VERSION 5.8 ;
BUSBITCHARS "[]" ;
DIVIDERCHAR "/" ;
UNITS
    DATABASE MICRONS 1000 ;
END UNITS

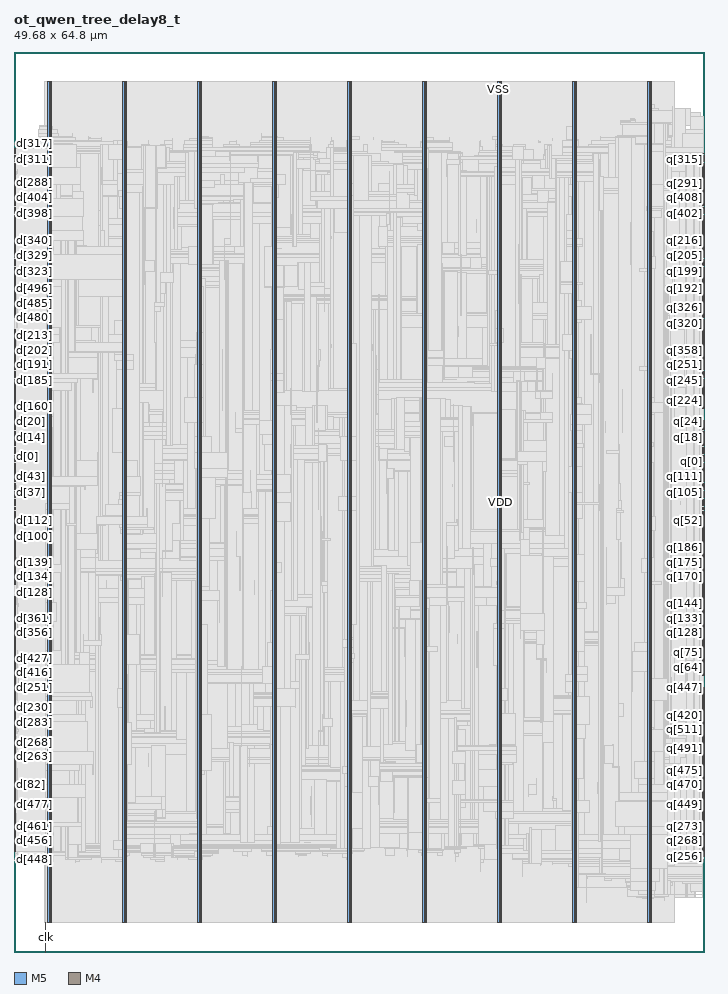
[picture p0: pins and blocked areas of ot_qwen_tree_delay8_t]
MACRO ot_qwen_tree_delay8_t
  FOREIGN ot_qwen_tree_delay8_t 0 0 ;
  CLASS BLOCK ;
  SIZE 49.68 BY 64.8 ;
  PIN clk
    DIRECTION INPUT ;
    USE SIGNAL ;
    PORT
      LAYER M5 ;
        RECT  2.256 0 2.28 0.084 ;
    END
    PORT
      LAYER M5 ;
        RECT  2.256 0.016 2.28 2.137 ;
    END
  END clk
  PIN d[0]
    DIRECTION INPUT ;
    USE SIGNAL ;
    PORT
      LAYER M4 ;
        RECT  0 35.664 0.084 35.688 ;
    END
  END d[0]
  PIN d[100]
    DIRECTION INPUT ;
    USE SIGNAL ;
    PORT
      LAYER M4 ;
        RECT  0 29.904 0.084 29.928 ;
    END
  END d[100]
  PIN d[101]
    DIRECTION INPUT ;
    USE SIGNAL ;
    PORT
      LAYER M4 ;
        RECT  0 30 0.084 30.024 ;
    END
  END d[101]
  PIN d[102]
    DIRECTION INPUT ;
    USE SIGNAL ;
    PORT
      LAYER M4 ;
        RECT  0 30.096 0.084 30.12 ;
    END
  END d[102]
  PIN d[103]
    DIRECTION INPUT ;
    USE SIGNAL ;
    PORT
      LAYER M4 ;
        RECT  0 30.192 0.084 30.216 ;
    END
  END d[103]
  PIN d[104]
    DIRECTION INPUT ;
    USE SIGNAL ;
    PORT
      LAYER M4 ;
        RECT  0 30.288 0.084 30.312 ;
    END
  END d[104]
  PIN d[105]
    DIRECTION INPUT ;
    USE SIGNAL ;
    PORT
      LAYER M4 ;
        RECT  0 30.384 0.084 30.408 ;
    END
  END d[105]
  PIN d[106]
    DIRECTION INPUT ;
    USE SIGNAL ;
    PORT
      LAYER M4 ;
        RECT  0 30.48 0.084 30.504 ;
    END
  END d[106]
  PIN d[107]
    DIRECTION INPUT ;
    USE SIGNAL ;
    PORT
      LAYER M4 ;
        RECT  0 30.576 0.084 30.6 ;
    END
  END d[107]
  PIN d[108]
    DIRECTION INPUT ;
    USE SIGNAL ;
    PORT
      LAYER M4 ;
        RECT  0 30.672 0.084 30.696 ;
    END
  END d[108]
  PIN d[109]
    DIRECTION INPUT ;
    USE SIGNAL ;
    PORT
      LAYER M4 ;
        RECT  0 30.768 0.084 30.792 ;
    END
  END d[109]
  PIN d[10]
    DIRECTION INPUT ;
    USE SIGNAL ;
    PORT
      LAYER M4 ;
        RECT  0 36.624 0.084 36.648 ;
    END
  END d[10]
  PIN d[110]
    DIRECTION INPUT ;
    USE SIGNAL ;
    PORT
      LAYER M4 ;
        RECT  0 30.864 0.084 30.888 ;
    END
  END d[110]
  PIN d[111]
    DIRECTION INPUT ;
    USE SIGNAL ;
    PORT
      LAYER M4 ;
        RECT  0 30.96 0.084 30.984 ;
    END
  END d[111]
  PIN d[112]
    DIRECTION INPUT ;
    USE SIGNAL ;
    PORT
      LAYER M4 ;
        RECT  0 31.056 0.084 31.08 ;
    END
  END d[112]
  PIN d[113]
    DIRECTION INPUT ;
    USE SIGNAL ;
    PORT
      LAYER M4 ;
        RECT  0 31.152 0.084 31.176 ;
    END
  END d[113]
  PIN d[114]
    DIRECTION INPUT ;
    USE SIGNAL ;
    PORT
      LAYER M4 ;
        RECT  0 31.248 0.084 31.272 ;
    END
  END d[114]
  PIN d[115]
    DIRECTION INPUT ;
    USE SIGNAL ;
    PORT
      LAYER M4 ;
        RECT  0 31.344 0.084 31.368 ;
    END
  END d[115]
  PIN d[116]
    DIRECTION INPUT ;
    USE SIGNAL ;
    PORT
      LAYER M4 ;
        RECT  0 31.44 0.084 31.464 ;
    END
  END d[116]
  PIN d[117]
    DIRECTION INPUT ;
    USE SIGNAL ;
    PORT
      LAYER M4 ;
        RECT  0 31.536 0.084 31.56 ;
    END
  END d[117]
  PIN d[118]
    DIRECTION INPUT ;
    USE SIGNAL ;
    PORT
      LAYER M4 ;
        RECT  0 31.632 0.084 31.656 ;
    END
  END d[118]
  PIN d[119]
    DIRECTION INPUT ;
    USE SIGNAL ;
    PORT
      LAYER M4 ;
        RECT  0 31.728 0.084 31.752 ;
    END
  END d[119]
  PIN d[11]
    DIRECTION INPUT ;
    USE SIGNAL ;
    PORT
      LAYER M4 ;
        RECT  0 36.72 0.084 36.744 ;
    END
  END d[11]
  PIN d[120]
    DIRECTION INPUT ;
    USE SIGNAL ;
    PORT
      LAYER M4 ;
        RECT  0 31.824 0.084 31.848 ;
    END
  END d[120]
  PIN d[121]
    DIRECTION INPUT ;
    USE SIGNAL ;
    PORT
      LAYER M4 ;
        RECT  0 31.92 0.084 31.944 ;
    END
  END d[121]
  PIN d[122]
    DIRECTION INPUT ;
    USE SIGNAL ;
    PORT
      LAYER M4 ;
        RECT  0 32.016 0.084 32.04 ;
    END
  END d[122]
  PIN d[123]
    DIRECTION INPUT ;
    USE SIGNAL ;
    PORT
      LAYER M4 ;
        RECT  0 32.112 0.084 32.136 ;
    END
  END d[123]
  PIN d[124]
    DIRECTION INPUT ;
    USE SIGNAL ;
    PORT
      LAYER M4 ;
        RECT  0 32.208 0.084 32.232 ;
    END
  END d[124]
  PIN d[125]
    DIRECTION INPUT ;
    USE SIGNAL ;
    PORT
      LAYER M4 ;
        RECT  0 32.304 0.084 32.328 ;
    END
  END d[125]
  PIN d[126]
    DIRECTION INPUT ;
    USE SIGNAL ;
    PORT
      LAYER M4 ;
        RECT  0 32.4 0.084 32.424 ;
    END
  END d[126]
  PIN d[127]
    DIRECTION INPUT ;
    USE SIGNAL ;
    PORT
      LAYER M4 ;
        RECT  0 32.496 0.084 32.52 ;
    END
  END d[127]
  PIN d[128]
    DIRECTION INPUT ;
    USE SIGNAL ;
    PORT
      LAYER M4 ;
        RECT  0 26.448 0.084 26.472 ;
    END
  END d[128]
  PIN d[129]
    DIRECTION INPUT ;
    USE SIGNAL ;
    PORT
      LAYER M4 ;
        RECT  0 26.544 0.084 26.568 ;
    END
  END d[129]
  PIN d[12]
    DIRECTION INPUT ;
    USE SIGNAL ;
    PORT
      LAYER M4 ;
        RECT  0 36.816 0.084 36.84 ;
    END
  END d[12]
  PIN d[130]
    DIRECTION INPUT ;
    USE SIGNAL ;
    PORT
      LAYER M4 ;
        RECT  0 26.64 0.084 26.664 ;
    END
  END d[130]
  PIN d[131]
    DIRECTION INPUT ;
    USE SIGNAL ;
    PORT
      LAYER M4 ;
        RECT  0 26.736 0.084 26.76 ;
    END
  END d[131]
  PIN d[132]
    DIRECTION INPUT ;
    USE SIGNAL ;
    PORT
      LAYER M4 ;
        RECT  0 26.832 0.084 26.856 ;
    END
  END d[132]
  PIN d[133]
    DIRECTION INPUT ;
    USE SIGNAL ;
    PORT
      LAYER M4 ;
        RECT  0 26.928 0.084 26.952 ;
    END
  END d[133]
  PIN d[134]
    DIRECTION INPUT ;
    USE SIGNAL ;
    PORT
      LAYER M4 ;
        RECT  0 27.024 0.084 27.048 ;
    END
  END d[134]
  PIN d[135]
    DIRECTION INPUT ;
    USE SIGNAL ;
    PORT
      LAYER M4 ;
        RECT  0 27.12 0.084 27.144 ;
    END
  END d[135]
  PIN d[136]
    DIRECTION INPUT ;
    USE SIGNAL ;
    PORT
      LAYER M4 ;
        RECT  0 27.216 0.084 27.24 ;
    END
  END d[136]
  PIN d[137]
    DIRECTION INPUT ;
    USE SIGNAL ;
    PORT
      LAYER M4 ;
        RECT  0 27.312 0.084 27.336 ;
    END
  END d[137]
  PIN d[138]
    DIRECTION INPUT ;
    USE SIGNAL ;
    PORT
      LAYER M4 ;
        RECT  0 27.408 0.084 27.432 ;
    END
  END d[138]
  PIN d[139]
    DIRECTION INPUT ;
    USE SIGNAL ;
    PORT
      LAYER M4 ;
        RECT  0 27.504 0.084 27.528 ;
    END
  END d[139]
  PIN d[13]
    DIRECTION INPUT ;
    USE SIGNAL ;
    PORT
      LAYER M4 ;
        RECT  0 36.912 0.084 36.936 ;
    END
  END d[13]
  PIN d[140]
    DIRECTION INPUT ;
    USE SIGNAL ;
    PORT
      LAYER M4 ;
        RECT  0 27.6 0.084 27.624 ;
    END
  END d[140]
  PIN d[141]
    DIRECTION INPUT ;
    USE SIGNAL ;
    PORT
      LAYER M4 ;
        RECT  0 27.696 0.084 27.72 ;
    END
  END d[141]
  PIN d[142]
    DIRECTION INPUT ;
    USE SIGNAL ;
    PORT
      LAYER M4 ;
        RECT  0 27.792 0.084 27.816 ;
    END
  END d[142]
  PIN d[143]
    DIRECTION INPUT ;
    USE SIGNAL ;
    PORT
      LAYER M4 ;
        RECT  0 27.888 0.084 27.912 ;
    END
  END d[143]
  PIN d[144]
    DIRECTION INPUT ;
    USE SIGNAL ;
    PORT
      LAYER M4 ;
        RECT  0 27.984 0.084 28.008 ;
    END
  END d[144]
  PIN d[145]
    DIRECTION INPUT ;
    USE SIGNAL ;
    PORT
      LAYER M4 ;
        RECT  0 28.08 0.084 28.104 ;
    END
  END d[145]
  PIN d[146]
    DIRECTION INPUT ;
    USE SIGNAL ;
    PORT
      LAYER M4 ;
        RECT  0 28.176 0.084 28.2 ;
    END
  END d[146]
  PIN d[147]
    DIRECTION INPUT ;
    USE SIGNAL ;
    PORT
      LAYER M4 ;
        RECT  0 28.272 0.084 28.296 ;
    END
  END d[147]
  PIN d[148]
    DIRECTION INPUT ;
    USE SIGNAL ;
    PORT
      LAYER M4 ;
        RECT  0 28.368 0.084 28.392 ;
    END
  END d[148]
  PIN d[149]
    DIRECTION INPUT ;
    USE SIGNAL ;
    PORT
      LAYER M4 ;
        RECT  0 28.464 0.084 28.488 ;
    END
  END d[149]
  PIN d[14]
    DIRECTION INPUT ;
    USE SIGNAL ;
    PORT
      LAYER M4 ;
        RECT  0 37.008 0.084 37.032 ;
    END
  END d[14]
  PIN d[150]
    DIRECTION INPUT ;
    USE SIGNAL ;
    PORT
      LAYER M4 ;
        RECT  0 28.56 0.084 28.584 ;
    END
  END d[150]
  PIN d[151]
    DIRECTION INPUT ;
    USE SIGNAL ;
    PORT
      LAYER M4 ;
        RECT  0 28.656 0.084 28.68 ;
    END
  END d[151]
  PIN d[152]
    DIRECTION INPUT ;
    USE SIGNAL ;
    PORT
      LAYER M4 ;
        RECT  0 28.752 0.084 28.776 ;
    END
  END d[152]
  PIN d[153]
    DIRECTION INPUT ;
    USE SIGNAL ;
    PORT
      LAYER M4 ;
        RECT  0 28.848 0.084 28.872 ;
    END
  END d[153]
  PIN d[154]
    DIRECTION INPUT ;
    USE SIGNAL ;
    PORT
      LAYER M4 ;
        RECT  0 28.944 0.084 28.968 ;
    END
  END d[154]
  PIN d[155]
    DIRECTION INPUT ;
    USE SIGNAL ;
    PORT
      LAYER M4 ;
        RECT  0 29.04 0.084 29.064 ;
    END
  END d[155]
  PIN d[156]
    DIRECTION INPUT ;
    USE SIGNAL ;
    PORT
      LAYER M4 ;
        RECT  0 29.136 0.084 29.16 ;
    END
  END d[156]
  PIN d[157]
    DIRECTION INPUT ;
    USE SIGNAL ;
    PORT
      LAYER M4 ;
        RECT  0 29.232 0.084 29.256 ;
    END
  END d[157]
  PIN d[158]
    DIRECTION INPUT ;
    USE SIGNAL ;
    PORT
      LAYER M4 ;
        RECT  0 29.328 0.084 29.352 ;
    END
  END d[158]
  PIN d[159]
    DIRECTION INPUT ;
    USE SIGNAL ;
    PORT
      LAYER M4 ;
        RECT  0 29.424 0.084 29.448 ;
    END
  END d[159]
  PIN d[15]
    DIRECTION INPUT ;
    USE SIGNAL ;
    PORT
      LAYER M4 ;
        RECT  0 37.104 0.084 37.128 ;
    END
  END d[15]
  PIN d[160]
    DIRECTION INPUT ;
    USE SIGNAL ;
    PORT
      LAYER M4 ;
        RECT  0 38.736 0.084 38.76 ;
    END
  END d[160]
  PIN d[161]
    DIRECTION INPUT ;
    USE SIGNAL ;
    PORT
      LAYER M4 ;
        RECT  0 38.832 0.084 38.856 ;
    END
  END d[161]
  PIN d[162]
    DIRECTION INPUT ;
    USE SIGNAL ;
    PORT
      LAYER M4 ;
        RECT  0 38.928 0.084 38.952 ;
    END
  END d[162]
  PIN d[163]
    DIRECTION INPUT ;
    USE SIGNAL ;
    PORT
      LAYER M4 ;
        RECT  0 39.024 0.084 39.048 ;
    END
  END d[163]
  PIN d[164]
    DIRECTION INPUT ;
    USE SIGNAL ;
    PORT
      LAYER M4 ;
        RECT  0 39.12 0.084 39.144 ;
    END
  END d[164]
  PIN d[165]
    DIRECTION INPUT ;
    USE SIGNAL ;
    PORT
      LAYER M4 ;
        RECT  0 39.216 0.084 39.24 ;
    END
  END d[165]
  PIN d[166]
    DIRECTION INPUT ;
    USE SIGNAL ;
    PORT
      LAYER M4 ;
        RECT  0 39.312 0.084 39.336 ;
    END
  END d[166]
  PIN d[167]
    DIRECTION INPUT ;
    USE SIGNAL ;
    PORT
      LAYER M4 ;
        RECT  0 39.408 0.084 39.432 ;
    END
  END d[167]
  PIN d[168]
    DIRECTION INPUT ;
    USE SIGNAL ;
    PORT
      LAYER M4 ;
        RECT  0 39.504 0.084 39.528 ;
    END
  END d[168]
  PIN d[169]
    DIRECTION INPUT ;
    USE SIGNAL ;
    PORT
      LAYER M4 ;
        RECT  0 39.6 0.084 39.624 ;
    END
  END d[169]
  PIN d[16]
    DIRECTION INPUT ;
    USE SIGNAL ;
    PORT
      LAYER M4 ;
        RECT  0 37.2 0.084 37.224 ;
    END
  END d[16]
  PIN d[170]
    DIRECTION INPUT ;
    USE SIGNAL ;
    PORT
      LAYER M4 ;
        RECT  0 39.696 0.084 39.72 ;
    END
  END d[170]
  PIN d[171]
    DIRECTION INPUT ;
    USE SIGNAL ;
    PORT
      LAYER M4 ;
        RECT  0 39.792 0.084 39.816 ;
    END
  END d[171]
  PIN d[172]
    DIRECTION INPUT ;
    USE SIGNAL ;
    PORT
      LAYER M4 ;
        RECT  0 39.888 0.084 39.912 ;
    END
  END d[172]
  PIN d[173]
    DIRECTION INPUT ;
    USE SIGNAL ;
    PORT
      LAYER M4 ;
        RECT  0 39.984 0.084 40.008 ;
    END
  END d[173]
  PIN d[174]
    DIRECTION INPUT ;
    USE SIGNAL ;
    PORT
      LAYER M4 ;
        RECT  0 40.08 0.084 40.104 ;
    END
  END d[174]
  PIN d[175]
    DIRECTION INPUT ;
    USE SIGNAL ;
    PORT
      LAYER M4 ;
        RECT  0 40.176 0.084 40.2 ;
    END
  END d[175]
  PIN d[176]
    DIRECTION INPUT ;
    USE SIGNAL ;
    PORT
      LAYER M4 ;
        RECT  0 40.272 0.084 40.296 ;
    END
  END d[176]
  PIN d[177]
    DIRECTION INPUT ;
    USE SIGNAL ;
    PORT
      LAYER M4 ;
        RECT  0 40.368 0.084 40.392 ;
    END
  END d[177]
  PIN d[178]
    DIRECTION INPUT ;
    USE SIGNAL ;
    PORT
      LAYER M4 ;
        RECT  0 40.464 0.084 40.488 ;
    END
  END d[178]
  PIN d[179]
    DIRECTION INPUT ;
    USE SIGNAL ;
    PORT
      LAYER M4 ;
        RECT  0 40.56 0.084 40.584 ;
    END
  END d[179]
  PIN d[17]
    DIRECTION INPUT ;
    USE SIGNAL ;
    PORT
      LAYER M4 ;
        RECT  0 37.296 0.084 37.32 ;
    END
  END d[17]
  PIN d[180]
    DIRECTION INPUT ;
    USE SIGNAL ;
    PORT
      LAYER M4 ;
        RECT  0 40.656 0.084 40.68 ;
    END
  END d[180]
  PIN d[181]
    DIRECTION INPUT ;
    USE SIGNAL ;
    PORT
      LAYER M4 ;
        RECT  0 40.752 0.084 40.776 ;
    END
  END d[181]
  PIN d[182]
    DIRECTION INPUT ;
    USE SIGNAL ;
    PORT
      LAYER M4 ;
        RECT  0 40.848 0.084 40.872 ;
    END
  END d[182]
  PIN d[183]
    DIRECTION INPUT ;
    USE SIGNAL ;
    PORT
      LAYER M4 ;
        RECT  0 40.944 0.084 40.968 ;
    END
  END d[183]
  PIN d[184]
    DIRECTION INPUT ;
    USE SIGNAL ;
    PORT
      LAYER M4 ;
        RECT  0 41.04 0.084 41.064 ;
    END
  END d[184]
  PIN d[185]
    DIRECTION INPUT ;
    USE SIGNAL ;
    PORT
      LAYER M4 ;
        RECT  0 41.136 0.084 41.16 ;
    END
  END d[185]
  PIN d[186]
    DIRECTION INPUT ;
    USE SIGNAL ;
    PORT
      LAYER M4 ;
        RECT  0 41.232 0.084 41.256 ;
    END
  END d[186]
  PIN d[187]
    DIRECTION INPUT ;
    USE SIGNAL ;
    PORT
      LAYER M4 ;
        RECT  0 41.328 0.084 41.352 ;
    END
  END d[187]
  PIN d[188]
    DIRECTION INPUT ;
    USE SIGNAL ;
    PORT
      LAYER M4 ;
        RECT  0 41.424 0.084 41.448 ;
    END
  END d[188]
  PIN d[189]
    DIRECTION INPUT ;
    USE SIGNAL ;
    PORT
      LAYER M4 ;
        RECT  0 41.52 0.084 41.544 ;
    END
  END d[189]
  PIN d[18]
    DIRECTION INPUT ;
    USE SIGNAL ;
    PORT
      LAYER M4 ;
        RECT  0 37.392 0.084 37.416 ;
    END
  END d[18]
  PIN d[190]
    DIRECTION INPUT ;
    USE SIGNAL ;
    PORT
      LAYER M4 ;
        RECT  0 41.616 0.084 41.64 ;
    END
  END d[190]
  PIN d[191]
    DIRECTION INPUT ;
    USE SIGNAL ;
    PORT
      LAYER M4 ;
        RECT  0 41.712 0.084 41.736 ;
    END
  END d[191]
  PIN d[192]
    DIRECTION INPUT ;
    USE SIGNAL ;
    PORT
      LAYER M4 ;
        RECT  0 41.808 0.084 41.832 ;
    END
  END d[192]
  PIN d[193]
    DIRECTION INPUT ;
    USE SIGNAL ;
    PORT
      LAYER M4 ;
        RECT  0 41.904 0.084 41.928 ;
    END
  END d[193]
  PIN d[194]
    DIRECTION INPUT ;
    USE SIGNAL ;
    PORT
      LAYER M4 ;
        RECT  0 42 0.084 42.024 ;
    END
  END d[194]
  PIN d[195]
    DIRECTION INPUT ;
    USE SIGNAL ;
    PORT
      LAYER M4 ;
        RECT  0 42.096 0.084 42.12 ;
    END
  END d[195]
  PIN d[196]
    DIRECTION INPUT ;
    USE SIGNAL ;
    PORT
      LAYER M4 ;
        RECT  0 42.192 0.084 42.216 ;
    END
  END d[196]
  PIN d[197]
    DIRECTION INPUT ;
    USE SIGNAL ;
    PORT
      LAYER M4 ;
        RECT  0 42.288 0.084 42.312 ;
    END
  END d[197]
  PIN d[198]
    DIRECTION INPUT ;
    USE SIGNAL ;
    PORT
      LAYER M4 ;
        RECT  0 42.384 0.084 42.408 ;
    END
  END d[198]
  PIN d[199]
    DIRECTION INPUT ;
    USE SIGNAL ;
    PORT
      LAYER M4 ;
        RECT  0 42.48 0.084 42.504 ;
    END
  END d[199]
  PIN d[19]
    DIRECTION INPUT ;
    USE SIGNAL ;
    PORT
      LAYER M4 ;
        RECT  0 37.488 0.084 37.512 ;
    END
  END d[19]
  PIN d[1]
    DIRECTION INPUT ;
    USE SIGNAL ;
    PORT
      LAYER M4 ;
        RECT  0 35.76 0.084 35.784 ;
    END
  END d[1]
  PIN d[200]
    DIRECTION INPUT ;
    USE SIGNAL ;
    PORT
      LAYER M4 ;
        RECT  0 42.576 0.084 42.6 ;
    END
  END d[200]
  PIN d[201]
    DIRECTION INPUT ;
    USE SIGNAL ;
    PORT
      LAYER M4 ;
        RECT  0 42.672 0.084 42.696 ;
    END
  END d[201]
  PIN d[202]
    DIRECTION INPUT ;
    USE SIGNAL ;
    PORT
      LAYER M4 ;
        RECT  0 42.768 0.084 42.792 ;
    END
  END d[202]
  PIN d[203]
    DIRECTION INPUT ;
    USE SIGNAL ;
    PORT
      LAYER M4 ;
        RECT  0 42.864 0.084 42.888 ;
    END
  END d[203]
  PIN d[204]
    DIRECTION INPUT ;
    USE SIGNAL ;
    PORT
      LAYER M4 ;
        RECT  0 42.96 0.084 42.984 ;
    END
  END d[204]
  PIN d[205]
    DIRECTION INPUT ;
    USE SIGNAL ;
    PORT
      LAYER M4 ;
        RECT  0 43.056 0.084 43.08 ;
    END
  END d[205]
  PIN d[206]
    DIRECTION INPUT ;
    USE SIGNAL ;
    PORT
      LAYER M4 ;
        RECT  0 43.152 0.084 43.176 ;
    END
  END d[206]
  PIN d[207]
    DIRECTION INPUT ;
    USE SIGNAL ;
    PORT
      LAYER M4 ;
        RECT  0 43.248 0.084 43.272 ;
    END
  END d[207]
  PIN d[208]
    DIRECTION INPUT ;
    USE SIGNAL ;
    PORT
      LAYER M4 ;
        RECT  0 43.344 0.084 43.368 ;
    END
  END d[208]
  PIN d[209]
    DIRECTION INPUT ;
    USE SIGNAL ;
    PORT
      LAYER M4 ;
        RECT  0 43.44 0.084 43.464 ;
    END
  END d[209]
  PIN d[20]
    DIRECTION INPUT ;
    USE SIGNAL ;
    PORT
      LAYER M4 ;
        RECT  0 37.584 0.084 37.608 ;
    END
  END d[20]
  PIN d[210]
    DIRECTION INPUT ;
    USE SIGNAL ;
    PORT
      LAYER M4 ;
        RECT  0 43.536 0.084 43.56 ;
    END
  END d[210]
  PIN d[211]
    DIRECTION INPUT ;
    USE SIGNAL ;
    PORT
      LAYER M4 ;
        RECT  0 43.632 0.084 43.656 ;
    END
  END d[211]
  PIN d[212]
    DIRECTION INPUT ;
    USE SIGNAL ;
    PORT
      LAYER M4 ;
        RECT  0 43.728 0.084 43.752 ;
    END
  END d[212]
  PIN d[213]
    DIRECTION INPUT ;
    USE SIGNAL ;
    PORT
      LAYER M4 ;
        RECT  0 43.824 0.084 43.848 ;
    END
  END d[213]
  PIN d[214]
    DIRECTION INPUT ;
    USE SIGNAL ;
    PORT
      LAYER M4 ;
        RECT  0 43.92 0.084 43.944 ;
    END
  END d[214]
  PIN d[215]
    DIRECTION INPUT ;
    USE SIGNAL ;
    PORT
      LAYER M4 ;
        RECT  0 44.016 0.084 44.04 ;
    END
  END d[215]
  PIN d[216]
    DIRECTION INPUT ;
    USE SIGNAL ;
    PORT
      LAYER M4 ;
        RECT  0 44.112 0.084 44.136 ;
    END
  END d[216]
  PIN d[217]
    DIRECTION INPUT ;
    USE SIGNAL ;
    PORT
      LAYER M4 ;
        RECT  0 44.208 0.084 44.232 ;
    END
  END d[217]
  PIN d[218]
    DIRECTION INPUT ;
    USE SIGNAL ;
    PORT
      LAYER M4 ;
        RECT  0 44.304 0.084 44.328 ;
    END
  END d[218]
  PIN d[219]
    DIRECTION INPUT ;
    USE SIGNAL ;
    PORT
      LAYER M4 ;
        RECT  0 44.4 0.084 44.424 ;
    END
  END d[219]
  PIN d[21]
    DIRECTION INPUT ;
    USE SIGNAL ;
    PORT
      LAYER M4 ;
        RECT  0 37.68 0.084 37.704 ;
    END
  END d[21]
  PIN d[220]
    DIRECTION INPUT ;
    USE SIGNAL ;
    PORT
      LAYER M4 ;
        RECT  0 44.496 0.084 44.52 ;
    END
  END d[220]
  PIN d[221]
    DIRECTION INPUT ;
    USE SIGNAL ;
    PORT
      LAYER M4 ;
        RECT  0 44.592 0.084 44.616 ;
    END
  END d[221]
  PIN d[222]
    DIRECTION INPUT ;
    USE SIGNAL ;
    PORT
      LAYER M4 ;
        RECT  0 44.688 0.084 44.712 ;
    END
  END d[222]
  PIN d[223]
    DIRECTION INPUT ;
    USE SIGNAL ;
    PORT
      LAYER M4 ;
        RECT  0 44.784 0.084 44.808 ;
    END
  END d[223]
  PIN d[224]
    DIRECTION INPUT ;
    USE SIGNAL ;
    PORT
      LAYER M4 ;
        RECT  0 16.464 0.084 16.488 ;
    END
  END d[224]
  PIN d[225]
    DIRECTION INPUT ;
    USE SIGNAL ;
    PORT
      LAYER M4 ;
        RECT  0 16.56 0.084 16.584 ;
    END
  END d[225]
  PIN d[226]
    DIRECTION INPUT ;
    USE SIGNAL ;
    PORT
      LAYER M4 ;
        RECT  0 16.656 0.084 16.68 ;
    END
  END d[226]
  PIN d[227]
    DIRECTION INPUT ;
    USE SIGNAL ;
    PORT
      LAYER M4 ;
        RECT  0 16.752 0.084 16.776 ;
    END
  END d[227]
  PIN d[228]
    DIRECTION INPUT ;
    USE SIGNAL ;
    PORT
      LAYER M4 ;
        RECT  0 16.848 0.084 16.872 ;
    END
  END d[228]
  PIN d[229]
    DIRECTION INPUT ;
    USE SIGNAL ;
    PORT
      LAYER M4 ;
        RECT  0 16.944 0.084 16.968 ;
    END
  END d[229]
  PIN d[22]
    DIRECTION INPUT ;
    USE SIGNAL ;
    PORT
      LAYER M4 ;
        RECT  0 37.776 0.084 37.8 ;
    END
  END d[22]
  PIN d[230]
    DIRECTION INPUT ;
    USE SIGNAL ;
    PORT
      LAYER M4 ;
        RECT  0 17.04 0.084 17.064 ;
    END
  END d[230]
  PIN d[231]
    DIRECTION INPUT ;
    USE SIGNAL ;
    PORT
      LAYER M4 ;
        RECT  0 17.136 0.084 17.16 ;
    END
  END d[231]
  PIN d[232]
    DIRECTION INPUT ;
    USE SIGNAL ;
    PORT
      LAYER M4 ;
        RECT  0 17.232 0.084 17.256 ;
    END
  END d[232]
  PIN d[233]
    DIRECTION INPUT ;
    USE SIGNAL ;
    PORT
      LAYER M4 ;
        RECT  0 17.328 0.084 17.352 ;
    END
  END d[233]
  PIN d[234]
    DIRECTION INPUT ;
    USE SIGNAL ;
    PORT
      LAYER M4 ;
        RECT  0 17.424 0.084 17.448 ;
    END
  END d[234]
  PIN d[235]
    DIRECTION INPUT ;
    USE SIGNAL ;
    PORT
      LAYER M4 ;
        RECT  0 17.52 0.084 17.544 ;
    END
  END d[235]
  PIN d[236]
    DIRECTION INPUT ;
    USE SIGNAL ;
    PORT
      LAYER M4 ;
        RECT  0 17.616 0.084 17.64 ;
    END
  END d[236]
  PIN d[237]
    DIRECTION INPUT ;
    USE SIGNAL ;
    PORT
      LAYER M4 ;
        RECT  0 17.712 0.084 17.736 ;
    END
  END d[237]
  PIN d[238]
    DIRECTION INPUT ;
    USE SIGNAL ;
    PORT
      LAYER M4 ;
        RECT  0 17.808 0.084 17.832 ;
    END
  END d[238]
  PIN d[239]
    DIRECTION INPUT ;
    USE SIGNAL ;
    PORT
      LAYER M4 ;
        RECT  0 17.904 0.084 17.928 ;
    END
  END d[239]
  PIN d[23]
    DIRECTION INPUT ;
    USE SIGNAL ;
    PORT
      LAYER M4 ;
        RECT  0 37.872 0.084 37.896 ;
    END
  END d[23]
  PIN d[240]
    DIRECTION INPUT ;
    USE SIGNAL ;
    PORT
      LAYER M4 ;
        RECT  0 18 0.084 18.024 ;
    END
  END d[240]
  PIN d[241]
    DIRECTION INPUT ;
    USE SIGNAL ;
    PORT
      LAYER M4 ;
        RECT  0 18.096 0.084 18.12 ;
    END
  END d[241]
  PIN d[242]
    DIRECTION INPUT ;
    USE SIGNAL ;
    PORT
      LAYER M4 ;
        RECT  0 18.192 0.084 18.216 ;
    END
  END d[242]
  PIN d[243]
    DIRECTION INPUT ;
    USE SIGNAL ;
    PORT
      LAYER M4 ;
        RECT  0 18.288 0.084 18.312 ;
    END
  END d[243]
  PIN d[244]
    DIRECTION INPUT ;
    USE SIGNAL ;
    PORT
      LAYER M4 ;
        RECT  0 18.384 0.084 18.408 ;
    END
  END d[244]
  PIN d[245]
    DIRECTION INPUT ;
    USE SIGNAL ;
    PORT
      LAYER M4 ;
        RECT  0 18.48 0.084 18.504 ;
    END
  END d[245]
  PIN d[246]
    DIRECTION INPUT ;
    USE SIGNAL ;
    PORT
      LAYER M4 ;
        RECT  0 18.576 0.084 18.6 ;
    END
  END d[246]
  PIN d[247]
    DIRECTION INPUT ;
    USE SIGNAL ;
    PORT
      LAYER M4 ;
        RECT  0 18.672 0.084 18.696 ;
    END
  END d[247]
  PIN d[248]
    DIRECTION INPUT ;
    USE SIGNAL ;
    PORT
      LAYER M4 ;
        RECT  0 18.768 0.084 18.792 ;
    END
  END d[248]
  PIN d[249]
    DIRECTION INPUT ;
    USE SIGNAL ;
    PORT
      LAYER M4 ;
        RECT  0 18.864 0.084 18.888 ;
    END
  END d[249]
  PIN d[24]
    DIRECTION INPUT ;
    USE SIGNAL ;
    PORT
      LAYER M4 ;
        RECT  0 37.968 0.084 37.992 ;
    END
  END d[24]
  PIN d[250]
    DIRECTION INPUT ;
    USE SIGNAL ;
    PORT
      LAYER M4 ;
        RECT  0 18.96 0.084 18.984 ;
    END
  END d[250]
  PIN d[251]
    DIRECTION INPUT ;
    USE SIGNAL ;
    PORT
      LAYER M4 ;
        RECT  0 19.056 0.084 19.08 ;
    END
  END d[251]
  PIN d[252]
    DIRECTION INPUT ;
    USE SIGNAL ;
    PORT
      LAYER M4 ;
        RECT  0 19.152 0.084 19.176 ;
    END
  END d[252]
  PIN d[253]
    DIRECTION INPUT ;
    USE SIGNAL ;
    PORT
      LAYER M4 ;
        RECT  0 19.248 0.084 19.272 ;
    END
  END d[253]
  PIN d[254]
    DIRECTION INPUT ;
    USE SIGNAL ;
    PORT
      LAYER M4 ;
        RECT  0 19.344 0.084 19.368 ;
    END
  END d[254]
  PIN d[255]
    DIRECTION INPUT ;
    USE SIGNAL ;
    PORT
      LAYER M4 ;
        RECT  0 19.44 0.084 19.464 ;
    END
  END d[255]
  PIN d[256]
    DIRECTION INPUT ;
    USE SIGNAL ;
    PORT
      LAYER M4 ;
        RECT  0 13.392 0.084 13.416 ;
    END
  END d[256]
  PIN d[257]
    DIRECTION INPUT ;
    USE SIGNAL ;
    PORT
      LAYER M4 ;
        RECT  0 13.488 0.084 13.512 ;
    END
  END d[257]
  PIN d[258]
    DIRECTION INPUT ;
    USE SIGNAL ;
    PORT
      LAYER M4 ;
        RECT  0 13.584 0.084 13.608 ;
    END
  END d[258]
  PIN d[259]
    DIRECTION INPUT ;
    USE SIGNAL ;
    PORT
      LAYER M4 ;
        RECT  0 13.68 0.084 13.704 ;
    END
  END d[259]
  PIN d[25]
    DIRECTION INPUT ;
    USE SIGNAL ;
    PORT
      LAYER M4 ;
        RECT  0 38.064 0.084 38.088 ;
    END
  END d[25]
  PIN d[260]
    DIRECTION INPUT ;
    USE SIGNAL ;
    PORT
      LAYER M4 ;
        RECT  0 13.776 0.084 13.8 ;
    END
  END d[260]
  PIN d[261]
    DIRECTION INPUT ;
    USE SIGNAL ;
    PORT
      LAYER M4 ;
        RECT  0 13.872 0.084 13.896 ;
    END
  END d[261]
  PIN d[262]
    DIRECTION INPUT ;
    USE SIGNAL ;
    PORT
      LAYER M4 ;
        RECT  0 13.968 0.084 13.992 ;
    END
  END d[262]
  PIN d[263]
    DIRECTION INPUT ;
    USE SIGNAL ;
    PORT
      LAYER M4 ;
        RECT  0 14.064 0.084 14.088 ;
    END
  END d[263]
  PIN d[264]
    DIRECTION INPUT ;
    USE SIGNAL ;
    PORT
      LAYER M4 ;
        RECT  0 14.16 0.084 14.184 ;
    END
  END d[264]
  PIN d[265]
    DIRECTION INPUT ;
    USE SIGNAL ;
    PORT
      LAYER M4 ;
        RECT  0 14.256 0.084 14.28 ;
    END
  END d[265]
  PIN d[266]
    DIRECTION INPUT ;
    USE SIGNAL ;
    PORT
      LAYER M4 ;
        RECT  0 14.352 0.084 14.376 ;
    END
  END d[266]
  PIN d[267]
    DIRECTION INPUT ;
    USE SIGNAL ;
    PORT
      LAYER M4 ;
        RECT  0 14.448 0.084 14.472 ;
    END
  END d[267]
  PIN d[268]
    DIRECTION INPUT ;
    USE SIGNAL ;
    PORT
      LAYER M4 ;
        RECT  0 14.544 0.084 14.568 ;
    END
  END d[268]
  PIN d[269]
    DIRECTION INPUT ;
    USE SIGNAL ;
    PORT
      LAYER M4 ;
        RECT  0 14.64 0.084 14.664 ;
    END
  END d[269]
  PIN d[26]
    DIRECTION INPUT ;
    USE SIGNAL ;
    PORT
      LAYER M4 ;
        RECT  0 38.16 0.084 38.184 ;
    END
  END d[26]
  PIN d[270]
    DIRECTION INPUT ;
    USE SIGNAL ;
    PORT
      LAYER M4 ;
        RECT  0 14.736 0.084 14.76 ;
    END
  END d[270]
  PIN d[271]
    DIRECTION INPUT ;
    USE SIGNAL ;
    PORT
      LAYER M4 ;
        RECT  0 14.832 0.084 14.856 ;
    END
  END d[271]
  PIN d[272]
    DIRECTION INPUT ;
    USE SIGNAL ;
    PORT
      LAYER M4 ;
        RECT  0 14.928 0.084 14.952 ;
    END
  END d[272]
  PIN d[273]
    DIRECTION INPUT ;
    USE SIGNAL ;
    PORT
      LAYER M4 ;
        RECT  0 15.024 0.084 15.048 ;
    END
  END d[273]
  PIN d[274]
    DIRECTION INPUT ;
    USE SIGNAL ;
    PORT
      LAYER M4 ;
        RECT  0 15.12 0.084 15.144 ;
    END
  END d[274]
  PIN d[275]
    DIRECTION INPUT ;
    USE SIGNAL ;
    PORT
      LAYER M4 ;
        RECT  0 15.216 0.084 15.24 ;
    END
  END d[275]
  PIN d[276]
    DIRECTION INPUT ;
    USE SIGNAL ;
    PORT
      LAYER M4 ;
        RECT  0 15.312 0.084 15.336 ;
    END
  END d[276]
  PIN d[277]
    DIRECTION INPUT ;
    USE SIGNAL ;
    PORT
      LAYER M4 ;
        RECT  0 15.408 0.084 15.432 ;
    END
  END d[277]
  PIN d[278]
    DIRECTION INPUT ;
    USE SIGNAL ;
    PORT
      LAYER M4 ;
        RECT  0 15.504 0.084 15.528 ;
    END
  END d[278]
  PIN d[279]
    DIRECTION INPUT ;
    USE SIGNAL ;
    PORT
      LAYER M4 ;
        RECT  0 15.6 0.084 15.624 ;
    END
  END d[279]
  PIN d[27]
    DIRECTION INPUT ;
    USE SIGNAL ;
    PORT
      LAYER M4 ;
        RECT  0 38.256 0.084 38.28 ;
    END
  END d[27]
  PIN d[280]
    DIRECTION INPUT ;
    USE SIGNAL ;
    PORT
      LAYER M4 ;
        RECT  0 15.696 0.084 15.72 ;
    END
  END d[280]
  PIN d[281]
    DIRECTION INPUT ;
    USE SIGNAL ;
    PORT
      LAYER M4 ;
        RECT  0 15.792 0.084 15.816 ;
    END
  END d[281]
  PIN d[282]
    DIRECTION INPUT ;
    USE SIGNAL ;
    PORT
      LAYER M4 ;
        RECT  0 15.888 0.084 15.912 ;
    END
  END d[282]
  PIN d[283]
    DIRECTION INPUT ;
    USE SIGNAL ;
    PORT
      LAYER M4 ;
        RECT  0 15.984 0.084 16.008 ;
    END
  END d[283]
  PIN d[284]
    DIRECTION INPUT ;
    USE SIGNAL ;
    PORT
      LAYER M4 ;
        RECT  0 16.08 0.084 16.104 ;
    END
  END d[284]
  PIN d[285]
    DIRECTION INPUT ;
    USE SIGNAL ;
    PORT
      LAYER M4 ;
        RECT  0 16.176 0.084 16.2 ;
    END
  END d[285]
  PIN d[286]
    DIRECTION INPUT ;
    USE SIGNAL ;
    PORT
      LAYER M4 ;
        RECT  0 16.272 0.084 16.296 ;
    END
  END d[286]
  PIN d[287]
    DIRECTION INPUT ;
    USE SIGNAL ;
    PORT
      LAYER M4 ;
        RECT  0 16.368 0.084 16.392 ;
    END
  END d[287]
  PIN d[288]
    DIRECTION INPUT ;
    USE SIGNAL ;
    PORT
      LAYER M4 ;
        RECT  0 54.864 0.084 54.888 ;
    END
  END d[288]
  PIN d[289]
    DIRECTION INPUT ;
    USE SIGNAL ;
    PORT
      LAYER M4 ;
        RECT  0 54.96 0.084 54.984 ;
    END
  END d[289]
  PIN d[28]
    DIRECTION INPUT ;
    USE SIGNAL ;
    PORT
      LAYER M4 ;
        RECT  0 38.352 0.084 38.376 ;
    END
  END d[28]
  PIN d[290]
    DIRECTION INPUT ;
    USE SIGNAL ;
    PORT
      LAYER M4 ;
        RECT  0 55.056 0.084 55.08 ;
    END
  END d[290]
  PIN d[291]
    DIRECTION INPUT ;
    USE SIGNAL ;
    PORT
      LAYER M4 ;
        RECT  0 55.152 0.084 55.176 ;
    END
  END d[291]
  PIN d[292]
    DIRECTION INPUT ;
    USE SIGNAL ;
    PORT
      LAYER M4 ;
        RECT  0 55.248 0.084 55.272 ;
    END
  END d[292]
  PIN d[293]
    DIRECTION INPUT ;
    USE SIGNAL ;
    PORT
      LAYER M4 ;
        RECT  0 55.344 0.084 55.368 ;
    END
  END d[293]
  PIN d[294]
    DIRECTION INPUT ;
    USE SIGNAL ;
    PORT
      LAYER M4 ;
        RECT  0 55.44 0.084 55.464 ;
    END
  END d[294]
  PIN d[295]
    DIRECTION INPUT ;
    USE SIGNAL ;
    PORT
      LAYER M4 ;
        RECT  0 55.536 0.084 55.56 ;
    END
  END d[295]
  PIN d[296]
    DIRECTION INPUT ;
    USE SIGNAL ;
    PORT
      LAYER M4 ;
        RECT  0 55.632 0.084 55.656 ;
    END
  END d[296]
  PIN d[297]
    DIRECTION INPUT ;
    USE SIGNAL ;
    PORT
      LAYER M4 ;
        RECT  0 55.728 0.084 55.752 ;
    END
  END d[297]
  PIN d[298]
    DIRECTION INPUT ;
    USE SIGNAL ;
    PORT
      LAYER M4 ;
        RECT  0 55.824 0.084 55.848 ;
    END
  END d[298]
  PIN d[299]
    DIRECTION INPUT ;
    USE SIGNAL ;
    PORT
      LAYER M4 ;
        RECT  0 55.92 0.084 55.944 ;
    END
  END d[299]
  PIN d[29]
    DIRECTION INPUT ;
    USE SIGNAL ;
    PORT
      LAYER M4 ;
        RECT  0 38.448 0.084 38.472 ;
    END
  END d[29]
  PIN d[2]
    DIRECTION INPUT ;
    USE SIGNAL ;
    PORT
      LAYER M4 ;
        RECT  0 35.856 0.084 35.88 ;
    END
  END d[2]
  PIN d[300]
    DIRECTION INPUT ;
    USE SIGNAL ;
    PORT
      LAYER M4 ;
        RECT  0 56.016 0.084 56.04 ;
    END
  END d[300]
  PIN d[301]
    DIRECTION INPUT ;
    USE SIGNAL ;
    PORT
      LAYER M4 ;
        RECT  0 56.112 0.084 56.136 ;
    END
  END d[301]
  PIN d[302]
    DIRECTION INPUT ;
    USE SIGNAL ;
    PORT
      LAYER M4 ;
        RECT  0 56.208 0.084 56.232 ;
    END
  END d[302]
  PIN d[303]
    DIRECTION INPUT ;
    USE SIGNAL ;
    PORT
      LAYER M4 ;
        RECT  0 56.304 0.084 56.328 ;
    END
  END d[303]
  PIN d[304]
    DIRECTION INPUT ;
    USE SIGNAL ;
    PORT
      LAYER M4 ;
        RECT  0 56.4 0.084 56.424 ;
    END
  END d[304]
  PIN d[305]
    DIRECTION INPUT ;
    USE SIGNAL ;
    PORT
      LAYER M4 ;
        RECT  0 56.496 0.084 56.52 ;
    END
  END d[305]
  PIN d[306]
    DIRECTION INPUT ;
    USE SIGNAL ;
    PORT
      LAYER M4 ;
        RECT  0 56.592 0.084 56.616 ;
    END
  END d[306]
  PIN d[307]
    DIRECTION INPUT ;
    USE SIGNAL ;
    PORT
      LAYER M4 ;
        RECT  0 56.688 0.084 56.712 ;
    END
  END d[307]
  PIN d[308]
    DIRECTION INPUT ;
    USE SIGNAL ;
    PORT
      LAYER M4 ;
        RECT  0 56.784 0.084 56.808 ;
    END
  END d[308]
  PIN d[309]
    DIRECTION INPUT ;
    USE SIGNAL ;
    PORT
      LAYER M4 ;
        RECT  0 56.88 0.084 56.904 ;
    END
  END d[309]
  PIN d[30]
    DIRECTION INPUT ;
    USE SIGNAL ;
    PORT
      LAYER M4 ;
        RECT  0 38.544 0.084 38.568 ;
    END
  END d[30]
  PIN d[310]
    DIRECTION INPUT ;
    USE SIGNAL ;
    PORT
      LAYER M4 ;
        RECT  0 56.976 0.084 57 ;
    END
  END d[310]
  PIN d[311]
    DIRECTION INPUT ;
    USE SIGNAL ;
    PORT
      LAYER M4 ;
        RECT  0 57.072 0.084 57.096 ;
    END
  END d[311]
  PIN d[312]
    DIRECTION INPUT ;
    USE SIGNAL ;
    PORT
      LAYER M4 ;
        RECT  0 57.168 0.084 57.192 ;
    END
  END d[312]
  PIN d[313]
    DIRECTION INPUT ;
    USE SIGNAL ;
    PORT
      LAYER M4 ;
        RECT  0 57.264 0.084 57.288 ;
    END
  END d[313]
  PIN d[314]
    DIRECTION INPUT ;
    USE SIGNAL ;
    PORT
      LAYER M4 ;
        RECT  0 57.36 0.084 57.384 ;
    END
  END d[314]
  PIN d[315]
    DIRECTION INPUT ;
    USE SIGNAL ;
    PORT
      LAYER M4 ;
        RECT  0 57.456 0.084 57.48 ;
    END
  END d[315]
  PIN d[316]
    DIRECTION INPUT ;
    USE SIGNAL ;
    PORT
      LAYER M4 ;
        RECT  0 57.552 0.084 57.576 ;
    END
  END d[316]
  PIN d[317]
    DIRECTION INPUT ;
    USE SIGNAL ;
    PORT
      LAYER M4 ;
        RECT  0 57.648 0.084 57.672 ;
    END
  END d[317]
  PIN d[318]
    DIRECTION INPUT ;
    USE SIGNAL ;
    PORT
      LAYER M4 ;
        RECT  0 57.744 0.084 57.768 ;
    END
  END d[318]
  PIN d[319]
    DIRECTION INPUT ;
    USE SIGNAL ;
    PORT
      LAYER M4 ;
        RECT  0 57.84 0.084 57.864 ;
    END
  END d[319]
  PIN d[31]
    DIRECTION INPUT ;
    USE SIGNAL ;
    PORT
      LAYER M4 ;
        RECT  0 38.64 0.084 38.664 ;
    END
  END d[31]
  PIN d[320]
    DIRECTION INPUT ;
    USE SIGNAL ;
    PORT
      LAYER M4 ;
        RECT  0 48.72 0.084 48.744 ;
    END
  END d[320]
  PIN d[321]
    DIRECTION INPUT ;
    USE SIGNAL ;
    PORT
      LAYER M4 ;
        RECT  0 48.816 0.084 48.84 ;
    END
  END d[321]
  PIN d[322]
    DIRECTION INPUT ;
    USE SIGNAL ;
    PORT
      LAYER M4 ;
        RECT  0 48.912 0.084 48.936 ;
    END
  END d[322]
  PIN d[323]
    DIRECTION INPUT ;
    USE SIGNAL ;
    PORT
      LAYER M4 ;
        RECT  0 49.008 0.084 49.032 ;
    END
  END d[323]
  PIN d[324]
    DIRECTION INPUT ;
    USE SIGNAL ;
    PORT
      LAYER M4 ;
        RECT  0 49.104 0.084 49.128 ;
    END
  END d[324]
  PIN d[325]
    DIRECTION INPUT ;
    USE SIGNAL ;
    PORT
      LAYER M4 ;
        RECT  0 49.2 0.084 49.224 ;
    END
  END d[325]
  PIN d[326]
    DIRECTION INPUT ;
    USE SIGNAL ;
    PORT
      LAYER M4 ;
        RECT  0 49.296 0.084 49.32 ;
    END
  END d[326]
  PIN d[327]
    DIRECTION INPUT ;
    USE SIGNAL ;
    PORT
      LAYER M4 ;
        RECT  0 49.392 0.084 49.416 ;
    END
  END d[327]
  PIN d[328]
    DIRECTION INPUT ;
    USE SIGNAL ;
    PORT
      LAYER M4 ;
        RECT  0 49.488 0.084 49.512 ;
    END
  END d[328]
  PIN d[329]
    DIRECTION INPUT ;
    USE SIGNAL ;
    PORT
      LAYER M4 ;
        RECT  0 49.584 0.084 49.608 ;
    END
  END d[329]
  PIN d[32]
    DIRECTION INPUT ;
    USE SIGNAL ;
    PORT
      LAYER M4 ;
        RECT  0 32.592 0.084 32.616 ;
    END
  END d[32]
  PIN d[330]
    DIRECTION INPUT ;
    USE SIGNAL ;
    PORT
      LAYER M4 ;
        RECT  0 49.68 0.084 49.704 ;
    END
  END d[330]
  PIN d[331]
    DIRECTION INPUT ;
    USE SIGNAL ;
    PORT
      LAYER M4 ;
        RECT  0 49.776 0.084 49.8 ;
    END
  END d[331]
  PIN d[332]
    DIRECTION INPUT ;
    USE SIGNAL ;
    PORT
      LAYER M4 ;
        RECT  0 49.872 0.084 49.896 ;
    END
  END d[332]
  PIN d[333]
    DIRECTION INPUT ;
    USE SIGNAL ;
    PORT
      LAYER M4 ;
        RECT  0 49.968 0.084 49.992 ;
    END
  END d[333]
  PIN d[334]
    DIRECTION INPUT ;
    USE SIGNAL ;
    PORT
      LAYER M4 ;
        RECT  0 50.064 0.084 50.088 ;
    END
  END d[334]
  PIN d[335]
    DIRECTION INPUT ;
    USE SIGNAL ;
    PORT
      LAYER M4 ;
        RECT  0 50.16 0.084 50.184 ;
    END
  END d[335]
  PIN d[336]
    DIRECTION INPUT ;
    USE SIGNAL ;
    PORT
      LAYER M4 ;
        RECT  0 50.256 0.084 50.28 ;
    END
  END d[336]
  PIN d[337]
    DIRECTION INPUT ;
    USE SIGNAL ;
    PORT
      LAYER M4 ;
        RECT  0 50.352 0.084 50.376 ;
    END
  END d[337]
  PIN d[338]
    DIRECTION INPUT ;
    USE SIGNAL ;
    PORT
      LAYER M4 ;
        RECT  0 50.448 0.084 50.472 ;
    END
  END d[338]
  PIN d[339]
    DIRECTION INPUT ;
    USE SIGNAL ;
    PORT
      LAYER M4 ;
        RECT  0 50.544 0.084 50.568 ;
    END
  END d[339]
  PIN d[33]
    DIRECTION INPUT ;
    USE SIGNAL ;
    PORT
      LAYER M4 ;
        RECT  0 32.688 0.084 32.712 ;
    END
  END d[33]
  PIN d[340]
    DIRECTION INPUT ;
    USE SIGNAL ;
    PORT
      LAYER M4 ;
        RECT  0 50.64 0.084 50.664 ;
    END
  END d[340]
  PIN d[341]
    DIRECTION INPUT ;
    USE SIGNAL ;
    PORT
      LAYER M4 ;
        RECT  0 50.736 0.084 50.76 ;
    END
  END d[341]
  PIN d[342]
    DIRECTION INPUT ;
    USE SIGNAL ;
    PORT
      LAYER M4 ;
        RECT  0 50.832 0.084 50.856 ;
    END
  END d[342]
  PIN d[343]
    DIRECTION INPUT ;
    USE SIGNAL ;
    PORT
      LAYER M4 ;
        RECT  0 50.928 0.084 50.952 ;
    END
  END d[343]
  PIN d[344]
    DIRECTION INPUT ;
    USE SIGNAL ;
    PORT
      LAYER M4 ;
        RECT  0 51.024 0.084 51.048 ;
    END
  END d[344]
  PIN d[345]
    DIRECTION INPUT ;
    USE SIGNAL ;
    PORT
      LAYER M4 ;
        RECT  0 51.12 0.084 51.144 ;
    END
  END d[345]
  PIN d[346]
    DIRECTION INPUT ;
    USE SIGNAL ;
    PORT
      LAYER M4 ;
        RECT  0 51.216 0.084 51.24 ;
    END
  END d[346]
  PIN d[347]
    DIRECTION INPUT ;
    USE SIGNAL ;
    PORT
      LAYER M4 ;
        RECT  0 51.312 0.084 51.336 ;
    END
  END d[347]
  PIN d[348]
    DIRECTION INPUT ;
    USE SIGNAL ;
    PORT
      LAYER M4 ;
        RECT  0 51.408 0.084 51.432 ;
    END
  END d[348]
  PIN d[349]
    DIRECTION INPUT ;
    USE SIGNAL ;
    PORT
      LAYER M4 ;
        RECT  0 51.504 0.084 51.528 ;
    END
  END d[349]
  PIN d[34]
    DIRECTION INPUT ;
    USE SIGNAL ;
    PORT
      LAYER M4 ;
        RECT  0 32.784 0.084 32.808 ;
    END
  END d[34]
  PIN d[350]
    DIRECTION INPUT ;
    USE SIGNAL ;
    PORT
      LAYER M4 ;
        RECT  0 51.6 0.084 51.624 ;
    END
  END d[350]
  PIN d[351]
    DIRECTION INPUT ;
    USE SIGNAL ;
    PORT
      LAYER M4 ;
        RECT  0 51.696 0.084 51.72 ;
    END
  END d[351]
  PIN d[352]
    DIRECTION INPUT ;
    USE SIGNAL ;
    PORT
      LAYER M4 ;
        RECT  0 22.608 0.084 22.632 ;
    END
  END d[352]
  PIN d[353]
    DIRECTION INPUT ;
    USE SIGNAL ;
    PORT
      LAYER M4 ;
        RECT  0 22.704 0.084 22.728 ;
    END
  END d[353]
  PIN d[354]
    DIRECTION INPUT ;
    USE SIGNAL ;
    PORT
      LAYER M4 ;
        RECT  0 22.8 0.084 22.824 ;
    END
  END d[354]
  PIN d[355]
    DIRECTION INPUT ;
    USE SIGNAL ;
    PORT
      LAYER M4 ;
        RECT  0 22.896 0.084 22.92 ;
    END
  END d[355]
  PIN d[356]
    DIRECTION INPUT ;
    USE SIGNAL ;
    PORT
      LAYER M4 ;
        RECT  0 22.992 0.084 23.016 ;
    END
  END d[356]
  PIN d[357]
    DIRECTION INPUT ;
    USE SIGNAL ;
    PORT
      LAYER M4 ;
        RECT  0 23.088 0.084 23.112 ;
    END
  END d[357]
  PIN d[358]
    DIRECTION INPUT ;
    USE SIGNAL ;
    PORT
      LAYER M4 ;
        RECT  0 23.184 0.084 23.208 ;
    END
  END d[358]
  PIN d[359]
    DIRECTION INPUT ;
    USE SIGNAL ;
    PORT
      LAYER M4 ;
        RECT  0 23.28 0.084 23.304 ;
    END
  END d[359]
  PIN d[35]
    DIRECTION INPUT ;
    USE SIGNAL ;
    PORT
      LAYER M4 ;
        RECT  0 32.88 0.084 32.904 ;
    END
  END d[35]
  PIN d[360]
    DIRECTION INPUT ;
    USE SIGNAL ;
    PORT
      LAYER M4 ;
        RECT  0 23.376 0.084 23.4 ;
    END
  END d[360]
  PIN d[361]
    DIRECTION INPUT ;
    USE SIGNAL ;
    PORT
      LAYER M4 ;
        RECT  0 23.472 0.084 23.496 ;
    END
  END d[361]
  PIN d[362]
    DIRECTION INPUT ;
    USE SIGNAL ;
    PORT
      LAYER M4 ;
        RECT  0 23.568 0.084 23.592 ;
    END
  END d[362]
  PIN d[363]
    DIRECTION INPUT ;
    USE SIGNAL ;
    PORT
      LAYER M4 ;
        RECT  0 23.664 0.084 23.688 ;
    END
  END d[363]
  PIN d[364]
    DIRECTION INPUT ;
    USE SIGNAL ;
    PORT
      LAYER M4 ;
        RECT  0 23.76 0.084 23.784 ;
    END
  END d[364]
  PIN d[365]
    DIRECTION INPUT ;
    USE SIGNAL ;
    PORT
      LAYER M4 ;
        RECT  0 23.856 0.084 23.88 ;
    END
  END d[365]
  PIN d[366]
    DIRECTION INPUT ;
    USE SIGNAL ;
    PORT
      LAYER M4 ;
        RECT  0 23.952 0.084 23.976 ;
    END
  END d[366]
  PIN d[367]
    DIRECTION INPUT ;
    USE SIGNAL ;
    PORT
      LAYER M4 ;
        RECT  0 24.048 0.084 24.072 ;
    END
  END d[367]
  PIN d[368]
    DIRECTION INPUT ;
    USE SIGNAL ;
    PORT
      LAYER M4 ;
        RECT  0 24.144 0.084 24.168 ;
    END
  END d[368]
  PIN d[369]
    DIRECTION INPUT ;
    USE SIGNAL ;
    PORT
      LAYER M4 ;
        RECT  0 24.24 0.084 24.264 ;
    END
  END d[369]
  PIN d[36]
    DIRECTION INPUT ;
    USE SIGNAL ;
    PORT
      LAYER M4 ;
        RECT  0 32.976 0.084 33 ;
    END
  END d[36]
  PIN d[370]
    DIRECTION INPUT ;
    USE SIGNAL ;
    PORT
      LAYER M4 ;
        RECT  0 24.336 0.084 24.36 ;
    END
  END d[370]
  PIN d[371]
    DIRECTION INPUT ;
    USE SIGNAL ;
    PORT
      LAYER M4 ;
        RECT  0 24.432 0.084 24.456 ;
    END
  END d[371]
  PIN d[372]
    DIRECTION INPUT ;
    USE SIGNAL ;
    PORT
      LAYER M4 ;
        RECT  0 24.528 0.084 24.552 ;
    END
  END d[372]
  PIN d[373]
    DIRECTION INPUT ;
    USE SIGNAL ;
    PORT
      LAYER M4 ;
        RECT  0 24.624 0.084 24.648 ;
    END
  END d[373]
  PIN d[374]
    DIRECTION INPUT ;
    USE SIGNAL ;
    PORT
      LAYER M4 ;
        RECT  0 24.72 0.084 24.744 ;
    END
  END d[374]
  PIN d[375]
    DIRECTION INPUT ;
    USE SIGNAL ;
    PORT
      LAYER M4 ;
        RECT  0 24.816 0.084 24.84 ;
    END
  END d[375]
  PIN d[376]
    DIRECTION INPUT ;
    USE SIGNAL ;
    PORT
      LAYER M4 ;
        RECT  0 24.912 0.084 24.936 ;
    END
  END d[376]
  PIN d[377]
    DIRECTION INPUT ;
    USE SIGNAL ;
    PORT
      LAYER M4 ;
        RECT  0 25.008 0.084 25.032 ;
    END
  END d[377]
  PIN d[378]
    DIRECTION INPUT ;
    USE SIGNAL ;
    PORT
      LAYER M4 ;
        RECT  0 25.104 0.084 25.128 ;
    END
  END d[378]
  PIN d[379]
    DIRECTION INPUT ;
    USE SIGNAL ;
    PORT
      LAYER M4 ;
        RECT  0 25.2 0.084 25.224 ;
    END
  END d[379]
  PIN d[37]
    DIRECTION INPUT ;
    USE SIGNAL ;
    PORT
      LAYER M4 ;
        RECT  0 33.072 0.084 33.096 ;
    END
  END d[37]
  PIN d[380]
    DIRECTION INPUT ;
    USE SIGNAL ;
    PORT
      LAYER M4 ;
        RECT  0 25.296 0.084 25.32 ;
    END
  END d[380]
  PIN d[381]
    DIRECTION INPUT ;
    USE SIGNAL ;
    PORT
      LAYER M4 ;
        RECT  0 25.392 0.084 25.416 ;
    END
  END d[381]
  PIN d[382]
    DIRECTION INPUT ;
    USE SIGNAL ;
    PORT
      LAYER M4 ;
        RECT  0 25.488 0.084 25.512 ;
    END
  END d[382]
  PIN d[383]
    DIRECTION INPUT ;
    USE SIGNAL ;
    PORT
      LAYER M4 ;
        RECT  0 25.584 0.084 25.608 ;
    END
  END d[383]
  PIN d[384]
    DIRECTION INPUT ;
    USE SIGNAL ;
    PORT
      LAYER M4 ;
        RECT  0 51.792 0.084 51.816 ;
    END
  END d[384]
  PIN d[385]
    DIRECTION INPUT ;
    USE SIGNAL ;
    PORT
      LAYER M4 ;
        RECT  0 51.888 0.084 51.912 ;
    END
  END d[385]
  PIN d[386]
    DIRECTION INPUT ;
    USE SIGNAL ;
    PORT
      LAYER M4 ;
        RECT  0 51.984 0.084 52.008 ;
    END
  END d[386]
  PIN d[387]
    DIRECTION INPUT ;
    USE SIGNAL ;
    PORT
      LAYER M4 ;
        RECT  0 52.08 0.084 52.104 ;
    END
  END d[387]
  PIN d[388]
    DIRECTION INPUT ;
    USE SIGNAL ;
    PORT
      LAYER M4 ;
        RECT  0 52.176 0.084 52.2 ;
    END
  END d[388]
  PIN d[389]
    DIRECTION INPUT ;
    USE SIGNAL ;
    PORT
      LAYER M4 ;
        RECT  0 52.272 0.084 52.296 ;
    END
  END d[389]
  PIN d[38]
    DIRECTION INPUT ;
    USE SIGNAL ;
    PORT
      LAYER M4 ;
        RECT  0 33.168 0.084 33.192 ;
    END
  END d[38]
  PIN d[390]
    DIRECTION INPUT ;
    USE SIGNAL ;
    PORT
      LAYER M4 ;
        RECT  0 52.368 0.084 52.392 ;
    END
  END d[390]
  PIN d[391]
    DIRECTION INPUT ;
    USE SIGNAL ;
    PORT
      LAYER M4 ;
        RECT  0 52.464 0.084 52.488 ;
    END
  END d[391]
  PIN d[392]
    DIRECTION INPUT ;
    USE SIGNAL ;
    PORT
      LAYER M4 ;
        RECT  0 52.56 0.084 52.584 ;
    END
  END d[392]
  PIN d[393]
    DIRECTION INPUT ;
    USE SIGNAL ;
    PORT
      LAYER M4 ;
        RECT  0 52.656 0.084 52.68 ;
    END
  END d[393]
  PIN d[394]
    DIRECTION INPUT ;
    USE SIGNAL ;
    PORT
      LAYER M4 ;
        RECT  0 52.752 0.084 52.776 ;
    END
  END d[394]
  PIN d[395]
    DIRECTION INPUT ;
    USE SIGNAL ;
    PORT
      LAYER M4 ;
        RECT  0 52.848 0.084 52.872 ;
    END
  END d[395]
  PIN d[396]
    DIRECTION INPUT ;
    USE SIGNAL ;
    PORT
      LAYER M4 ;
        RECT  0 52.944 0.084 52.968 ;
    END
  END d[396]
  PIN d[397]
    DIRECTION INPUT ;
    USE SIGNAL ;
    PORT
      LAYER M4 ;
        RECT  0 53.04 0.084 53.064 ;
    END
  END d[397]
  PIN d[398]
    DIRECTION INPUT ;
    USE SIGNAL ;
    PORT
      LAYER M4 ;
        RECT  0 53.136 0.084 53.16 ;
    END
  END d[398]
  PIN d[399]
    DIRECTION INPUT ;
    USE SIGNAL ;
    PORT
      LAYER M4 ;
        RECT  0 53.232 0.084 53.256 ;
    END
  END d[399]
  PIN d[39]
    DIRECTION INPUT ;
    USE SIGNAL ;
    PORT
      LAYER M4 ;
        RECT  0 33.264 0.084 33.288 ;
    END
  END d[39]
  PIN d[3]
    DIRECTION INPUT ;
    USE SIGNAL ;
    PORT
      LAYER M4 ;
        RECT  0 35.952 0.084 35.976 ;
    END
  END d[3]
  PIN d[400]
    DIRECTION INPUT ;
    USE SIGNAL ;
    PORT
      LAYER M4 ;
        RECT  0 53.328 0.084 53.352 ;
    END
  END d[400]
  PIN d[401]
    DIRECTION INPUT ;
    USE SIGNAL ;
    PORT
      LAYER M4 ;
        RECT  0 53.424 0.084 53.448 ;
    END
  END d[401]
  PIN d[402]
    DIRECTION INPUT ;
    USE SIGNAL ;
    PORT
      LAYER M4 ;
        RECT  0 53.52 0.084 53.544 ;
    END
  END d[402]
  PIN d[403]
    DIRECTION INPUT ;
    USE SIGNAL ;
    PORT
      LAYER M4 ;
        RECT  0 53.616 0.084 53.64 ;
    END
  END d[403]
  PIN d[404]
    DIRECTION INPUT ;
    USE SIGNAL ;
    PORT
      LAYER M4 ;
        RECT  0 53.712 0.084 53.736 ;
    END
  END d[404]
  PIN d[405]
    DIRECTION INPUT ;
    USE SIGNAL ;
    PORT
      LAYER M4 ;
        RECT  0 53.808 0.084 53.832 ;
    END
  END d[405]
  PIN d[406]
    DIRECTION INPUT ;
    USE SIGNAL ;
    PORT
      LAYER M4 ;
        RECT  0 53.904 0.084 53.928 ;
    END
  END d[406]
  PIN d[407]
    DIRECTION INPUT ;
    USE SIGNAL ;
    PORT
      LAYER M4 ;
        RECT  0 54 0.084 54.024 ;
    END
  END d[407]
  PIN d[408]
    DIRECTION INPUT ;
    USE SIGNAL ;
    PORT
      LAYER M4 ;
        RECT  0 54.096 0.084 54.12 ;
    END
  END d[408]
  PIN d[409]
    DIRECTION INPUT ;
    USE SIGNAL ;
    PORT
      LAYER M4 ;
        RECT  0 54.192 0.084 54.216 ;
    END
  END d[409]
  PIN d[40]
    DIRECTION INPUT ;
    USE SIGNAL ;
    PORT
      LAYER M4 ;
        RECT  0 33.36 0.084 33.384 ;
    END
  END d[40]
  PIN d[410]
    DIRECTION INPUT ;
    USE SIGNAL ;
    PORT
      LAYER M4 ;
        RECT  0 54.288 0.084 54.312 ;
    END
  END d[410]
  PIN d[411]
    DIRECTION INPUT ;
    USE SIGNAL ;
    PORT
      LAYER M4 ;
        RECT  0 54.384 0.084 54.408 ;
    END
  END d[411]
  PIN d[412]
    DIRECTION INPUT ;
    USE SIGNAL ;
    PORT
      LAYER M4 ;
        RECT  0 54.48 0.084 54.504 ;
    END
  END d[412]
  PIN d[413]
    DIRECTION INPUT ;
    USE SIGNAL ;
    PORT
      LAYER M4 ;
        RECT  0 54.576 0.084 54.6 ;
    END
  END d[413]
  PIN d[414]
    DIRECTION INPUT ;
    USE SIGNAL ;
    PORT
      LAYER M4 ;
        RECT  0 54.672 0.084 54.696 ;
    END
  END d[414]
  PIN d[415]
    DIRECTION INPUT ;
    USE SIGNAL ;
    PORT
      LAYER M4 ;
        RECT  0 54.768 0.084 54.792 ;
    END
  END d[415]
  PIN d[416]
    DIRECTION INPUT ;
    USE SIGNAL ;
    PORT
      LAYER M4 ;
        RECT  0 19.536 0.084 19.56 ;
    END
  END d[416]
  PIN d[417]
    DIRECTION INPUT ;
    USE SIGNAL ;
    PORT
      LAYER M4 ;
        RECT  0 19.632 0.084 19.656 ;
    END
  END d[417]
  PIN d[418]
    DIRECTION INPUT ;
    USE SIGNAL ;
    PORT
      LAYER M4 ;
        RECT  0 19.728 0.084 19.752 ;
    END
  END d[418]
  PIN d[419]
    DIRECTION INPUT ;
    USE SIGNAL ;
    PORT
      LAYER M4 ;
        RECT  0 19.824 0.084 19.848 ;
    END
  END d[419]
  PIN d[41]
    DIRECTION INPUT ;
    USE SIGNAL ;
    PORT
      LAYER M4 ;
        RECT  0 33.456 0.084 33.48 ;
    END
  END d[41]
  PIN d[420]
    DIRECTION INPUT ;
    USE SIGNAL ;
    PORT
      LAYER M4 ;
        RECT  0 19.92 0.084 19.944 ;
    END
  END d[420]
  PIN d[421]
    DIRECTION INPUT ;
    USE SIGNAL ;
    PORT
      LAYER M4 ;
        RECT  0 20.016 0.084 20.04 ;
    END
  END d[421]
  PIN d[422]
    DIRECTION INPUT ;
    USE SIGNAL ;
    PORT
      LAYER M4 ;
        RECT  0 20.112 0.084 20.136 ;
    END
  END d[422]
  PIN d[423]
    DIRECTION INPUT ;
    USE SIGNAL ;
    PORT
      LAYER M4 ;
        RECT  0 20.208 0.084 20.232 ;
    END
  END d[423]
  PIN d[424]
    DIRECTION INPUT ;
    USE SIGNAL ;
    PORT
      LAYER M4 ;
        RECT  0 20.304 0.084 20.328 ;
    END
  END d[424]
  PIN d[425]
    DIRECTION INPUT ;
    USE SIGNAL ;
    PORT
      LAYER M4 ;
        RECT  0 20.4 0.084 20.424 ;
    END
  END d[425]
  PIN d[426]
    DIRECTION INPUT ;
    USE SIGNAL ;
    PORT
      LAYER M4 ;
        RECT  0 20.496 0.084 20.52 ;
    END
  END d[426]
  PIN d[427]
    DIRECTION INPUT ;
    USE SIGNAL ;
    PORT
      LAYER M4 ;
        RECT  0 20.592 0.084 20.616 ;
    END
  END d[427]
  PIN d[428]
    DIRECTION INPUT ;
    USE SIGNAL ;
    PORT
      LAYER M4 ;
        RECT  0 20.688 0.084 20.712 ;
    END
  END d[428]
  PIN d[429]
    DIRECTION INPUT ;
    USE SIGNAL ;
    PORT
      LAYER M4 ;
        RECT  0 20.784 0.084 20.808 ;
    END
  END d[429]
  PIN d[42]
    DIRECTION INPUT ;
    USE SIGNAL ;
    PORT
      LAYER M4 ;
        RECT  0 33.552 0.084 33.576 ;
    END
  END d[42]
  PIN d[430]
    DIRECTION INPUT ;
    USE SIGNAL ;
    PORT
      LAYER M4 ;
        RECT  0 20.88 0.084 20.904 ;
    END
  END d[430]
  PIN d[431]
    DIRECTION INPUT ;
    USE SIGNAL ;
    PORT
      LAYER M4 ;
        RECT  0 20.976 0.084 21 ;
    END
  END d[431]
  PIN d[432]
    DIRECTION INPUT ;
    USE SIGNAL ;
    PORT
      LAYER M4 ;
        RECT  0 21.072 0.084 21.096 ;
    END
  END d[432]
  PIN d[433]
    DIRECTION INPUT ;
    USE SIGNAL ;
    PORT
      LAYER M4 ;
        RECT  0 21.168 0.084 21.192 ;
    END
  END d[433]
  PIN d[434]
    DIRECTION INPUT ;
    USE SIGNAL ;
    PORT
      LAYER M4 ;
        RECT  0 21.264 0.084 21.288 ;
    END
  END d[434]
  PIN d[435]
    DIRECTION INPUT ;
    USE SIGNAL ;
    PORT
      LAYER M4 ;
        RECT  0 21.36 0.084 21.384 ;
    END
  END d[435]
  PIN d[436]
    DIRECTION INPUT ;
    USE SIGNAL ;
    PORT
      LAYER M4 ;
        RECT  0 21.456 0.084 21.48 ;
    END
  END d[436]
  PIN d[437]
    DIRECTION INPUT ;
    USE SIGNAL ;
    PORT
      LAYER M4 ;
        RECT  0 21.552 0.084 21.576 ;
    END
  END d[437]
  PIN d[438]
    DIRECTION INPUT ;
    USE SIGNAL ;
    PORT
      LAYER M4 ;
        RECT  0 21.648 0.084 21.672 ;
    END
  END d[438]
  PIN d[439]
    DIRECTION INPUT ;
    USE SIGNAL ;
    PORT
      LAYER M4 ;
        RECT  0 21.744 0.084 21.768 ;
    END
  END d[439]
  PIN d[43]
    DIRECTION INPUT ;
    USE SIGNAL ;
    PORT
      LAYER M4 ;
        RECT  0 33.648 0.084 33.672 ;
    END
  END d[43]
  PIN d[440]
    DIRECTION INPUT ;
    USE SIGNAL ;
    PORT
      LAYER M4 ;
        RECT  0 21.84 0.084 21.864 ;
    END
  END d[440]
  PIN d[441]
    DIRECTION INPUT ;
    USE SIGNAL ;
    PORT
      LAYER M4 ;
        RECT  0 21.936 0.084 21.96 ;
    END
  END d[441]
  PIN d[442]
    DIRECTION INPUT ;
    USE SIGNAL ;
    PORT
      LAYER M4 ;
        RECT  0 22.032 0.084 22.056 ;
    END
  END d[442]
  PIN d[443]
    DIRECTION INPUT ;
    USE SIGNAL ;
    PORT
      LAYER M4 ;
        RECT  0 22.128 0.084 22.152 ;
    END
  END d[443]
  PIN d[444]
    DIRECTION INPUT ;
    USE SIGNAL ;
    PORT
      LAYER M4 ;
        RECT  0 22.224 0.084 22.248 ;
    END
  END d[444]
  PIN d[445]
    DIRECTION INPUT ;
    USE SIGNAL ;
    PORT
      LAYER M4 ;
        RECT  0 22.32 0.084 22.344 ;
    END
  END d[445]
  PIN d[446]
    DIRECTION INPUT ;
    USE SIGNAL ;
    PORT
      LAYER M4 ;
        RECT  0 22.416 0.084 22.44 ;
    END
  END d[446]
  PIN d[447]
    DIRECTION INPUT ;
    USE SIGNAL ;
    PORT
      LAYER M4 ;
        RECT  0 22.512 0.084 22.536 ;
    END
  END d[447]
  PIN d[448]
    DIRECTION INPUT ;
    USE SIGNAL ;
    PORT
      LAYER M4 ;
        RECT  0 7.248 0.084 7.272 ;
    END
  END d[448]
  PIN d[449]
    DIRECTION INPUT ;
    USE SIGNAL ;
    PORT
      LAYER M4 ;
        RECT  0 7.344 0.084 7.368 ;
    END
  END d[449]
  PIN d[44]
    DIRECTION INPUT ;
    USE SIGNAL ;
    PORT
      LAYER M4 ;
        RECT  0 33.744 0.084 33.768 ;
    END
  END d[44]
  PIN d[450]
    DIRECTION INPUT ;
    USE SIGNAL ;
    PORT
      LAYER M4 ;
        RECT  0 7.44 0.084 7.464 ;
    END
  END d[450]
  PIN d[451]
    DIRECTION INPUT ;
    USE SIGNAL ;
    PORT
      LAYER M4 ;
        RECT  0 7.536 0.084 7.56 ;
    END
  END d[451]
  PIN d[452]
    DIRECTION INPUT ;
    USE SIGNAL ;
    PORT
      LAYER M4 ;
        RECT  0 7.632 0.084 7.656 ;
    END
  END d[452]
  PIN d[453]
    DIRECTION INPUT ;
    USE SIGNAL ;
    PORT
      LAYER M4 ;
        RECT  0 7.728 0.084 7.752 ;
    END
  END d[453]
  PIN d[454]
    DIRECTION INPUT ;
    USE SIGNAL ;
    PORT
      LAYER M4 ;
        RECT  0 7.824 0.084 7.848 ;
    END
  END d[454]
  PIN d[455]
    DIRECTION INPUT ;
    USE SIGNAL ;
    PORT
      LAYER M4 ;
        RECT  0 7.92 0.084 7.944 ;
    END
  END d[455]
  PIN d[456]
    DIRECTION INPUT ;
    USE SIGNAL ;
    PORT
      LAYER M4 ;
        RECT  0 8.016 0.084 8.04 ;
    END
  END d[456]
  PIN d[457]
    DIRECTION INPUT ;
    USE SIGNAL ;
    PORT
      LAYER M4 ;
        RECT  0 8.112 0.084 8.136 ;
    END
  END d[457]
  PIN d[458]
    DIRECTION INPUT ;
    USE SIGNAL ;
    PORT
      LAYER M4 ;
        RECT  0 8.208 0.084 8.232 ;
    END
  END d[458]
  PIN d[459]
    DIRECTION INPUT ;
    USE SIGNAL ;
    PORT
      LAYER M4 ;
        RECT  0 8.304 0.084 8.328 ;
    END
  END d[459]
  PIN d[45]
    DIRECTION INPUT ;
    USE SIGNAL ;
    PORT
      LAYER M4 ;
        RECT  0 33.84 0.084 33.864 ;
    END
  END d[45]
  PIN d[460]
    DIRECTION INPUT ;
    USE SIGNAL ;
    PORT
      LAYER M4 ;
        RECT  0 8.4 0.084 8.424 ;
    END
  END d[460]
  PIN d[461]
    DIRECTION INPUT ;
    USE SIGNAL ;
    PORT
      LAYER M4 ;
        RECT  0 8.496 0.084 8.52 ;
    END
  END d[461]
  PIN d[462]
    DIRECTION INPUT ;
    USE SIGNAL ;
    PORT
      LAYER M4 ;
        RECT  0 8.592 0.084 8.616 ;
    END
  END d[462]
  PIN d[463]
    DIRECTION INPUT ;
    USE SIGNAL ;
    PORT
      LAYER M4 ;
        RECT  0 8.688 0.084 8.712 ;
    END
  END d[463]
  PIN d[464]
    DIRECTION INPUT ;
    USE SIGNAL ;
    PORT
      LAYER M4 ;
        RECT  0 8.784 0.084 8.808 ;
    END
  END d[464]
  PIN d[465]
    DIRECTION INPUT ;
    USE SIGNAL ;
    PORT
      LAYER M4 ;
        RECT  0 8.88 0.084 8.904 ;
    END
  END d[465]
  PIN d[466]
    DIRECTION INPUT ;
    USE SIGNAL ;
    PORT
      LAYER M4 ;
        RECT  0 8.976 0.084 9 ;
    END
  END d[466]
  PIN d[467]
    DIRECTION INPUT ;
    USE SIGNAL ;
    PORT
      LAYER M4 ;
        RECT  0 9.072 0.084 9.096 ;
    END
  END d[467]
  PIN d[468]
    DIRECTION INPUT ;
    USE SIGNAL ;
    PORT
      LAYER M4 ;
        RECT  0 9.168 0.084 9.192 ;
    END
  END d[468]
  PIN d[469]
    DIRECTION INPUT ;
    USE SIGNAL ;
    PORT
      LAYER M4 ;
        RECT  0 9.264 0.084 9.288 ;
    END
  END d[469]
  PIN d[46]
    DIRECTION INPUT ;
    USE SIGNAL ;
    PORT
      LAYER M4 ;
        RECT  0 33.936 0.084 33.96 ;
    END
  END d[46]
  PIN d[470]
    DIRECTION INPUT ;
    USE SIGNAL ;
    PORT
      LAYER M4 ;
        RECT  0 9.36 0.084 9.384 ;
    END
  END d[470]
  PIN d[471]
    DIRECTION INPUT ;
    USE SIGNAL ;
    PORT
      LAYER M4 ;
        RECT  0 9.456 0.084 9.48 ;
    END
  END d[471]
  PIN d[472]
    DIRECTION INPUT ;
    USE SIGNAL ;
    PORT
      LAYER M4 ;
        RECT  0 9.552 0.084 9.576 ;
    END
  END d[472]
  PIN d[473]
    DIRECTION INPUT ;
    USE SIGNAL ;
    PORT
      LAYER M4 ;
        RECT  0 9.648 0.084 9.672 ;
    END
  END d[473]
  PIN d[474]
    DIRECTION INPUT ;
    USE SIGNAL ;
    PORT
      LAYER M4 ;
        RECT  0 9.744 0.084 9.768 ;
    END
  END d[474]
  PIN d[475]
    DIRECTION INPUT ;
    USE SIGNAL ;
    PORT
      LAYER M4 ;
        RECT  0 9.84 0.084 9.864 ;
    END
  END d[475]
  PIN d[476]
    DIRECTION INPUT ;
    USE SIGNAL ;
    PORT
      LAYER M4 ;
        RECT  0 9.936 0.084 9.96 ;
    END
  END d[476]
  PIN d[477]
    DIRECTION INPUT ;
    USE SIGNAL ;
    PORT
      LAYER M4 ;
        RECT  0 10.032 0.084 10.056 ;
    END
  END d[477]
  PIN d[478]
    DIRECTION INPUT ;
    USE SIGNAL ;
    PORT
      LAYER M4 ;
        RECT  0 10.128 0.084 10.152 ;
    END
  END d[478]
  PIN d[479]
    DIRECTION INPUT ;
    USE SIGNAL ;
    PORT
      LAYER M4 ;
        RECT  0 10.224 0.084 10.248 ;
    END
  END d[479]
  PIN d[47]
    DIRECTION INPUT ;
    USE SIGNAL ;
    PORT
      LAYER M4 ;
        RECT  0 34.032 0.084 34.056 ;
    END
  END d[47]
  PIN d[480]
    DIRECTION INPUT ;
    USE SIGNAL ;
    PORT
      LAYER M4 ;
        RECT  0 45.648 0.084 45.672 ;
    END
  END d[480]
  PIN d[481]
    DIRECTION INPUT ;
    USE SIGNAL ;
    PORT
      LAYER M4 ;
        RECT  0 45.744 0.084 45.768 ;
    END
  END d[481]
  PIN d[482]
    DIRECTION INPUT ;
    USE SIGNAL ;
    PORT
      LAYER M4 ;
        RECT  0 45.84 0.084 45.864 ;
    END
  END d[482]
  PIN d[483]
    DIRECTION INPUT ;
    USE SIGNAL ;
    PORT
      LAYER M4 ;
        RECT  0 45.936 0.084 45.96 ;
    END
  END d[483]
  PIN d[484]
    DIRECTION INPUT ;
    USE SIGNAL ;
    PORT
      LAYER M4 ;
        RECT  0 46.032 0.084 46.056 ;
    END
  END d[484]
  PIN d[485]
    DIRECTION INPUT ;
    USE SIGNAL ;
    PORT
      LAYER M4 ;
        RECT  0 46.128 0.084 46.152 ;
    END
  END d[485]
  PIN d[486]
    DIRECTION INPUT ;
    USE SIGNAL ;
    PORT
      LAYER M4 ;
        RECT  0 46.224 0.084 46.248 ;
    END
  END d[486]
  PIN d[487]
    DIRECTION INPUT ;
    USE SIGNAL ;
    PORT
      LAYER M4 ;
        RECT  0 46.32 0.084 46.344 ;
    END
  END d[487]
  PIN d[488]
    DIRECTION INPUT ;
    USE SIGNAL ;
    PORT
      LAYER M4 ;
        RECT  0 46.416 0.084 46.44 ;
    END
  END d[488]
  PIN d[489]
    DIRECTION INPUT ;
    USE SIGNAL ;
    PORT
      LAYER M4 ;
        RECT  0 46.512 0.084 46.536 ;
    END
  END d[489]
  PIN d[48]
    DIRECTION INPUT ;
    USE SIGNAL ;
    PORT
      LAYER M4 ;
        RECT  0 34.128 0.084 34.152 ;
    END
  END d[48]
  PIN d[490]
    DIRECTION INPUT ;
    USE SIGNAL ;
    PORT
      LAYER M4 ;
        RECT  0 46.608 0.084 46.632 ;
    END
  END d[490]
  PIN d[491]
    DIRECTION INPUT ;
    USE SIGNAL ;
    PORT
      LAYER M4 ;
        RECT  0 46.704 0.084 46.728 ;
    END
  END d[491]
  PIN d[492]
    DIRECTION INPUT ;
    USE SIGNAL ;
    PORT
      LAYER M4 ;
        RECT  0 46.8 0.084 46.824 ;
    END
  END d[492]
  PIN d[493]
    DIRECTION INPUT ;
    USE SIGNAL ;
    PORT
      LAYER M4 ;
        RECT  0 46.896 0.084 46.92 ;
    END
  END d[493]
  PIN d[494]
    DIRECTION INPUT ;
    USE SIGNAL ;
    PORT
      LAYER M4 ;
        RECT  0 46.992 0.084 47.016 ;
    END
  END d[494]
  PIN d[495]
    DIRECTION INPUT ;
    USE SIGNAL ;
    PORT
      LAYER M4 ;
        RECT  0 47.088 0.084 47.112 ;
    END
  END d[495]
  PIN d[496]
    DIRECTION INPUT ;
    USE SIGNAL ;
    PORT
      LAYER M4 ;
        RECT  0 47.184 0.084 47.208 ;
    END
  END d[496]
  PIN d[497]
    DIRECTION INPUT ;
    USE SIGNAL ;
    PORT
      LAYER M4 ;
        RECT  0 47.28 0.084 47.304 ;
    END
  END d[497]
  PIN d[498]
    DIRECTION INPUT ;
    USE SIGNAL ;
    PORT
      LAYER M4 ;
        RECT  0 47.376 0.084 47.4 ;
    END
  END d[498]
  PIN d[499]
    DIRECTION INPUT ;
    USE SIGNAL ;
    PORT
      LAYER M4 ;
        RECT  0 47.472 0.084 47.496 ;
    END
  END d[499]
  PIN d[49]
    DIRECTION INPUT ;
    USE SIGNAL ;
    PORT
      LAYER M4 ;
        RECT  0 34.224 0.084 34.248 ;
    END
  END d[49]
  PIN d[4]
    DIRECTION INPUT ;
    USE SIGNAL ;
    PORT
      LAYER M4 ;
        RECT  0 36.048 0.084 36.072 ;
    END
  END d[4]
  PIN d[500]
    DIRECTION INPUT ;
    USE SIGNAL ;
    PORT
      LAYER M4 ;
        RECT  0 47.568 0.084 47.592 ;
    END
  END d[500]
  PIN d[501]
    DIRECTION INPUT ;
    USE SIGNAL ;
    PORT
      LAYER M4 ;
        RECT  0 47.664 0.084 47.688 ;
    END
  END d[501]
  PIN d[502]
    DIRECTION INPUT ;
    USE SIGNAL ;
    PORT
      LAYER M4 ;
        RECT  0 47.76 0.084 47.784 ;
    END
  END d[502]
  PIN d[503]
    DIRECTION INPUT ;
    USE SIGNAL ;
    PORT
      LAYER M4 ;
        RECT  0 47.856 0.084 47.88 ;
    END
  END d[503]
  PIN d[504]
    DIRECTION INPUT ;
    USE SIGNAL ;
    PORT
      LAYER M4 ;
        RECT  0 47.952 0.084 47.976 ;
    END
  END d[504]
  PIN d[505]
    DIRECTION INPUT ;
    USE SIGNAL ;
    PORT
      LAYER M4 ;
        RECT  0 48.048 0.084 48.072 ;
    END
  END d[505]
  PIN d[506]
    DIRECTION INPUT ;
    USE SIGNAL ;
    PORT
      LAYER M4 ;
        RECT  0 48.144 0.084 48.168 ;
    END
  END d[506]
  PIN d[507]
    DIRECTION INPUT ;
    USE SIGNAL ;
    PORT
      LAYER M4 ;
        RECT  0 48.24 0.084 48.264 ;
    END
  END d[507]
  PIN d[508]
    DIRECTION INPUT ;
    USE SIGNAL ;
    PORT
      LAYER M4 ;
        RECT  0 48.336 0.084 48.36 ;
    END
  END d[508]
  PIN d[509]
    DIRECTION INPUT ;
    USE SIGNAL ;
    PORT
      LAYER M4 ;
        RECT  0 48.432 0.084 48.456 ;
    END
  END d[509]
  PIN d[50]
    DIRECTION INPUT ;
    USE SIGNAL ;
    PORT
      LAYER M4 ;
        RECT  0 34.32 0.084 34.344 ;
    END
  END d[50]
  PIN d[510]
    DIRECTION INPUT ;
    USE SIGNAL ;
    PORT
      LAYER M4 ;
        RECT  0 48.528 0.084 48.552 ;
    END
  END d[510]
  PIN d[511]
    DIRECTION INPUT ;
    USE SIGNAL ;
    PORT
      LAYER M4 ;
        RECT  0 48.624 0.084 48.648 ;
    END
  END d[511]
  PIN d[51]
    DIRECTION INPUT ;
    USE SIGNAL ;
    PORT
      LAYER M4 ;
        RECT  0 34.416 0.084 34.44 ;
    END
  END d[51]
  PIN d[52]
    DIRECTION INPUT ;
    USE SIGNAL ;
    PORT
      LAYER M4 ;
        RECT  0 34.512 0.084 34.536 ;
    END
  END d[52]
  PIN d[53]
    DIRECTION INPUT ;
    USE SIGNAL ;
    PORT
      LAYER M4 ;
        RECT  0 34.608 0.084 34.632 ;
    END
  END d[53]
  PIN d[54]
    DIRECTION INPUT ;
    USE SIGNAL ;
    PORT
      LAYER M4 ;
        RECT  0 34.704 0.084 34.728 ;
    END
  END d[54]
  PIN d[55]
    DIRECTION INPUT ;
    USE SIGNAL ;
    PORT
      LAYER M4 ;
        RECT  0 34.8 0.084 34.824 ;
    END
  END d[55]
  PIN d[56]
    DIRECTION INPUT ;
    USE SIGNAL ;
    PORT
      LAYER M4 ;
        RECT  0 34.896 0.084 34.92 ;
    END
  END d[56]
  PIN d[57]
    DIRECTION INPUT ;
    USE SIGNAL ;
    PORT
      LAYER M4 ;
        RECT  0 34.992 0.084 35.016 ;
    END
  END d[57]
  PIN d[58]
    DIRECTION INPUT ;
    USE SIGNAL ;
    PORT
      LAYER M4 ;
        RECT  0 35.088 0.084 35.112 ;
    END
  END d[58]
  PIN d[59]
    DIRECTION INPUT ;
    USE SIGNAL ;
    PORT
      LAYER M4 ;
        RECT  0 35.184 0.084 35.208 ;
    END
  END d[59]
  PIN d[5]
    DIRECTION INPUT ;
    USE SIGNAL ;
    PORT
      LAYER M4 ;
        RECT  0 36.144 0.084 36.168 ;
    END
  END d[5]
  PIN d[60]
    DIRECTION INPUT ;
    USE SIGNAL ;
    PORT
      LAYER M4 ;
        RECT  0 35.28 0.084 35.304 ;
    END
  END d[60]
  PIN d[61]
    DIRECTION INPUT ;
    USE SIGNAL ;
    PORT
      LAYER M4 ;
        RECT  0 35.376 0.084 35.4 ;
    END
  END d[61]
  PIN d[62]
    DIRECTION INPUT ;
    USE SIGNAL ;
    PORT
      LAYER M4 ;
        RECT  0 35.472 0.084 35.496 ;
    END
  END d[62]
  PIN d[63]
    DIRECTION INPUT ;
    USE SIGNAL ;
    PORT
      LAYER M4 ;
        RECT  0 35.568 0.084 35.592 ;
    END
  END d[63]
  PIN d[64]
    DIRECTION INPUT ;
    USE SIGNAL ;
    PORT
      LAYER M4 ;
        RECT  0 10.32 0.084 10.344 ;
    END
  END d[64]
  PIN d[65]
    DIRECTION INPUT ;
    USE SIGNAL ;
    PORT
      LAYER M4 ;
        RECT  0 10.416 0.084 10.44 ;
    END
  END d[65]
  PIN d[66]
    DIRECTION INPUT ;
    USE SIGNAL ;
    PORT
      LAYER M4 ;
        RECT  0 10.512 0.084 10.536 ;
    END
  END d[66]
  PIN d[67]
    DIRECTION INPUT ;
    USE SIGNAL ;
    PORT
      LAYER M4 ;
        RECT  0 10.608 0.084 10.632 ;
    END
  END d[67]
  PIN d[68]
    DIRECTION INPUT ;
    USE SIGNAL ;
    PORT
      LAYER M4 ;
        RECT  0 10.704 0.084 10.728 ;
    END
  END d[68]
  PIN d[69]
    DIRECTION INPUT ;
    USE SIGNAL ;
    PORT
      LAYER M4 ;
        RECT  0 10.8 0.084 10.824 ;
    END
  END d[69]
  PIN d[6]
    DIRECTION INPUT ;
    USE SIGNAL ;
    PORT
      LAYER M4 ;
        RECT  0 36.24 0.084 36.264 ;
    END
  END d[6]
  PIN d[70]
    DIRECTION INPUT ;
    USE SIGNAL ;
    PORT
      LAYER M4 ;
        RECT  0 10.896 0.084 10.92 ;
    END
  END d[70]
  PIN d[71]
    DIRECTION INPUT ;
    USE SIGNAL ;
    PORT
      LAYER M4 ;
        RECT  0 10.992 0.084 11.016 ;
    END
  END d[71]
  PIN d[72]
    DIRECTION INPUT ;
    USE SIGNAL ;
    PORT
      LAYER M4 ;
        RECT  0 11.088 0.084 11.112 ;
    END
  END d[72]
  PIN d[73]
    DIRECTION INPUT ;
    USE SIGNAL ;
    PORT
      LAYER M4 ;
        RECT  0 11.184 0.084 11.208 ;
    END
  END d[73]
  PIN d[74]
    DIRECTION INPUT ;
    USE SIGNAL ;
    PORT
      LAYER M4 ;
        RECT  0 11.28 0.084 11.304 ;
    END
  END d[74]
  PIN d[75]
    DIRECTION INPUT ;
    USE SIGNAL ;
    PORT
      LAYER M4 ;
        RECT  0 11.376 0.084 11.4 ;
    END
  END d[75]
  PIN d[76]
    DIRECTION INPUT ;
    USE SIGNAL ;
    PORT
      LAYER M4 ;
        RECT  0 11.472 0.084 11.496 ;
    END
  END d[76]
  PIN d[77]
    DIRECTION INPUT ;
    USE SIGNAL ;
    PORT
      LAYER M4 ;
        RECT  0 11.568 0.084 11.592 ;
    END
  END d[77]
  PIN d[78]
    DIRECTION INPUT ;
    USE SIGNAL ;
    PORT
      LAYER M4 ;
        RECT  0 11.664 0.084 11.688 ;
    END
  END d[78]
  PIN d[79]
    DIRECTION INPUT ;
    USE SIGNAL ;
    PORT
      LAYER M4 ;
        RECT  0 11.76 0.084 11.784 ;
    END
  END d[79]
  PIN d[7]
    DIRECTION INPUT ;
    USE SIGNAL ;
    PORT
      LAYER M4 ;
        RECT  0 36.336 0.084 36.36 ;
    END
  END d[7]
  PIN d[80]
    DIRECTION INPUT ;
    USE SIGNAL ;
    PORT
      LAYER M4 ;
        RECT  0 11.856 0.084 11.88 ;
    END
  END d[80]
  PIN d[81]
    DIRECTION INPUT ;
    USE SIGNAL ;
    PORT
      LAYER M4 ;
        RECT  0 11.952 0.084 11.976 ;
    END
  END d[81]
  PIN d[82]
    DIRECTION INPUT ;
    USE SIGNAL ;
    PORT
      LAYER M4 ;
        RECT  0 12.048 0.084 12.072 ;
    END
  END d[82]
  PIN d[83]
    DIRECTION INPUT ;
    USE SIGNAL ;
    PORT
      LAYER M4 ;
        RECT  0 12.144 0.084 12.168 ;
    END
  END d[83]
  PIN d[84]
    DIRECTION INPUT ;
    USE SIGNAL ;
    PORT
      LAYER M4 ;
        RECT  0 12.24 0.084 12.264 ;
    END
  END d[84]
  PIN d[85]
    DIRECTION INPUT ;
    USE SIGNAL ;
    PORT
      LAYER M4 ;
        RECT  0 12.336 0.084 12.36 ;
    END
  END d[85]
  PIN d[86]
    DIRECTION INPUT ;
    USE SIGNAL ;
    PORT
      LAYER M4 ;
        RECT  0 12.432 0.084 12.456 ;
    END
  END d[86]
  PIN d[87]
    DIRECTION INPUT ;
    USE SIGNAL ;
    PORT
      LAYER M4 ;
        RECT  0 12.528 0.084 12.552 ;
    END
  END d[87]
  PIN d[88]
    DIRECTION INPUT ;
    USE SIGNAL ;
    PORT
      LAYER M4 ;
        RECT  0 12.624 0.084 12.648 ;
    END
  END d[88]
  PIN d[89]
    DIRECTION INPUT ;
    USE SIGNAL ;
    PORT
      LAYER M4 ;
        RECT  0 12.72 0.084 12.744 ;
    END
  END d[89]
  PIN d[8]
    DIRECTION INPUT ;
    USE SIGNAL ;
    PORT
      LAYER M4 ;
        RECT  0 36.432 0.084 36.456 ;
    END
  END d[8]
  PIN d[90]
    DIRECTION INPUT ;
    USE SIGNAL ;
    PORT
      LAYER M4 ;
        RECT  0 12.816 0.084 12.84 ;
    END
  END d[90]
  PIN d[91]
    DIRECTION INPUT ;
    USE SIGNAL ;
    PORT
      LAYER M4 ;
        RECT  0 12.912 0.084 12.936 ;
    END
  END d[91]
  PIN d[92]
    DIRECTION INPUT ;
    USE SIGNAL ;
    PORT
      LAYER M4 ;
        RECT  0 13.008 0.084 13.032 ;
    END
  END d[92]
  PIN d[93]
    DIRECTION INPUT ;
    USE SIGNAL ;
    PORT
      LAYER M4 ;
        RECT  0 13.104 0.084 13.128 ;
    END
  END d[93]
  PIN d[94]
    DIRECTION INPUT ;
    USE SIGNAL ;
    PORT
      LAYER M4 ;
        RECT  0 13.2 0.084 13.224 ;
    END
  END d[94]
  PIN d[95]
    DIRECTION INPUT ;
    USE SIGNAL ;
    PORT
      LAYER M4 ;
        RECT  0 13.296 0.084 13.32 ;
    END
  END d[95]
  PIN d[96]
    DIRECTION INPUT ;
    USE SIGNAL ;
    PORT
      LAYER M4 ;
        RECT  0 29.52 0.084 29.544 ;
    END
  END d[96]
  PIN d[97]
    DIRECTION INPUT ;
    USE SIGNAL ;
    PORT
      LAYER M4 ;
        RECT  0 29.616 0.084 29.64 ;
    END
  END d[97]
  PIN d[98]
    DIRECTION INPUT ;
    USE SIGNAL ;
    PORT
      LAYER M4 ;
        RECT  0 29.712 0.084 29.736 ;
    END
  END d[98]
  PIN d[99]
    DIRECTION INPUT ;
    USE SIGNAL ;
    PORT
      LAYER M4 ;
        RECT  0 29.808 0.084 29.832 ;
    END
  END d[99]
  PIN d[9]
    DIRECTION INPUT ;
    USE SIGNAL ;
    PORT
      LAYER M4 ;
        RECT  0 36.528 0.084 36.552 ;
    END
  END d[9]
  PIN q[0]
    DIRECTION OUTPUT ;
    USE SIGNAL ;
    PORT
      LAYER M4 ;
        RECT  49.596 35.28 49.68 35.304 ;
    END
  END q[0]
  PIN q[100]
    DIRECTION OUTPUT ;
    USE SIGNAL ;
    PORT
      LAYER M4 ;
        RECT  49.596 32.592 49.68 32.616 ;
    END
  END q[100]
  PIN q[101]
    DIRECTION OUTPUT ;
    USE SIGNAL ;
    PORT
      LAYER M4 ;
        RECT  49.596 32.688 49.68 32.712 ;
    END
  END q[101]
  PIN q[102]
    DIRECTION OUTPUT ;
    USE SIGNAL ;
    PORT
      LAYER M4 ;
        RECT  49.596 32.784 49.68 32.808 ;
    END
  END q[102]
  PIN q[103]
    DIRECTION OUTPUT ;
    USE SIGNAL ;
    PORT
      LAYER M4 ;
        RECT  49.596 32.88 49.68 32.904 ;
    END
  END q[103]
  PIN q[104]
    DIRECTION OUTPUT ;
    USE SIGNAL ;
    PORT
      LAYER M4 ;
        RECT  49.596 32.976 49.68 33 ;
    END
  END q[104]
  PIN q[105]
    DIRECTION OUTPUT ;
    USE SIGNAL ;
    PORT
      LAYER M4 ;
        RECT  49.596 33.072 49.68 33.096 ;
    END
  END q[105]
  PIN q[106]
    DIRECTION OUTPUT ;
    USE SIGNAL ;
    PORT
      LAYER M4 ;
        RECT  49.596 33.168 49.68 33.192 ;
    END
  END q[106]
  PIN q[107]
    DIRECTION OUTPUT ;
    USE SIGNAL ;
    PORT
      LAYER M4 ;
        RECT  49.596 33.264 49.68 33.288 ;
    END
  END q[107]
  PIN q[108]
    DIRECTION OUTPUT ;
    USE SIGNAL ;
    PORT
      LAYER M4 ;
        RECT  49.596 33.36 49.68 33.384 ;
    END
  END q[108]
  PIN q[109]
    DIRECTION OUTPUT ;
    USE SIGNAL ;
    PORT
      LAYER M4 ;
        RECT  49.596 33.456 49.68 33.48 ;
    END
  END q[109]
  PIN q[10]
    DIRECTION OUTPUT ;
    USE SIGNAL ;
    PORT
      LAYER M4 ;
        RECT  49.596 36.24 49.68 36.264 ;
    END
  END q[10]
  PIN q[110]
    DIRECTION OUTPUT ;
    USE SIGNAL ;
    PORT
      LAYER M4 ;
        RECT  49.596 33.552 49.68 33.576 ;
    END
  END q[110]
  PIN q[111]
    DIRECTION OUTPUT ;
    USE SIGNAL ;
    PORT
      LAYER M4 ;
        RECT  49.596 33.648 49.68 33.672 ;
    END
  END q[111]
  PIN q[112]
    DIRECTION OUTPUT ;
    USE SIGNAL ;
    PORT
      LAYER M4 ;
        RECT  49.596 33.744 49.68 33.768 ;
    END
  END q[112]
  PIN q[113]
    DIRECTION OUTPUT ;
    USE SIGNAL ;
    PORT
      LAYER M4 ;
        RECT  49.596 33.84 49.68 33.864 ;
    END
  END q[113]
  PIN q[114]
    DIRECTION OUTPUT ;
    USE SIGNAL ;
    PORT
      LAYER M4 ;
        RECT  49.596 33.936 49.68 33.96 ;
    END
  END q[114]
  PIN q[115]
    DIRECTION OUTPUT ;
    USE SIGNAL ;
    PORT
      LAYER M4 ;
        RECT  49.596 34.032 49.68 34.056 ;
    END
  END q[115]
  PIN q[116]
    DIRECTION OUTPUT ;
    USE SIGNAL ;
    PORT
      LAYER M4 ;
        RECT  49.596 34.128 49.68 34.152 ;
    END
  END q[116]
  PIN q[117]
    DIRECTION OUTPUT ;
    USE SIGNAL ;
    PORT
      LAYER M4 ;
        RECT  49.596 34.224 49.68 34.248 ;
    END
  END q[117]
  PIN q[118]
    DIRECTION OUTPUT ;
    USE SIGNAL ;
    PORT
      LAYER M4 ;
        RECT  49.596 34.32 49.68 34.344 ;
    END
  END q[118]
  PIN q[119]
    DIRECTION OUTPUT ;
    USE SIGNAL ;
    PORT
      LAYER M4 ;
        RECT  49.596 34.416 49.68 34.44 ;
    END
  END q[119]
  PIN q[11]
    DIRECTION OUTPUT ;
    USE SIGNAL ;
    PORT
      LAYER M4 ;
        RECT  49.596 36.336 49.68 36.36 ;
    END
  END q[11]
  PIN q[120]
    DIRECTION OUTPUT ;
    USE SIGNAL ;
    PORT
      LAYER M4 ;
        RECT  49.596 34.512 49.68 34.536 ;
    END
  END q[120]
  PIN q[121]
    DIRECTION OUTPUT ;
    USE SIGNAL ;
    PORT
      LAYER M4 ;
        RECT  49.596 34.608 49.68 34.632 ;
    END
  END q[121]
  PIN q[122]
    DIRECTION OUTPUT ;
    USE SIGNAL ;
    PORT
      LAYER M4 ;
        RECT  49.596 34.704 49.68 34.728 ;
    END
  END q[122]
  PIN q[123]
    DIRECTION OUTPUT ;
    USE SIGNAL ;
    PORT
      LAYER M4 ;
        RECT  49.596 34.8 49.68 34.824 ;
    END
  END q[123]
  PIN q[124]
    DIRECTION OUTPUT ;
    USE SIGNAL ;
    PORT
      LAYER M4 ;
        RECT  49.596 34.896 49.68 34.92 ;
    END
  END q[124]
  PIN q[125]
    DIRECTION OUTPUT ;
    USE SIGNAL ;
    PORT
      LAYER M4 ;
        RECT  49.596 34.992 49.68 35.016 ;
    END
  END q[125]
  PIN q[126]
    DIRECTION OUTPUT ;
    USE SIGNAL ;
    PORT
      LAYER M4 ;
        RECT  49.596 35.088 49.68 35.112 ;
    END
  END q[126]
  PIN q[127]
    DIRECTION OUTPUT ;
    USE SIGNAL ;
    PORT
      LAYER M4 ;
        RECT  49.596 35.184 49.68 35.208 ;
    END
  END q[127]
  PIN q[128]
    DIRECTION OUTPUT ;
    USE SIGNAL ;
    PORT
      LAYER M4 ;
        RECT  49.596 22.992 49.68 23.016 ;
    END
  END q[128]
  PIN q[129]
    DIRECTION OUTPUT ;
    USE SIGNAL ;
    PORT
      LAYER M4 ;
        RECT  49.596 23.088 49.68 23.112 ;
    END
  END q[129]
  PIN q[12]
    DIRECTION OUTPUT ;
    USE SIGNAL ;
    PORT
      LAYER M4 ;
        RECT  49.596 36.432 49.68 36.456 ;
    END
  END q[12]
  PIN q[130]
    DIRECTION OUTPUT ;
    USE SIGNAL ;
    PORT
      LAYER M4 ;
        RECT  49.596 23.184 49.68 23.208 ;
    END
  END q[130]
  PIN q[131]
    DIRECTION OUTPUT ;
    USE SIGNAL ;
    PORT
      LAYER M4 ;
        RECT  49.596 23.28 49.68 23.304 ;
    END
  END q[131]
  PIN q[132]
    DIRECTION OUTPUT ;
    USE SIGNAL ;
    PORT
      LAYER M4 ;
        RECT  49.596 23.376 49.68 23.4 ;
    END
  END q[132]
  PIN q[133]
    DIRECTION OUTPUT ;
    USE SIGNAL ;
    PORT
      LAYER M4 ;
        RECT  49.596 23.472 49.68 23.496 ;
    END
  END q[133]
  PIN q[134]
    DIRECTION OUTPUT ;
    USE SIGNAL ;
    PORT
      LAYER M4 ;
        RECT  49.596 23.568 49.68 23.592 ;
    END
  END q[134]
  PIN q[135]
    DIRECTION OUTPUT ;
    USE SIGNAL ;
    PORT
      LAYER M4 ;
        RECT  49.596 23.664 49.68 23.688 ;
    END
  END q[135]
  PIN q[136]
    DIRECTION OUTPUT ;
    USE SIGNAL ;
    PORT
      LAYER M4 ;
        RECT  49.596 23.76 49.68 23.784 ;
    END
  END q[136]
  PIN q[137]
    DIRECTION OUTPUT ;
    USE SIGNAL ;
    PORT
      LAYER M4 ;
        RECT  49.596 23.856 49.68 23.88 ;
    END
  END q[137]
  PIN q[138]
    DIRECTION OUTPUT ;
    USE SIGNAL ;
    PORT
      LAYER M4 ;
        RECT  49.596 23.952 49.68 23.976 ;
    END
  END q[138]
  PIN q[139]
    DIRECTION OUTPUT ;
    USE SIGNAL ;
    PORT
      LAYER M4 ;
        RECT  49.596 24.048 49.68 24.072 ;
    END
  END q[139]
  PIN q[13]
    DIRECTION OUTPUT ;
    USE SIGNAL ;
    PORT
      LAYER M4 ;
        RECT  49.596 36.528 49.68 36.552 ;
    END
  END q[13]
  PIN q[140]
    DIRECTION OUTPUT ;
    USE SIGNAL ;
    PORT
      LAYER M4 ;
        RECT  49.596 24.144 49.68 24.168 ;
    END
  END q[140]
  PIN q[141]
    DIRECTION OUTPUT ;
    USE SIGNAL ;
    PORT
      LAYER M4 ;
        RECT  49.596 24.24 49.68 24.264 ;
    END
  END q[141]
  PIN q[142]
    DIRECTION OUTPUT ;
    USE SIGNAL ;
    PORT
      LAYER M4 ;
        RECT  49.596 24.336 49.68 24.36 ;
    END
  END q[142]
  PIN q[143]
    DIRECTION OUTPUT ;
    USE SIGNAL ;
    PORT
      LAYER M4 ;
        RECT  49.596 24.432 49.68 24.456 ;
    END
  END q[143]
  PIN q[144]
    DIRECTION OUTPUT ;
    USE SIGNAL ;
    PORT
      LAYER M4 ;
        RECT  49.596 24.528 49.68 24.552 ;
    END
  END q[144]
  PIN q[145]
    DIRECTION OUTPUT ;
    USE SIGNAL ;
    PORT
      LAYER M4 ;
        RECT  49.596 24.624 49.68 24.648 ;
    END
  END q[145]
  PIN q[146]
    DIRECTION OUTPUT ;
    USE SIGNAL ;
    PORT
      LAYER M4 ;
        RECT  49.596 24.72 49.68 24.744 ;
    END
  END q[146]
  PIN q[147]
    DIRECTION OUTPUT ;
    USE SIGNAL ;
    PORT
      LAYER M4 ;
        RECT  49.596 24.816 49.68 24.84 ;
    END
  END q[147]
  PIN q[148]
    DIRECTION OUTPUT ;
    USE SIGNAL ;
    PORT
      LAYER M4 ;
        RECT  49.596 24.912 49.68 24.936 ;
    END
  END q[148]
  PIN q[149]
    DIRECTION OUTPUT ;
    USE SIGNAL ;
    PORT
      LAYER M4 ;
        RECT  49.596 25.008 49.68 25.032 ;
    END
  END q[149]
  PIN q[14]
    DIRECTION OUTPUT ;
    USE SIGNAL ;
    PORT
      LAYER M4 ;
        RECT  49.596 36.624 49.68 36.648 ;
    END
  END q[14]
  PIN q[150]
    DIRECTION OUTPUT ;
    USE SIGNAL ;
    PORT
      LAYER M4 ;
        RECT  49.596 25.104 49.68 25.128 ;
    END
  END q[150]
  PIN q[151]
    DIRECTION OUTPUT ;
    USE SIGNAL ;
    PORT
      LAYER M4 ;
        RECT  49.596 25.2 49.68 25.224 ;
    END
  END q[151]
  PIN q[152]
    DIRECTION OUTPUT ;
    USE SIGNAL ;
    PORT
      LAYER M4 ;
        RECT  49.596 25.296 49.68 25.32 ;
    END
  END q[152]
  PIN q[153]
    DIRECTION OUTPUT ;
    USE SIGNAL ;
    PORT
      LAYER M4 ;
        RECT  49.596 25.392 49.68 25.416 ;
    END
  END q[153]
  PIN q[154]
    DIRECTION OUTPUT ;
    USE SIGNAL ;
    PORT
      LAYER M4 ;
        RECT  49.596 25.488 49.68 25.512 ;
    END
  END q[154]
  PIN q[155]
    DIRECTION OUTPUT ;
    USE SIGNAL ;
    PORT
      LAYER M4 ;
        RECT  49.596 25.584 49.68 25.608 ;
    END
  END q[155]
  PIN q[156]
    DIRECTION OUTPUT ;
    USE SIGNAL ;
    PORT
      LAYER M4 ;
        RECT  49.596 25.68 49.68 25.704 ;
    END
  END q[156]
  PIN q[157]
    DIRECTION OUTPUT ;
    USE SIGNAL ;
    PORT
      LAYER M4 ;
        RECT  49.596 25.776 49.68 25.8 ;
    END
  END q[157]
  PIN q[158]
    DIRECTION OUTPUT ;
    USE SIGNAL ;
    PORT
      LAYER M4 ;
        RECT  49.596 25.872 49.68 25.896 ;
    END
  END q[158]
  PIN q[159]
    DIRECTION OUTPUT ;
    USE SIGNAL ;
    PORT
      LAYER M4 ;
        RECT  49.596 25.968 49.68 25.992 ;
    END
  END q[159]
  PIN q[15]
    DIRECTION OUTPUT ;
    USE SIGNAL ;
    PORT
      LAYER M4 ;
        RECT  49.596 36.72 49.68 36.744 ;
    END
  END q[15]
  PIN q[160]
    DIRECTION OUTPUT ;
    USE SIGNAL ;
    PORT
      LAYER M4 ;
        RECT  49.596 26.064 49.68 26.088 ;
    END
  END q[160]
  PIN q[161]
    DIRECTION OUTPUT ;
    USE SIGNAL ;
    PORT
      LAYER M4 ;
        RECT  49.596 26.16 49.68 26.184 ;
    END
  END q[161]
  PIN q[162]
    DIRECTION OUTPUT ;
    USE SIGNAL ;
    PORT
      LAYER M4 ;
        RECT  49.596 26.256 49.68 26.28 ;
    END
  END q[162]
  PIN q[163]
    DIRECTION OUTPUT ;
    USE SIGNAL ;
    PORT
      LAYER M4 ;
        RECT  49.596 26.352 49.68 26.376 ;
    END
  END q[163]
  PIN q[164]
    DIRECTION OUTPUT ;
    USE SIGNAL ;
    PORT
      LAYER M4 ;
        RECT  49.596 26.448 49.68 26.472 ;
    END
  END q[164]
  PIN q[165]
    DIRECTION OUTPUT ;
    USE SIGNAL ;
    PORT
      LAYER M4 ;
        RECT  49.596 26.544 49.68 26.568 ;
    END
  END q[165]
  PIN q[166]
    DIRECTION OUTPUT ;
    USE SIGNAL ;
    PORT
      LAYER M4 ;
        RECT  49.596 26.64 49.68 26.664 ;
    END
  END q[166]
  PIN q[167]
    DIRECTION OUTPUT ;
    USE SIGNAL ;
    PORT
      LAYER M4 ;
        RECT  49.596 26.736 49.68 26.76 ;
    END
  END q[167]
  PIN q[168]
    DIRECTION OUTPUT ;
    USE SIGNAL ;
    PORT
      LAYER M4 ;
        RECT  49.596 26.832 49.68 26.856 ;
    END
  END q[168]
  PIN q[169]
    DIRECTION OUTPUT ;
    USE SIGNAL ;
    PORT
      LAYER M4 ;
        RECT  49.596 26.928 49.68 26.952 ;
    END
  END q[169]
  PIN q[16]
    DIRECTION OUTPUT ;
    USE SIGNAL ;
    PORT
      LAYER M4 ;
        RECT  49.596 36.816 49.68 36.84 ;
    END
  END q[16]
  PIN q[170]
    DIRECTION OUTPUT ;
    USE SIGNAL ;
    PORT
      LAYER M4 ;
        RECT  49.596 27.024 49.68 27.048 ;
    END
  END q[170]
  PIN q[171]
    DIRECTION OUTPUT ;
    USE SIGNAL ;
    PORT
      LAYER M4 ;
        RECT  49.596 27.12 49.68 27.144 ;
    END
  END q[171]
  PIN q[172]
    DIRECTION OUTPUT ;
    USE SIGNAL ;
    PORT
      LAYER M4 ;
        RECT  49.596 27.216 49.68 27.24 ;
    END
  END q[172]
  PIN q[173]
    DIRECTION OUTPUT ;
    USE SIGNAL ;
    PORT
      LAYER M4 ;
        RECT  49.596 27.312 49.68 27.336 ;
    END
  END q[173]
  PIN q[174]
    DIRECTION OUTPUT ;
    USE SIGNAL ;
    PORT
      LAYER M4 ;
        RECT  49.596 27.408 49.68 27.432 ;
    END
  END q[174]
  PIN q[175]
    DIRECTION OUTPUT ;
    USE SIGNAL ;
    PORT
      LAYER M4 ;
        RECT  49.596 27.504 49.68 27.528 ;
    END
  END q[175]
  PIN q[176]
    DIRECTION OUTPUT ;
    USE SIGNAL ;
    PORT
      LAYER M4 ;
        RECT  49.596 27.6 49.68 27.624 ;
    END
  END q[176]
  PIN q[177]
    DIRECTION OUTPUT ;
    USE SIGNAL ;
    PORT
      LAYER M4 ;
        RECT  49.596 27.696 49.68 27.72 ;
    END
  END q[177]
  PIN q[178]
    DIRECTION OUTPUT ;
    USE SIGNAL ;
    PORT
      LAYER M4 ;
        RECT  49.596 27.792 49.68 27.816 ;
    END
  END q[178]
  PIN q[179]
    DIRECTION OUTPUT ;
    USE SIGNAL ;
    PORT
      LAYER M4 ;
        RECT  49.596 27.888 49.68 27.912 ;
    END
  END q[179]
  PIN q[17]
    DIRECTION OUTPUT ;
    USE SIGNAL ;
    PORT
      LAYER M4 ;
        RECT  49.596 36.912 49.68 36.936 ;
    END
  END q[17]
  PIN q[180]
    DIRECTION OUTPUT ;
    USE SIGNAL ;
    PORT
      LAYER M4 ;
        RECT  49.596 27.984 49.68 28.008 ;
    END
  END q[180]
  PIN q[181]
    DIRECTION OUTPUT ;
    USE SIGNAL ;
    PORT
      LAYER M4 ;
        RECT  49.596 28.08 49.68 28.104 ;
    END
  END q[181]
  PIN q[182]
    DIRECTION OUTPUT ;
    USE SIGNAL ;
    PORT
      LAYER M4 ;
        RECT  49.596 28.176 49.68 28.2 ;
    END
  END q[182]
  PIN q[183]
    DIRECTION OUTPUT ;
    USE SIGNAL ;
    PORT
      LAYER M4 ;
        RECT  49.596 28.272 49.68 28.296 ;
    END
  END q[183]
  PIN q[184]
    DIRECTION OUTPUT ;
    USE SIGNAL ;
    PORT
      LAYER M4 ;
        RECT  49.596 28.368 49.68 28.392 ;
    END
  END q[184]
  PIN q[185]
    DIRECTION OUTPUT ;
    USE SIGNAL ;
    PORT
      LAYER M4 ;
        RECT  49.596 28.464 49.68 28.488 ;
    END
  END q[185]
  PIN q[186]
    DIRECTION OUTPUT ;
    USE SIGNAL ;
    PORT
      LAYER M4 ;
        RECT  49.596 28.56 49.68 28.584 ;
    END
  END q[186]
  PIN q[187]
    DIRECTION OUTPUT ;
    USE SIGNAL ;
    PORT
      LAYER M4 ;
        RECT  49.596 28.656 49.68 28.68 ;
    END
  END q[187]
  PIN q[188]
    DIRECTION OUTPUT ;
    USE SIGNAL ;
    PORT
      LAYER M4 ;
        RECT  49.596 28.752 49.68 28.776 ;
    END
  END q[188]
  PIN q[189]
    DIRECTION OUTPUT ;
    USE SIGNAL ;
    PORT
      LAYER M4 ;
        RECT  49.596 28.848 49.68 28.872 ;
    END
  END q[189]
  PIN q[18]
    DIRECTION OUTPUT ;
    USE SIGNAL ;
    PORT
      LAYER M4 ;
        RECT  49.596 37.008 49.68 37.032 ;
    END
  END q[18]
  PIN q[190]
    DIRECTION OUTPUT ;
    USE SIGNAL ;
    PORT
      LAYER M4 ;
        RECT  49.596 28.944 49.68 28.968 ;
    END
  END q[190]
  PIN q[191]
    DIRECTION OUTPUT ;
    USE SIGNAL ;
    PORT
      LAYER M4 ;
        RECT  49.596 29.04 49.68 29.064 ;
    END
  END q[191]
  PIN q[192]
    DIRECTION OUTPUT ;
    USE SIGNAL ;
    PORT
      LAYER M4 ;
        RECT  49.596 48.336 49.68 48.36 ;
    END
  END q[192]
  PIN q[193]
    DIRECTION OUTPUT ;
    USE SIGNAL ;
    PORT
      LAYER M4 ;
        RECT  49.596 48.432 49.68 48.456 ;
    END
  END q[193]
  PIN q[194]
    DIRECTION OUTPUT ;
    USE SIGNAL ;
    PORT
      LAYER M4 ;
        RECT  49.596 48.528 49.68 48.552 ;
    END
  END q[194]
  PIN q[195]
    DIRECTION OUTPUT ;
    USE SIGNAL ;
    PORT
      LAYER M4 ;
        RECT  49.596 48.624 49.68 48.648 ;
    END
  END q[195]
  PIN q[196]
    DIRECTION OUTPUT ;
    USE SIGNAL ;
    PORT
      LAYER M4 ;
        RECT  49.596 48.72 49.68 48.744 ;
    END
  END q[196]
  PIN q[197]
    DIRECTION OUTPUT ;
    USE SIGNAL ;
    PORT
      LAYER M4 ;
        RECT  49.596 48.816 49.68 48.84 ;
    END
  END q[197]
  PIN q[198]
    DIRECTION OUTPUT ;
    USE SIGNAL ;
    PORT
      LAYER M4 ;
        RECT  49.596 48.912 49.68 48.936 ;
    END
  END q[198]
  PIN q[199]
    DIRECTION OUTPUT ;
    USE SIGNAL ;
    PORT
      LAYER M4 ;
        RECT  49.596 49.008 49.68 49.032 ;
    END
  END q[199]
  PIN q[19]
    DIRECTION OUTPUT ;
    USE SIGNAL ;
    PORT
      LAYER M4 ;
        RECT  49.596 37.104 49.68 37.128 ;
    END
  END q[19]
  PIN q[1]
    DIRECTION OUTPUT ;
    USE SIGNAL ;
    PORT
      LAYER M4 ;
        RECT  49.596 35.376 49.68 35.4 ;
    END
  END q[1]
  PIN q[200]
    DIRECTION OUTPUT ;
    USE SIGNAL ;
    PORT
      LAYER M4 ;
        RECT  49.596 49.104 49.68 49.128 ;
    END
  END q[200]
  PIN q[201]
    DIRECTION OUTPUT ;
    USE SIGNAL ;
    PORT
      LAYER M4 ;
        RECT  49.596 49.2 49.68 49.224 ;
    END
  END q[201]
  PIN q[202]
    DIRECTION OUTPUT ;
    USE SIGNAL ;
    PORT
      LAYER M4 ;
        RECT  49.596 49.296 49.68 49.32 ;
    END
  END q[202]
  PIN q[203]
    DIRECTION OUTPUT ;
    USE SIGNAL ;
    PORT
      LAYER M4 ;
        RECT  49.596 49.392 49.68 49.416 ;
    END
  END q[203]
  PIN q[204]
    DIRECTION OUTPUT ;
    USE SIGNAL ;
    PORT
      LAYER M4 ;
        RECT  49.596 49.488 49.68 49.512 ;
    END
  END q[204]
  PIN q[205]
    DIRECTION OUTPUT ;
    USE SIGNAL ;
    PORT
      LAYER M4 ;
        RECT  49.596 49.584 49.68 49.608 ;
    END
  END q[205]
  PIN q[206]
    DIRECTION OUTPUT ;
    USE SIGNAL ;
    PORT
      LAYER M4 ;
        RECT  49.596 49.68 49.68 49.704 ;
    END
  END q[206]
  PIN q[207]
    DIRECTION OUTPUT ;
    USE SIGNAL ;
    PORT
      LAYER M4 ;
        RECT  49.596 49.776 49.68 49.8 ;
    END
  END q[207]
  PIN q[208]
    DIRECTION OUTPUT ;
    USE SIGNAL ;
    PORT
      LAYER M4 ;
        RECT  49.596 49.872 49.68 49.896 ;
    END
  END q[208]
  PIN q[209]
    DIRECTION OUTPUT ;
    USE SIGNAL ;
    PORT
      LAYER M4 ;
        RECT  49.596 49.968 49.68 49.992 ;
    END
  END q[209]
  PIN q[20]
    DIRECTION OUTPUT ;
    USE SIGNAL ;
    PORT
      LAYER M4 ;
        RECT  49.596 37.2 49.68 37.224 ;
    END
  END q[20]
  PIN q[210]
    DIRECTION OUTPUT ;
    USE SIGNAL ;
    PORT
      LAYER M4 ;
        RECT  49.596 50.064 49.68 50.088 ;
    END
  END q[210]
  PIN q[211]
    DIRECTION OUTPUT ;
    USE SIGNAL ;
    PORT
      LAYER M4 ;
        RECT  49.596 50.16 49.68 50.184 ;
    END
  END q[211]
  PIN q[212]
    DIRECTION OUTPUT ;
    USE SIGNAL ;
    PORT
      LAYER M4 ;
        RECT  49.596 50.256 49.68 50.28 ;
    END
  END q[212]
  PIN q[213]
    DIRECTION OUTPUT ;
    USE SIGNAL ;
    PORT
      LAYER M4 ;
        RECT  49.596 50.352 49.68 50.376 ;
    END
  END q[213]
  PIN q[214]
    DIRECTION OUTPUT ;
    USE SIGNAL ;
    PORT
      LAYER M4 ;
        RECT  49.596 50.448 49.68 50.472 ;
    END
  END q[214]
  PIN q[215]
    DIRECTION OUTPUT ;
    USE SIGNAL ;
    PORT
      LAYER M4 ;
        RECT  49.596 50.544 49.68 50.568 ;
    END
  END q[215]
  PIN q[216]
    DIRECTION OUTPUT ;
    USE SIGNAL ;
    PORT
      LAYER M4 ;
        RECT  49.596 50.64 49.68 50.664 ;
    END
  END q[216]
  PIN q[217]
    DIRECTION OUTPUT ;
    USE SIGNAL ;
    PORT
      LAYER M4 ;
        RECT  49.596 50.736 49.68 50.76 ;
    END
  END q[217]
  PIN q[218]
    DIRECTION OUTPUT ;
    USE SIGNAL ;
    PORT
      LAYER M4 ;
        RECT  49.596 50.832 49.68 50.856 ;
    END
  END q[218]
  PIN q[219]
    DIRECTION OUTPUT ;
    USE SIGNAL ;
    PORT
      LAYER M4 ;
        RECT  49.596 50.928 49.68 50.952 ;
    END
  END q[219]
  PIN q[21]
    DIRECTION OUTPUT ;
    USE SIGNAL ;
    PORT
      LAYER M4 ;
        RECT  49.596 37.296 49.68 37.32 ;
    END
  END q[21]
  PIN q[220]
    DIRECTION OUTPUT ;
    USE SIGNAL ;
    PORT
      LAYER M4 ;
        RECT  49.596 51.024 49.68 51.048 ;
    END
  END q[220]
  PIN q[221]
    DIRECTION OUTPUT ;
    USE SIGNAL ;
    PORT
      LAYER M4 ;
        RECT  49.596 51.12 49.68 51.144 ;
    END
  END q[221]
  PIN q[222]
    DIRECTION OUTPUT ;
    USE SIGNAL ;
    PORT
      LAYER M4 ;
        RECT  49.596 51.216 49.68 51.24 ;
    END
  END q[222]
  PIN q[223]
    DIRECTION OUTPUT ;
    USE SIGNAL ;
    PORT
      LAYER M4 ;
        RECT  49.596 51.312 49.68 51.336 ;
    END
  END q[223]
  PIN q[224]
    DIRECTION OUTPUT ;
    USE SIGNAL ;
    PORT
      LAYER M4 ;
        RECT  49.596 39.12 49.68 39.144 ;
    END
  END q[224]
  PIN q[225]
    DIRECTION OUTPUT ;
    USE SIGNAL ;
    PORT
      LAYER M4 ;
        RECT  49.596 39.216 49.68 39.24 ;
    END
  END q[225]
  PIN q[226]
    DIRECTION OUTPUT ;
    USE SIGNAL ;
    PORT
      LAYER M4 ;
        RECT  49.596 39.312 49.68 39.336 ;
    END
  END q[226]
  PIN q[227]
    DIRECTION OUTPUT ;
    USE SIGNAL ;
    PORT
      LAYER M4 ;
        RECT  49.596 39.408 49.68 39.432 ;
    END
  END q[227]
  PIN q[228]
    DIRECTION OUTPUT ;
    USE SIGNAL ;
    PORT
      LAYER M4 ;
        RECT  49.596 39.504 49.68 39.528 ;
    END
  END q[228]
  PIN q[229]
    DIRECTION OUTPUT ;
    USE SIGNAL ;
    PORT
      LAYER M4 ;
        RECT  49.596 39.6 49.68 39.624 ;
    END
  END q[229]
  PIN q[22]
    DIRECTION OUTPUT ;
    USE SIGNAL ;
    PORT
      LAYER M4 ;
        RECT  49.596 37.392 49.68 37.416 ;
    END
  END q[22]
  PIN q[230]
    DIRECTION OUTPUT ;
    USE SIGNAL ;
    PORT
      LAYER M4 ;
        RECT  49.596 39.696 49.68 39.72 ;
    END
  END q[230]
  PIN q[231]
    DIRECTION OUTPUT ;
    USE SIGNAL ;
    PORT
      LAYER M4 ;
        RECT  49.596 39.792 49.68 39.816 ;
    END
  END q[231]
  PIN q[232]
    DIRECTION OUTPUT ;
    USE SIGNAL ;
    PORT
      LAYER M4 ;
        RECT  49.596 39.888 49.68 39.912 ;
    END
  END q[232]
  PIN q[233]
    DIRECTION OUTPUT ;
    USE SIGNAL ;
    PORT
      LAYER M4 ;
        RECT  49.596 39.984 49.68 40.008 ;
    END
  END q[233]
  PIN q[234]
    DIRECTION OUTPUT ;
    USE SIGNAL ;
    PORT
      LAYER M4 ;
        RECT  49.596 40.08 49.68 40.104 ;
    END
  END q[234]
  PIN q[235]
    DIRECTION OUTPUT ;
    USE SIGNAL ;
    PORT
      LAYER M4 ;
        RECT  49.596 40.176 49.68 40.2 ;
    END
  END q[235]
  PIN q[236]
    DIRECTION OUTPUT ;
    USE SIGNAL ;
    PORT
      LAYER M4 ;
        RECT  49.596 40.272 49.68 40.296 ;
    END
  END q[236]
  PIN q[237]
    DIRECTION OUTPUT ;
    USE SIGNAL ;
    PORT
      LAYER M4 ;
        RECT  49.596 40.368 49.68 40.392 ;
    END
  END q[237]
  PIN q[238]
    DIRECTION OUTPUT ;
    USE SIGNAL ;
    PORT
      LAYER M4 ;
        RECT  49.596 40.464 49.68 40.488 ;
    END
  END q[238]
  PIN q[239]
    DIRECTION OUTPUT ;
    USE SIGNAL ;
    PORT
      LAYER M4 ;
        RECT  49.596 40.56 49.68 40.584 ;
    END
  END q[239]
  PIN q[23]
    DIRECTION OUTPUT ;
    USE SIGNAL ;
    PORT
      LAYER M4 ;
        RECT  49.596 37.488 49.68 37.512 ;
    END
  END q[23]
  PIN q[240]
    DIRECTION OUTPUT ;
    USE SIGNAL ;
    PORT
      LAYER M4 ;
        RECT  49.596 40.656 49.68 40.68 ;
    END
  END q[240]
  PIN q[241]
    DIRECTION OUTPUT ;
    USE SIGNAL ;
    PORT
      LAYER M4 ;
        RECT  49.596 40.752 49.68 40.776 ;
    END
  END q[241]
  PIN q[242]
    DIRECTION OUTPUT ;
    USE SIGNAL ;
    PORT
      LAYER M4 ;
        RECT  49.596 40.848 49.68 40.872 ;
    END
  END q[242]
  PIN q[243]
    DIRECTION OUTPUT ;
    USE SIGNAL ;
    PORT
      LAYER M4 ;
        RECT  49.596 40.944 49.68 40.968 ;
    END
  END q[243]
  PIN q[244]
    DIRECTION OUTPUT ;
    USE SIGNAL ;
    PORT
      LAYER M4 ;
        RECT  49.596 41.04 49.68 41.064 ;
    END
  END q[244]
  PIN q[245]
    DIRECTION OUTPUT ;
    USE SIGNAL ;
    PORT
      LAYER M4 ;
        RECT  49.596 41.136 49.68 41.16 ;
    END
  END q[245]
  PIN q[246]
    DIRECTION OUTPUT ;
    USE SIGNAL ;
    PORT
      LAYER M4 ;
        RECT  49.596 41.232 49.68 41.256 ;
    END
  END q[246]
  PIN q[247]
    DIRECTION OUTPUT ;
    USE SIGNAL ;
    PORT
      LAYER M4 ;
        RECT  49.596 41.328 49.68 41.352 ;
    END
  END q[247]
  PIN q[248]
    DIRECTION OUTPUT ;
    USE SIGNAL ;
    PORT
      LAYER M4 ;
        RECT  49.596 41.424 49.68 41.448 ;
    END
  END q[248]
  PIN q[249]
    DIRECTION OUTPUT ;
    USE SIGNAL ;
    PORT
      LAYER M4 ;
        RECT  49.596 41.52 49.68 41.544 ;
    END
  END q[249]
  PIN q[24]
    DIRECTION OUTPUT ;
    USE SIGNAL ;
    PORT
      LAYER M4 ;
        RECT  49.596 37.584 49.68 37.608 ;
    END
  END q[24]
  PIN q[250]
    DIRECTION OUTPUT ;
    USE SIGNAL ;
    PORT
      LAYER M4 ;
        RECT  49.596 41.616 49.68 41.64 ;
    END
  END q[250]
  PIN q[251]
    DIRECTION OUTPUT ;
    USE SIGNAL ;
    PORT
      LAYER M4 ;
        RECT  49.596 41.712 49.68 41.736 ;
    END
  END q[251]
  PIN q[252]
    DIRECTION OUTPUT ;
    USE SIGNAL ;
    PORT
      LAYER M4 ;
        RECT  49.596 41.808 49.68 41.832 ;
    END
  END q[252]
  PIN q[253]
    DIRECTION OUTPUT ;
    USE SIGNAL ;
    PORT
      LAYER M4 ;
        RECT  49.596 41.904 49.68 41.928 ;
    END
  END q[253]
  PIN q[254]
    DIRECTION OUTPUT ;
    USE SIGNAL ;
    PORT
      LAYER M4 ;
        RECT  49.596 42 49.68 42.024 ;
    END
  END q[254]
  PIN q[255]
    DIRECTION OUTPUT ;
    USE SIGNAL ;
    PORT
      LAYER M4 ;
        RECT  49.596 42.096 49.68 42.12 ;
    END
  END q[255]
  PIN q[256]
    DIRECTION OUTPUT ;
    USE SIGNAL ;
    PORT
      LAYER M4 ;
        RECT  49.596 6.864 49.68 6.888 ;
    END
  END q[256]
  PIN q[257]
    DIRECTION OUTPUT ;
    USE SIGNAL ;
    PORT
      LAYER M4 ;
        RECT  49.596 6.96 49.68 6.984 ;
    END
  END q[257]
  PIN q[258]
    DIRECTION OUTPUT ;
    USE SIGNAL ;
    PORT
      LAYER M4 ;
        RECT  49.596 7.056 49.68 7.08 ;
    END
  END q[258]
  PIN q[259]
    DIRECTION OUTPUT ;
    USE SIGNAL ;
    PORT
      LAYER M4 ;
        RECT  49.596 7.152 49.68 7.176 ;
    END
  END q[259]
  PIN q[25]
    DIRECTION OUTPUT ;
    USE SIGNAL ;
    PORT
      LAYER M4 ;
        RECT  49.596 37.68 49.68 37.704 ;
    END
  END q[25]
  PIN q[260]
    DIRECTION OUTPUT ;
    USE SIGNAL ;
    PORT
      LAYER M4 ;
        RECT  49.596 7.248 49.68 7.272 ;
    END
  END q[260]
  PIN q[261]
    DIRECTION OUTPUT ;
    USE SIGNAL ;
    PORT
      LAYER M4 ;
        RECT  49.596 7.344 49.68 7.368 ;
    END
  END q[261]
  PIN q[262]
    DIRECTION OUTPUT ;
    USE SIGNAL ;
    PORT
      LAYER M4 ;
        RECT  49.596 7.44 49.68 7.464 ;
    END
  END q[262]
  PIN q[263]
    DIRECTION OUTPUT ;
    USE SIGNAL ;
    PORT
      LAYER M4 ;
        RECT  49.596 7.536 49.68 7.56 ;
    END
  END q[263]
  PIN q[264]
    DIRECTION OUTPUT ;
    USE SIGNAL ;
    PORT
      LAYER M4 ;
        RECT  49.596 7.632 49.68 7.656 ;
    END
  END q[264]
  PIN q[265]
    DIRECTION OUTPUT ;
    USE SIGNAL ;
    PORT
      LAYER M4 ;
        RECT  49.596 7.728 49.68 7.752 ;
    END
  END q[265]
  PIN q[266]
    DIRECTION OUTPUT ;
    USE SIGNAL ;
    PORT
      LAYER M4 ;
        RECT  49.596 7.824 49.68 7.848 ;
    END
  END q[266]
  PIN q[267]
    DIRECTION OUTPUT ;
    USE SIGNAL ;
    PORT
      LAYER M4 ;
        RECT  49.596 7.92 49.68 7.944 ;
    END
  END q[267]
  PIN q[268]
    DIRECTION OUTPUT ;
    USE SIGNAL ;
    PORT
      LAYER M4 ;
        RECT  49.596 8.016 49.68 8.04 ;
    END
  END q[268]
  PIN q[269]
    DIRECTION OUTPUT ;
    USE SIGNAL ;
    PORT
      LAYER M4 ;
        RECT  49.596 8.112 49.68 8.136 ;
    END
  END q[269]
  PIN q[26]
    DIRECTION OUTPUT ;
    USE SIGNAL ;
    PORT
      LAYER M4 ;
        RECT  49.596 37.776 49.68 37.8 ;
    END
  END q[26]
  PIN q[270]
    DIRECTION OUTPUT ;
    USE SIGNAL ;
    PORT
      LAYER M4 ;
        RECT  49.596 8.208 49.68 8.232 ;
    END
  END q[270]
  PIN q[271]
    DIRECTION OUTPUT ;
    USE SIGNAL ;
    PORT
      LAYER M4 ;
        RECT  49.596 8.304 49.68 8.328 ;
    END
  END q[271]
  PIN q[272]
    DIRECTION OUTPUT ;
    USE SIGNAL ;
    PORT
      LAYER M4 ;
        RECT  49.596 8.4 49.68 8.424 ;
    END
  END q[272]
  PIN q[273]
    DIRECTION OUTPUT ;
    USE SIGNAL ;
    PORT
      LAYER M4 ;
        RECT  49.596 8.496 49.68 8.52 ;
    END
  END q[273]
  PIN q[274]
    DIRECTION OUTPUT ;
    USE SIGNAL ;
    PORT
      LAYER M4 ;
        RECT  49.596 8.592 49.68 8.616 ;
    END
  END q[274]
  PIN q[275]
    DIRECTION OUTPUT ;
    USE SIGNAL ;
    PORT
      LAYER M4 ;
        RECT  49.596 8.688 49.68 8.712 ;
    END
  END q[275]
  PIN q[276]
    DIRECTION OUTPUT ;
    USE SIGNAL ;
    PORT
      LAYER M4 ;
        RECT  49.596 8.784 49.68 8.808 ;
    END
  END q[276]
  PIN q[277]
    DIRECTION OUTPUT ;
    USE SIGNAL ;
    PORT
      LAYER M4 ;
        RECT  49.596 8.88 49.68 8.904 ;
    END
  END q[277]
  PIN q[278]
    DIRECTION OUTPUT ;
    USE SIGNAL ;
    PORT
      LAYER M4 ;
        RECT  49.596 8.976 49.68 9 ;
    END
  END q[278]
  PIN q[279]
    DIRECTION OUTPUT ;
    USE SIGNAL ;
    PORT
      LAYER M4 ;
        RECT  49.596 9.072 49.68 9.096 ;
    END
  END q[279]
  PIN q[27]
    DIRECTION OUTPUT ;
    USE SIGNAL ;
    PORT
      LAYER M4 ;
        RECT  49.596 37.872 49.68 37.896 ;
    END
  END q[27]
  PIN q[280]
    DIRECTION OUTPUT ;
    USE SIGNAL ;
    PORT
      LAYER M4 ;
        RECT  49.596 9.168 49.68 9.192 ;
    END
  END q[280]
  PIN q[281]
    DIRECTION OUTPUT ;
    USE SIGNAL ;
    PORT
      LAYER M4 ;
        RECT  49.596 9.264 49.68 9.288 ;
    END
  END q[281]
  PIN q[282]
    DIRECTION OUTPUT ;
    USE SIGNAL ;
    PORT
      LAYER M4 ;
        RECT  49.596 9.36 49.68 9.384 ;
    END
  END q[282]
  PIN q[283]
    DIRECTION OUTPUT ;
    USE SIGNAL ;
    PORT
      LAYER M4 ;
        RECT  49.596 9.456 49.68 9.48 ;
    END
  END q[283]
  PIN q[284]
    DIRECTION OUTPUT ;
    USE SIGNAL ;
    PORT
      LAYER M4 ;
        RECT  49.596 9.552 49.68 9.576 ;
    END
  END q[284]
  PIN q[285]
    DIRECTION OUTPUT ;
    USE SIGNAL ;
    PORT
      LAYER M4 ;
        RECT  49.596 9.648 49.68 9.672 ;
    END
  END q[285]
  PIN q[286]
    DIRECTION OUTPUT ;
    USE SIGNAL ;
    PORT
      LAYER M4 ;
        RECT  49.596 9.744 49.68 9.768 ;
    END
  END q[286]
  PIN q[287]
    DIRECTION OUTPUT ;
    USE SIGNAL ;
    PORT
      LAYER M4 ;
        RECT  49.596 9.84 49.68 9.864 ;
    END
  END q[287]
  PIN q[288]
    DIRECTION OUTPUT ;
    USE SIGNAL ;
    PORT
      LAYER M4 ;
        RECT  49.596 54.48 49.68 54.504 ;
    END
  END q[288]
  PIN q[289]
    DIRECTION OUTPUT ;
    USE SIGNAL ;
    PORT
      LAYER M4 ;
        RECT  49.596 54.576 49.68 54.6 ;
    END
  END q[289]
  PIN q[28]
    DIRECTION OUTPUT ;
    USE SIGNAL ;
    PORT
      LAYER M4 ;
        RECT  49.596 37.968 49.68 37.992 ;
    END
  END q[28]
  PIN q[290]
    DIRECTION OUTPUT ;
    USE SIGNAL ;
    PORT
      LAYER M4 ;
        RECT  49.596 54.672 49.68 54.696 ;
    END
  END q[290]
  PIN q[291]
    DIRECTION OUTPUT ;
    USE SIGNAL ;
    PORT
      LAYER M4 ;
        RECT  49.596 54.768 49.68 54.792 ;
    END
  END q[291]
  PIN q[292]
    DIRECTION OUTPUT ;
    USE SIGNAL ;
    PORT
      LAYER M4 ;
        RECT  49.596 54.864 49.68 54.888 ;
    END
  END q[292]
  PIN q[293]
    DIRECTION OUTPUT ;
    USE SIGNAL ;
    PORT
      LAYER M4 ;
        RECT  49.596 54.96 49.68 54.984 ;
    END
  END q[293]
  PIN q[294]
    DIRECTION OUTPUT ;
    USE SIGNAL ;
    PORT
      LAYER M4 ;
        RECT  49.596 55.056 49.68 55.08 ;
    END
  END q[294]
  PIN q[295]
    DIRECTION OUTPUT ;
    USE SIGNAL ;
    PORT
      LAYER M4 ;
        RECT  49.596 55.152 49.68 55.176 ;
    END
  END q[295]
  PIN q[296]
    DIRECTION OUTPUT ;
    USE SIGNAL ;
    PORT
      LAYER M4 ;
        RECT  49.596 55.248 49.68 55.272 ;
    END
  END q[296]
  PIN q[297]
    DIRECTION OUTPUT ;
    USE SIGNAL ;
    PORT
      LAYER M4 ;
        RECT  49.596 55.344 49.68 55.368 ;
    END
  END q[297]
  PIN q[298]
    DIRECTION OUTPUT ;
    USE SIGNAL ;
    PORT
      LAYER M4 ;
        RECT  49.596 55.44 49.68 55.464 ;
    END
  END q[298]
  PIN q[299]
    DIRECTION OUTPUT ;
    USE SIGNAL ;
    PORT
      LAYER M4 ;
        RECT  49.596 55.536 49.68 55.56 ;
    END
  END q[299]
  PIN q[29]
    DIRECTION OUTPUT ;
    USE SIGNAL ;
    PORT
      LAYER M4 ;
        RECT  49.596 38.064 49.68 38.088 ;
    END
  END q[29]
  PIN q[2]
    DIRECTION OUTPUT ;
    USE SIGNAL ;
    PORT
      LAYER M4 ;
        RECT  49.596 35.472 49.68 35.496 ;
    END
  END q[2]
  PIN q[300]
    DIRECTION OUTPUT ;
    USE SIGNAL ;
    PORT
      LAYER M4 ;
        RECT  49.596 55.632 49.68 55.656 ;
    END
  END q[300]
  PIN q[301]
    DIRECTION OUTPUT ;
    USE SIGNAL ;
    PORT
      LAYER M4 ;
        RECT  49.596 55.728 49.68 55.752 ;
    END
  END q[301]
  PIN q[302]
    DIRECTION OUTPUT ;
    USE SIGNAL ;
    PORT
      LAYER M4 ;
        RECT  49.596 55.824 49.68 55.848 ;
    END
  END q[302]
  PIN q[303]
    DIRECTION OUTPUT ;
    USE SIGNAL ;
    PORT
      LAYER M4 ;
        RECT  49.596 55.92 49.68 55.944 ;
    END
  END q[303]
  PIN q[304]
    DIRECTION OUTPUT ;
    USE SIGNAL ;
    PORT
      LAYER M4 ;
        RECT  49.596 56.016 49.68 56.04 ;
    END
  END q[304]
  PIN q[305]
    DIRECTION OUTPUT ;
    USE SIGNAL ;
    PORT
      LAYER M4 ;
        RECT  49.596 56.112 49.68 56.136 ;
    END
  END q[305]
  PIN q[306]
    DIRECTION OUTPUT ;
    USE SIGNAL ;
    PORT
      LAYER M4 ;
        RECT  49.596 56.208 49.68 56.232 ;
    END
  END q[306]
  PIN q[307]
    DIRECTION OUTPUT ;
    USE SIGNAL ;
    PORT
      LAYER M4 ;
        RECT  49.596 56.304 49.68 56.328 ;
    END
  END q[307]
  PIN q[308]
    DIRECTION OUTPUT ;
    USE SIGNAL ;
    PORT
      LAYER M4 ;
        RECT  49.596 56.4 49.68 56.424 ;
    END
  END q[308]
  PIN q[309]
    DIRECTION OUTPUT ;
    USE SIGNAL ;
    PORT
      LAYER M4 ;
        RECT  49.596 56.496 49.68 56.52 ;
    END
  END q[309]
  PIN q[30]
    DIRECTION OUTPUT ;
    USE SIGNAL ;
    PORT
      LAYER M4 ;
        RECT  49.596 38.16 49.68 38.184 ;
    END
  END q[30]
  PIN q[310]
    DIRECTION OUTPUT ;
    USE SIGNAL ;
    PORT
      LAYER M4 ;
        RECT  49.596 56.592 49.68 56.616 ;
    END
  END q[310]
  PIN q[311]
    DIRECTION OUTPUT ;
    USE SIGNAL ;
    PORT
      LAYER M4 ;
        RECT  49.596 56.688 49.68 56.712 ;
    END
  END q[311]
  PIN q[312]
    DIRECTION OUTPUT ;
    USE SIGNAL ;
    PORT
      LAYER M4 ;
        RECT  49.596 56.784 49.68 56.808 ;
    END
  END q[312]
  PIN q[313]
    DIRECTION OUTPUT ;
    USE SIGNAL ;
    PORT
      LAYER M4 ;
        RECT  49.596 56.88 49.68 56.904 ;
    END
  END q[313]
  PIN q[314]
    DIRECTION OUTPUT ;
    USE SIGNAL ;
    PORT
      LAYER M4 ;
        RECT  49.596 56.976 49.68 57 ;
    END
  END q[314]
  PIN q[315]
    DIRECTION OUTPUT ;
    USE SIGNAL ;
    PORT
      LAYER M4 ;
        RECT  49.596 57.072 49.68 57.096 ;
    END
  END q[315]
  PIN q[316]
    DIRECTION OUTPUT ;
    USE SIGNAL ;
    PORT
      LAYER M4 ;
        RECT  49.596 57.168 49.68 57.192 ;
    END
  END q[316]
  PIN q[317]
    DIRECTION OUTPUT ;
    USE SIGNAL ;
    PORT
      LAYER M4 ;
        RECT  49.596 57.264 49.68 57.288 ;
    END
  END q[317]
  PIN q[318]
    DIRECTION OUTPUT ;
    USE SIGNAL ;
    PORT
      LAYER M4 ;
        RECT  49.596 57.36 49.68 57.384 ;
    END
  END q[318]
  PIN q[319]
    DIRECTION OUTPUT ;
    USE SIGNAL ;
    PORT
      LAYER M4 ;
        RECT  49.596 57.456 49.68 57.48 ;
    END
  END q[319]
  PIN q[31]
    DIRECTION OUTPUT ;
    USE SIGNAL ;
    PORT
      LAYER M4 ;
        RECT  49.596 38.256 49.68 38.28 ;
    END
  END q[31]
  PIN q[320]
    DIRECTION OUTPUT ;
    USE SIGNAL ;
    PORT
      LAYER M4 ;
        RECT  49.596 45.264 49.68 45.288 ;
    END
  END q[320]
  PIN q[321]
    DIRECTION OUTPUT ;
    USE SIGNAL ;
    PORT
      LAYER M4 ;
        RECT  49.596 45.36 49.68 45.384 ;
    END
  END q[321]
  PIN q[322]
    DIRECTION OUTPUT ;
    USE SIGNAL ;
    PORT
      LAYER M4 ;
        RECT  49.596 45.456 49.68 45.48 ;
    END
  END q[322]
  PIN q[323]
    DIRECTION OUTPUT ;
    USE SIGNAL ;
    PORT
      LAYER M4 ;
        RECT  49.596 45.552 49.68 45.576 ;
    END
  END q[323]
  PIN q[324]
    DIRECTION OUTPUT ;
    USE SIGNAL ;
    PORT
      LAYER M4 ;
        RECT  49.596 45.648 49.68 45.672 ;
    END
  END q[324]
  PIN q[325]
    DIRECTION OUTPUT ;
    USE SIGNAL ;
    PORT
      LAYER M4 ;
        RECT  49.596 45.744 49.68 45.768 ;
    END
  END q[325]
  PIN q[326]
    DIRECTION OUTPUT ;
    USE SIGNAL ;
    PORT
      LAYER M4 ;
        RECT  49.596 45.84 49.68 45.864 ;
    END
  END q[326]
  PIN q[327]
    DIRECTION OUTPUT ;
    USE SIGNAL ;
    PORT
      LAYER M4 ;
        RECT  49.596 45.936 49.68 45.96 ;
    END
  END q[327]
  PIN q[328]
    DIRECTION OUTPUT ;
    USE SIGNAL ;
    PORT
      LAYER M4 ;
        RECT  49.596 46.032 49.68 46.056 ;
    END
  END q[328]
  PIN q[329]
    DIRECTION OUTPUT ;
    USE SIGNAL ;
    PORT
      LAYER M4 ;
        RECT  49.596 46.128 49.68 46.152 ;
    END
  END q[329]
  PIN q[32]
    DIRECTION OUTPUT ;
    USE SIGNAL ;
    PORT
      LAYER M4 ;
        RECT  49.596 29.136 49.68 29.16 ;
    END
  END q[32]
  PIN q[330]
    DIRECTION OUTPUT ;
    USE SIGNAL ;
    PORT
      LAYER M4 ;
        RECT  49.596 46.224 49.68 46.248 ;
    END
  END q[330]
  PIN q[331]
    DIRECTION OUTPUT ;
    USE SIGNAL ;
    PORT
      LAYER M4 ;
        RECT  49.596 46.32 49.68 46.344 ;
    END
  END q[331]
  PIN q[332]
    DIRECTION OUTPUT ;
    USE SIGNAL ;
    PORT
      LAYER M4 ;
        RECT  49.596 46.416 49.68 46.44 ;
    END
  END q[332]
  PIN q[333]
    DIRECTION OUTPUT ;
    USE SIGNAL ;
    PORT
      LAYER M4 ;
        RECT  49.596 46.512 49.68 46.536 ;
    END
  END q[333]
  PIN q[334]
    DIRECTION OUTPUT ;
    USE SIGNAL ;
    PORT
      LAYER M4 ;
        RECT  49.596 46.608 49.68 46.632 ;
    END
  END q[334]
  PIN q[335]
    DIRECTION OUTPUT ;
    USE SIGNAL ;
    PORT
      LAYER M4 ;
        RECT  49.596 46.704 49.68 46.728 ;
    END
  END q[335]
  PIN q[336]
    DIRECTION OUTPUT ;
    USE SIGNAL ;
    PORT
      LAYER M4 ;
        RECT  49.596 46.8 49.68 46.824 ;
    END
  END q[336]
  PIN q[337]
    DIRECTION OUTPUT ;
    USE SIGNAL ;
    PORT
      LAYER M4 ;
        RECT  49.596 46.896 49.68 46.92 ;
    END
  END q[337]
  PIN q[338]
    DIRECTION OUTPUT ;
    USE SIGNAL ;
    PORT
      LAYER M4 ;
        RECT  49.596 46.992 49.68 47.016 ;
    END
  END q[338]
  PIN q[339]
    DIRECTION OUTPUT ;
    USE SIGNAL ;
    PORT
      LAYER M4 ;
        RECT  49.596 47.088 49.68 47.112 ;
    END
  END q[339]
  PIN q[33]
    DIRECTION OUTPUT ;
    USE SIGNAL ;
    PORT
      LAYER M4 ;
        RECT  49.596 29.232 49.68 29.256 ;
    END
  END q[33]
  PIN q[340]
    DIRECTION OUTPUT ;
    USE SIGNAL ;
    PORT
      LAYER M4 ;
        RECT  49.596 47.184 49.68 47.208 ;
    END
  END q[340]
  PIN q[341]
    DIRECTION OUTPUT ;
    USE SIGNAL ;
    PORT
      LAYER M4 ;
        RECT  49.596 47.28 49.68 47.304 ;
    END
  END q[341]
  PIN q[342]
    DIRECTION OUTPUT ;
    USE SIGNAL ;
    PORT
      LAYER M4 ;
        RECT  49.596 47.376 49.68 47.4 ;
    END
  END q[342]
  PIN q[343]
    DIRECTION OUTPUT ;
    USE SIGNAL ;
    PORT
      LAYER M4 ;
        RECT  49.596 47.472 49.68 47.496 ;
    END
  END q[343]
  PIN q[344]
    DIRECTION OUTPUT ;
    USE SIGNAL ;
    PORT
      LAYER M4 ;
        RECT  49.596 47.568 49.68 47.592 ;
    END
  END q[344]
  PIN q[345]
    DIRECTION OUTPUT ;
    USE SIGNAL ;
    PORT
      LAYER M4 ;
        RECT  49.596 47.664 49.68 47.688 ;
    END
  END q[345]
  PIN q[346]
    DIRECTION OUTPUT ;
    USE SIGNAL ;
    PORT
      LAYER M4 ;
        RECT  49.596 47.76 49.68 47.784 ;
    END
  END q[346]
  PIN q[347]
    DIRECTION OUTPUT ;
    USE SIGNAL ;
    PORT
      LAYER M4 ;
        RECT  49.596 47.856 49.68 47.88 ;
    END
  END q[347]
  PIN q[348]
    DIRECTION OUTPUT ;
    USE SIGNAL ;
    PORT
      LAYER M4 ;
        RECT  49.596 47.952 49.68 47.976 ;
    END
  END q[348]
  PIN q[349]
    DIRECTION OUTPUT ;
    USE SIGNAL ;
    PORT
      LAYER M4 ;
        RECT  49.596 48.048 49.68 48.072 ;
    END
  END q[349]
  PIN q[34]
    DIRECTION OUTPUT ;
    USE SIGNAL ;
    PORT
      LAYER M4 ;
        RECT  49.596 29.328 49.68 29.352 ;
    END
  END q[34]
  PIN q[350]
    DIRECTION OUTPUT ;
    USE SIGNAL ;
    PORT
      LAYER M4 ;
        RECT  49.596 48.144 49.68 48.168 ;
    END
  END q[350]
  PIN q[351]
    DIRECTION OUTPUT ;
    USE SIGNAL ;
    PORT
      LAYER M4 ;
        RECT  49.596 48.24 49.68 48.264 ;
    END
  END q[351]
  PIN q[352]
    DIRECTION OUTPUT ;
    USE SIGNAL ;
    PORT
      LAYER M4 ;
        RECT  49.596 42.192 49.68 42.216 ;
    END
  END q[352]
  PIN q[353]
    DIRECTION OUTPUT ;
    USE SIGNAL ;
    PORT
      LAYER M4 ;
        RECT  49.596 42.288 49.68 42.312 ;
    END
  END q[353]
  PIN q[354]
    DIRECTION OUTPUT ;
    USE SIGNAL ;
    PORT
      LAYER M4 ;
        RECT  49.596 42.384 49.68 42.408 ;
    END
  END q[354]
  PIN q[355]
    DIRECTION OUTPUT ;
    USE SIGNAL ;
    PORT
      LAYER M4 ;
        RECT  49.596 42.48 49.68 42.504 ;
    END
  END q[355]
  PIN q[356]
    DIRECTION OUTPUT ;
    USE SIGNAL ;
    PORT
      LAYER M4 ;
        RECT  49.596 42.576 49.68 42.6 ;
    END
  END q[356]
  PIN q[357]
    DIRECTION OUTPUT ;
    USE SIGNAL ;
    PORT
      LAYER M4 ;
        RECT  49.596 42.672 49.68 42.696 ;
    END
  END q[357]
  PIN q[358]
    DIRECTION OUTPUT ;
    USE SIGNAL ;
    PORT
      LAYER M4 ;
        RECT  49.596 42.768 49.68 42.792 ;
    END
  END q[358]
  PIN q[359]
    DIRECTION OUTPUT ;
    USE SIGNAL ;
    PORT
      LAYER M4 ;
        RECT  49.596 42.864 49.68 42.888 ;
    END
  END q[359]
  PIN q[35]
    DIRECTION OUTPUT ;
    USE SIGNAL ;
    PORT
      LAYER M4 ;
        RECT  49.596 29.424 49.68 29.448 ;
    END
  END q[35]
  PIN q[360]
    DIRECTION OUTPUT ;
    USE SIGNAL ;
    PORT
      LAYER M4 ;
        RECT  49.596 42.96 49.68 42.984 ;
    END
  END q[360]
  PIN q[361]
    DIRECTION OUTPUT ;
    USE SIGNAL ;
    PORT
      LAYER M4 ;
        RECT  49.596 43.056 49.68 43.08 ;
    END
  END q[361]
  PIN q[362]
    DIRECTION OUTPUT ;
    USE SIGNAL ;
    PORT
      LAYER M4 ;
        RECT  49.596 43.152 49.68 43.176 ;
    END
  END q[362]
  PIN q[363]
    DIRECTION OUTPUT ;
    USE SIGNAL ;
    PORT
      LAYER M4 ;
        RECT  49.596 43.248 49.68 43.272 ;
    END
  END q[363]
  PIN q[364]
    DIRECTION OUTPUT ;
    USE SIGNAL ;
    PORT
      LAYER M4 ;
        RECT  49.596 43.344 49.68 43.368 ;
    END
  END q[364]
  PIN q[365]
    DIRECTION OUTPUT ;
    USE SIGNAL ;
    PORT
      LAYER M4 ;
        RECT  49.596 43.44 49.68 43.464 ;
    END
  END q[365]
  PIN q[366]
    DIRECTION OUTPUT ;
    USE SIGNAL ;
    PORT
      LAYER M4 ;
        RECT  49.596 43.536 49.68 43.56 ;
    END
  END q[366]
  PIN q[367]
    DIRECTION OUTPUT ;
    USE SIGNAL ;
    PORT
      LAYER M4 ;
        RECT  49.596 43.632 49.68 43.656 ;
    END
  END q[367]
  PIN q[368]
    DIRECTION OUTPUT ;
    USE SIGNAL ;
    PORT
      LAYER M4 ;
        RECT  49.596 43.728 49.68 43.752 ;
    END
  END q[368]
  PIN q[369]
    DIRECTION OUTPUT ;
    USE SIGNAL ;
    PORT
      LAYER M4 ;
        RECT  49.596 43.824 49.68 43.848 ;
    END
  END q[369]
  PIN q[36]
    DIRECTION OUTPUT ;
    USE SIGNAL ;
    PORT
      LAYER M4 ;
        RECT  49.596 29.52 49.68 29.544 ;
    END
  END q[36]
  PIN q[370]
    DIRECTION OUTPUT ;
    USE SIGNAL ;
    PORT
      LAYER M4 ;
        RECT  49.596 43.92 49.68 43.944 ;
    END
  END q[370]
  PIN q[371]
    DIRECTION OUTPUT ;
    USE SIGNAL ;
    PORT
      LAYER M4 ;
        RECT  49.596 44.016 49.68 44.04 ;
    END
  END q[371]
  PIN q[372]
    DIRECTION OUTPUT ;
    USE SIGNAL ;
    PORT
      LAYER M4 ;
        RECT  49.596 44.112 49.68 44.136 ;
    END
  END q[372]
  PIN q[373]
    DIRECTION OUTPUT ;
    USE SIGNAL ;
    PORT
      LAYER M4 ;
        RECT  49.596 44.208 49.68 44.232 ;
    END
  END q[373]
  PIN q[374]
    DIRECTION OUTPUT ;
    USE SIGNAL ;
    PORT
      LAYER M4 ;
        RECT  49.596 44.304 49.68 44.328 ;
    END
  END q[374]
  PIN q[375]
    DIRECTION OUTPUT ;
    USE SIGNAL ;
    PORT
      LAYER M4 ;
        RECT  49.596 44.4 49.68 44.424 ;
    END
  END q[375]
  PIN q[376]
    DIRECTION OUTPUT ;
    USE SIGNAL ;
    PORT
      LAYER M4 ;
        RECT  49.596 44.496 49.68 44.52 ;
    END
  END q[376]
  PIN q[377]
    DIRECTION OUTPUT ;
    USE SIGNAL ;
    PORT
      LAYER M4 ;
        RECT  49.596 44.592 49.68 44.616 ;
    END
  END q[377]
  PIN q[378]
    DIRECTION OUTPUT ;
    USE SIGNAL ;
    PORT
      LAYER M4 ;
        RECT  49.596 44.688 49.68 44.712 ;
    END
  END q[378]
  PIN q[379]
    DIRECTION OUTPUT ;
    USE SIGNAL ;
    PORT
      LAYER M4 ;
        RECT  49.596 44.784 49.68 44.808 ;
    END
  END q[379]
  PIN q[37]
    DIRECTION OUTPUT ;
    USE SIGNAL ;
    PORT
      LAYER M4 ;
        RECT  49.596 29.616 49.68 29.64 ;
    END
  END q[37]
  PIN q[380]
    DIRECTION OUTPUT ;
    USE SIGNAL ;
    PORT
      LAYER M4 ;
        RECT  49.596 44.88 49.68 44.904 ;
    END
  END q[380]
  PIN q[381]
    DIRECTION OUTPUT ;
    USE SIGNAL ;
    PORT
      LAYER M4 ;
        RECT  49.596 44.976 49.68 45 ;
    END
  END q[381]
  PIN q[382]
    DIRECTION OUTPUT ;
    USE SIGNAL ;
    PORT
      LAYER M4 ;
        RECT  49.596 45.072 49.68 45.096 ;
    END
  END q[382]
  PIN q[383]
    DIRECTION OUTPUT ;
    USE SIGNAL ;
    PORT
      LAYER M4 ;
        RECT  49.596 45.168 49.68 45.192 ;
    END
  END q[383]
  PIN q[384]
    DIRECTION OUTPUT ;
    USE SIGNAL ;
    PORT
      LAYER M4 ;
        RECT  49.596 51.408 49.68 51.432 ;
    END
  END q[384]
  PIN q[385]
    DIRECTION OUTPUT ;
    USE SIGNAL ;
    PORT
      LAYER M4 ;
        RECT  49.596 51.504 49.68 51.528 ;
    END
  END q[385]
  PIN q[386]
    DIRECTION OUTPUT ;
    USE SIGNAL ;
    PORT
      LAYER M4 ;
        RECT  49.596 51.6 49.68 51.624 ;
    END
  END q[386]
  PIN q[387]
    DIRECTION OUTPUT ;
    USE SIGNAL ;
    PORT
      LAYER M4 ;
        RECT  49.596 51.696 49.68 51.72 ;
    END
  END q[387]
  PIN q[388]
    DIRECTION OUTPUT ;
    USE SIGNAL ;
    PORT
      LAYER M4 ;
        RECT  49.596 51.792 49.68 51.816 ;
    END
  END q[388]
  PIN q[389]
    DIRECTION OUTPUT ;
    USE SIGNAL ;
    PORT
      LAYER M4 ;
        RECT  49.596 51.888 49.68 51.912 ;
    END
  END q[389]
  PIN q[38]
    DIRECTION OUTPUT ;
    USE SIGNAL ;
    PORT
      LAYER M4 ;
        RECT  49.596 29.712 49.68 29.736 ;
    END
  END q[38]
  PIN q[390]
    DIRECTION OUTPUT ;
    USE SIGNAL ;
    PORT
      LAYER M4 ;
        RECT  49.596 51.984 49.68 52.008 ;
    END
  END q[390]
  PIN q[391]
    DIRECTION OUTPUT ;
    USE SIGNAL ;
    PORT
      LAYER M4 ;
        RECT  49.596 52.08 49.68 52.104 ;
    END
  END q[391]
  PIN q[392]
    DIRECTION OUTPUT ;
    USE SIGNAL ;
    PORT
      LAYER M4 ;
        RECT  49.596 52.176 49.68 52.2 ;
    END
  END q[392]
  PIN q[393]
    DIRECTION OUTPUT ;
    USE SIGNAL ;
    PORT
      LAYER M4 ;
        RECT  49.596 52.272 49.68 52.296 ;
    END
  END q[393]
  PIN q[394]
    DIRECTION OUTPUT ;
    USE SIGNAL ;
    PORT
      LAYER M4 ;
        RECT  49.596 52.368 49.68 52.392 ;
    END
  END q[394]
  PIN q[395]
    DIRECTION OUTPUT ;
    USE SIGNAL ;
    PORT
      LAYER M4 ;
        RECT  49.596 52.464 49.68 52.488 ;
    END
  END q[395]
  PIN q[396]
    DIRECTION OUTPUT ;
    USE SIGNAL ;
    PORT
      LAYER M4 ;
        RECT  49.596 52.56 49.68 52.584 ;
    END
  END q[396]
  PIN q[397]
    DIRECTION OUTPUT ;
    USE SIGNAL ;
    PORT
      LAYER M4 ;
        RECT  49.596 52.656 49.68 52.68 ;
    END
  END q[397]
  PIN q[398]
    DIRECTION OUTPUT ;
    USE SIGNAL ;
    PORT
      LAYER M4 ;
        RECT  49.596 52.752 49.68 52.776 ;
    END
  END q[398]
  PIN q[399]
    DIRECTION OUTPUT ;
    USE SIGNAL ;
    PORT
      LAYER M4 ;
        RECT  49.596 52.848 49.68 52.872 ;
    END
  END q[399]
  PIN q[39]
    DIRECTION OUTPUT ;
    USE SIGNAL ;
    PORT
      LAYER M4 ;
        RECT  49.596 29.808 49.68 29.832 ;
    END
  END q[39]
  PIN q[3]
    DIRECTION OUTPUT ;
    USE SIGNAL ;
    PORT
      LAYER M4 ;
        RECT  49.596 35.568 49.68 35.592 ;
    END
  END q[3]
  PIN q[400]
    DIRECTION OUTPUT ;
    USE SIGNAL ;
    PORT
      LAYER M4 ;
        RECT  49.596 52.944 49.68 52.968 ;
    END
  END q[400]
  PIN q[401]
    DIRECTION OUTPUT ;
    USE SIGNAL ;
    PORT
      LAYER M4 ;
        RECT  49.596 53.04 49.68 53.064 ;
    END
  END q[401]
  PIN q[402]
    DIRECTION OUTPUT ;
    USE SIGNAL ;
    PORT
      LAYER M4 ;
        RECT  49.596 53.136 49.68 53.16 ;
    END
  END q[402]
  PIN q[403]
    DIRECTION OUTPUT ;
    USE SIGNAL ;
    PORT
      LAYER M4 ;
        RECT  49.596 53.232 49.68 53.256 ;
    END
  END q[403]
  PIN q[404]
    DIRECTION OUTPUT ;
    USE SIGNAL ;
    PORT
      LAYER M4 ;
        RECT  49.596 53.328 49.68 53.352 ;
    END
  END q[404]
  PIN q[405]
    DIRECTION OUTPUT ;
    USE SIGNAL ;
    PORT
      LAYER M4 ;
        RECT  49.596 53.424 49.68 53.448 ;
    END
  END q[405]
  PIN q[406]
    DIRECTION OUTPUT ;
    USE SIGNAL ;
    PORT
      LAYER M4 ;
        RECT  49.596 53.52 49.68 53.544 ;
    END
  END q[406]
  PIN q[407]
    DIRECTION OUTPUT ;
    USE SIGNAL ;
    PORT
      LAYER M4 ;
        RECT  49.596 53.616 49.68 53.64 ;
    END
  END q[407]
  PIN q[408]
    DIRECTION OUTPUT ;
    USE SIGNAL ;
    PORT
      LAYER M4 ;
        RECT  49.596 53.712 49.68 53.736 ;
    END
  END q[408]
  PIN q[409]
    DIRECTION OUTPUT ;
    USE SIGNAL ;
    PORT
      LAYER M4 ;
        RECT  49.596 53.808 49.68 53.832 ;
    END
  END q[409]
  PIN q[40]
    DIRECTION OUTPUT ;
    USE SIGNAL ;
    PORT
      LAYER M4 ;
        RECT  49.596 29.904 49.68 29.928 ;
    END
  END q[40]
  PIN q[410]
    DIRECTION OUTPUT ;
    USE SIGNAL ;
    PORT
      LAYER M4 ;
        RECT  49.596 53.904 49.68 53.928 ;
    END
  END q[410]
  PIN q[411]
    DIRECTION OUTPUT ;
    USE SIGNAL ;
    PORT
      LAYER M4 ;
        RECT  49.596 54 49.68 54.024 ;
    END
  END q[411]
  PIN q[412]
    DIRECTION OUTPUT ;
    USE SIGNAL ;
    PORT
      LAYER M4 ;
        RECT  49.596 54.096 49.68 54.12 ;
    END
  END q[412]
  PIN q[413]
    DIRECTION OUTPUT ;
    USE SIGNAL ;
    PORT
      LAYER M4 ;
        RECT  49.596 54.192 49.68 54.216 ;
    END
  END q[413]
  PIN q[414]
    DIRECTION OUTPUT ;
    USE SIGNAL ;
    PORT
      LAYER M4 ;
        RECT  49.596 54.288 49.68 54.312 ;
    END
  END q[414]
  PIN q[415]
    DIRECTION OUTPUT ;
    USE SIGNAL ;
    PORT
      LAYER M4 ;
        RECT  49.596 54.384 49.68 54.408 ;
    END
  END q[415]
  PIN q[416]
    DIRECTION OUTPUT ;
    USE SIGNAL ;
    PORT
      LAYER M4 ;
        RECT  49.596 16.08 49.68 16.104 ;
    END
  END q[416]
  PIN q[417]
    DIRECTION OUTPUT ;
    USE SIGNAL ;
    PORT
      LAYER M4 ;
        RECT  49.596 16.176 49.68 16.2 ;
    END
  END q[417]
  PIN q[418]
    DIRECTION OUTPUT ;
    USE SIGNAL ;
    PORT
      LAYER M4 ;
        RECT  49.596 16.272 49.68 16.296 ;
    END
  END q[418]
  PIN q[419]
    DIRECTION OUTPUT ;
    USE SIGNAL ;
    PORT
      LAYER M4 ;
        RECT  49.596 16.368 49.68 16.392 ;
    END
  END q[419]
  PIN q[41]
    DIRECTION OUTPUT ;
    USE SIGNAL ;
    PORT
      LAYER M4 ;
        RECT  49.596 30 49.68 30.024 ;
    END
  END q[41]
  PIN q[420]
    DIRECTION OUTPUT ;
    USE SIGNAL ;
    PORT
      LAYER M4 ;
        RECT  49.596 16.464 49.68 16.488 ;
    END
  END q[420]
  PIN q[421]
    DIRECTION OUTPUT ;
    USE SIGNAL ;
    PORT
      LAYER M4 ;
        RECT  49.596 16.56 49.68 16.584 ;
    END
  END q[421]
  PIN q[422]
    DIRECTION OUTPUT ;
    USE SIGNAL ;
    PORT
      LAYER M4 ;
        RECT  49.596 16.656 49.68 16.68 ;
    END
  END q[422]
  PIN q[423]
    DIRECTION OUTPUT ;
    USE SIGNAL ;
    PORT
      LAYER M4 ;
        RECT  49.596 16.752 49.68 16.776 ;
    END
  END q[423]
  PIN q[424]
    DIRECTION OUTPUT ;
    USE SIGNAL ;
    PORT
      LAYER M4 ;
        RECT  49.596 16.848 49.68 16.872 ;
    END
  END q[424]
  PIN q[425]
    DIRECTION OUTPUT ;
    USE SIGNAL ;
    PORT
      LAYER M4 ;
        RECT  49.596 16.944 49.68 16.968 ;
    END
  END q[425]
  PIN q[426]
    DIRECTION OUTPUT ;
    USE SIGNAL ;
    PORT
      LAYER M4 ;
        RECT  49.596 17.04 49.68 17.064 ;
    END
  END q[426]
  PIN q[427]
    DIRECTION OUTPUT ;
    USE SIGNAL ;
    PORT
      LAYER M4 ;
        RECT  49.596 17.136 49.68 17.16 ;
    END
  END q[427]
  PIN q[428]
    DIRECTION OUTPUT ;
    USE SIGNAL ;
    PORT
      LAYER M4 ;
        RECT  49.596 17.232 49.68 17.256 ;
    END
  END q[428]
  PIN q[429]
    DIRECTION OUTPUT ;
    USE SIGNAL ;
    PORT
      LAYER M4 ;
        RECT  49.596 17.328 49.68 17.352 ;
    END
  END q[429]
  PIN q[42]
    DIRECTION OUTPUT ;
    USE SIGNAL ;
    PORT
      LAYER M4 ;
        RECT  49.596 30.096 49.68 30.12 ;
    END
  END q[42]
  PIN q[430]
    DIRECTION OUTPUT ;
    USE SIGNAL ;
    PORT
      LAYER M4 ;
        RECT  49.596 17.424 49.68 17.448 ;
    END
  END q[430]
  PIN q[431]
    DIRECTION OUTPUT ;
    USE SIGNAL ;
    PORT
      LAYER M4 ;
        RECT  49.596 17.52 49.68 17.544 ;
    END
  END q[431]
  PIN q[432]
    DIRECTION OUTPUT ;
    USE SIGNAL ;
    PORT
      LAYER M4 ;
        RECT  49.596 17.616 49.68 17.64 ;
    END
  END q[432]
  PIN q[433]
    DIRECTION OUTPUT ;
    USE SIGNAL ;
    PORT
      LAYER M4 ;
        RECT  49.596 17.712 49.68 17.736 ;
    END
  END q[433]
  PIN q[434]
    DIRECTION OUTPUT ;
    USE SIGNAL ;
    PORT
      LAYER M4 ;
        RECT  49.596 17.808 49.68 17.832 ;
    END
  END q[434]
  PIN q[435]
    DIRECTION OUTPUT ;
    USE SIGNAL ;
    PORT
      LAYER M4 ;
        RECT  49.596 17.904 49.68 17.928 ;
    END
  END q[435]
  PIN q[436]
    DIRECTION OUTPUT ;
    USE SIGNAL ;
    PORT
      LAYER M4 ;
        RECT  49.596 18 49.68 18.024 ;
    END
  END q[436]
  PIN q[437]
    DIRECTION OUTPUT ;
    USE SIGNAL ;
    PORT
      LAYER M4 ;
        RECT  49.596 18.096 49.68 18.12 ;
    END
  END q[437]
  PIN q[438]
    DIRECTION OUTPUT ;
    USE SIGNAL ;
    PORT
      LAYER M4 ;
        RECT  49.596 18.192 49.68 18.216 ;
    END
  END q[438]
  PIN q[439]
    DIRECTION OUTPUT ;
    USE SIGNAL ;
    PORT
      LAYER M4 ;
        RECT  49.596 18.288 49.68 18.312 ;
    END
  END q[439]
  PIN q[43]
    DIRECTION OUTPUT ;
    USE SIGNAL ;
    PORT
      LAYER M4 ;
        RECT  49.596 30.192 49.68 30.216 ;
    END
  END q[43]
  PIN q[440]
    DIRECTION OUTPUT ;
    USE SIGNAL ;
    PORT
      LAYER M4 ;
        RECT  49.596 18.384 49.68 18.408 ;
    END
  END q[440]
  PIN q[441]
    DIRECTION OUTPUT ;
    USE SIGNAL ;
    PORT
      LAYER M4 ;
        RECT  49.596 18.48 49.68 18.504 ;
    END
  END q[441]
  PIN q[442]
    DIRECTION OUTPUT ;
    USE SIGNAL ;
    PORT
      LAYER M4 ;
        RECT  49.596 18.576 49.68 18.6 ;
    END
  END q[442]
  PIN q[443]
    DIRECTION OUTPUT ;
    USE SIGNAL ;
    PORT
      LAYER M4 ;
        RECT  49.596 18.672 49.68 18.696 ;
    END
  END q[443]
  PIN q[444]
    DIRECTION OUTPUT ;
    USE SIGNAL ;
    PORT
      LAYER M4 ;
        RECT  49.596 18.768 49.68 18.792 ;
    END
  END q[444]
  PIN q[445]
    DIRECTION OUTPUT ;
    USE SIGNAL ;
    PORT
      LAYER M4 ;
        RECT  49.596 18.864 49.68 18.888 ;
    END
  END q[445]
  PIN q[446]
    DIRECTION OUTPUT ;
    USE SIGNAL ;
    PORT
      LAYER M4 ;
        RECT  49.596 18.96 49.68 18.984 ;
    END
  END q[446]
  PIN q[447]
    DIRECTION OUTPUT ;
    USE SIGNAL ;
    PORT
      LAYER M4 ;
        RECT  49.596 19.056 49.68 19.08 ;
    END
  END q[447]
  PIN q[448]
    DIRECTION OUTPUT ;
    USE SIGNAL ;
    PORT
      LAYER M4 ;
        RECT  49.596 9.936 49.68 9.96 ;
    END
  END q[448]
  PIN q[449]
    DIRECTION OUTPUT ;
    USE SIGNAL ;
    PORT
      LAYER M4 ;
        RECT  49.596 10.032 49.68 10.056 ;
    END
  END q[449]
  PIN q[44]
    DIRECTION OUTPUT ;
    USE SIGNAL ;
    PORT
      LAYER M4 ;
        RECT  49.596 30.288 49.68 30.312 ;
    END
  END q[44]
  PIN q[450]
    DIRECTION OUTPUT ;
    USE SIGNAL ;
    PORT
      LAYER M4 ;
        RECT  49.596 10.128 49.68 10.152 ;
    END
  END q[450]
  PIN q[451]
    DIRECTION OUTPUT ;
    USE SIGNAL ;
    PORT
      LAYER M4 ;
        RECT  49.596 10.224 49.68 10.248 ;
    END
  END q[451]
  PIN q[452]
    DIRECTION OUTPUT ;
    USE SIGNAL ;
    PORT
      LAYER M4 ;
        RECT  49.596 10.32 49.68 10.344 ;
    END
  END q[452]
  PIN q[453]
    DIRECTION OUTPUT ;
    USE SIGNAL ;
    PORT
      LAYER M4 ;
        RECT  49.596 10.416 49.68 10.44 ;
    END
  END q[453]
  PIN q[454]
    DIRECTION OUTPUT ;
    USE SIGNAL ;
    PORT
      LAYER M4 ;
        RECT  49.596 10.512 49.68 10.536 ;
    END
  END q[454]
  PIN q[455]
    DIRECTION OUTPUT ;
    USE SIGNAL ;
    PORT
      LAYER M4 ;
        RECT  49.596 10.608 49.68 10.632 ;
    END
  END q[455]
  PIN q[456]
    DIRECTION OUTPUT ;
    USE SIGNAL ;
    PORT
      LAYER M4 ;
        RECT  49.596 10.704 49.68 10.728 ;
    END
  END q[456]
  PIN q[457]
    DIRECTION OUTPUT ;
    USE SIGNAL ;
    PORT
      LAYER M4 ;
        RECT  49.596 10.8 49.68 10.824 ;
    END
  END q[457]
  PIN q[458]
    DIRECTION OUTPUT ;
    USE SIGNAL ;
    PORT
      LAYER M4 ;
        RECT  49.596 10.896 49.68 10.92 ;
    END
  END q[458]
  PIN q[459]
    DIRECTION OUTPUT ;
    USE SIGNAL ;
    PORT
      LAYER M4 ;
        RECT  49.596 10.992 49.68 11.016 ;
    END
  END q[459]
  PIN q[45]
    DIRECTION OUTPUT ;
    USE SIGNAL ;
    PORT
      LAYER M4 ;
        RECT  49.596 30.384 49.68 30.408 ;
    END
  END q[45]
  PIN q[460]
    DIRECTION OUTPUT ;
    USE SIGNAL ;
    PORT
      LAYER M4 ;
        RECT  49.596 11.088 49.68 11.112 ;
    END
  END q[460]
  PIN q[461]
    DIRECTION OUTPUT ;
    USE SIGNAL ;
    PORT
      LAYER M4 ;
        RECT  49.596 11.184 49.68 11.208 ;
    END
  END q[461]
  PIN q[462]
    DIRECTION OUTPUT ;
    USE SIGNAL ;
    PORT
      LAYER M4 ;
        RECT  49.596 11.28 49.68 11.304 ;
    END
  END q[462]
  PIN q[463]
    DIRECTION OUTPUT ;
    USE SIGNAL ;
    PORT
      LAYER M4 ;
        RECT  49.596 11.376 49.68 11.4 ;
    END
  END q[463]
  PIN q[464]
    DIRECTION OUTPUT ;
    USE SIGNAL ;
    PORT
      LAYER M4 ;
        RECT  49.596 11.472 49.68 11.496 ;
    END
  END q[464]
  PIN q[465]
    DIRECTION OUTPUT ;
    USE SIGNAL ;
    PORT
      LAYER M4 ;
        RECT  49.596 11.568 49.68 11.592 ;
    END
  END q[465]
  PIN q[466]
    DIRECTION OUTPUT ;
    USE SIGNAL ;
    PORT
      LAYER M4 ;
        RECT  49.596 11.664 49.68 11.688 ;
    END
  END q[466]
  PIN q[467]
    DIRECTION OUTPUT ;
    USE SIGNAL ;
    PORT
      LAYER M4 ;
        RECT  49.596 11.76 49.68 11.784 ;
    END
  END q[467]
  PIN q[468]
    DIRECTION OUTPUT ;
    USE SIGNAL ;
    PORT
      LAYER M4 ;
        RECT  49.596 11.856 49.68 11.88 ;
    END
  END q[468]
  PIN q[469]
    DIRECTION OUTPUT ;
    USE SIGNAL ;
    PORT
      LAYER M4 ;
        RECT  49.596 11.952 49.68 11.976 ;
    END
  END q[469]
  PIN q[46]
    DIRECTION OUTPUT ;
    USE SIGNAL ;
    PORT
      LAYER M4 ;
        RECT  49.596 30.48 49.68 30.504 ;
    END
  END q[46]
  PIN q[470]
    DIRECTION OUTPUT ;
    USE SIGNAL ;
    PORT
      LAYER M4 ;
        RECT  49.596 12.048 49.68 12.072 ;
    END
  END q[470]
  PIN q[471]
    DIRECTION OUTPUT ;
    USE SIGNAL ;
    PORT
      LAYER M4 ;
        RECT  49.596 12.144 49.68 12.168 ;
    END
  END q[471]
  PIN q[472]
    DIRECTION OUTPUT ;
    USE SIGNAL ;
    PORT
      LAYER M4 ;
        RECT  49.596 12.24 49.68 12.264 ;
    END
  END q[472]
  PIN q[473]
    DIRECTION OUTPUT ;
    USE SIGNAL ;
    PORT
      LAYER M4 ;
        RECT  49.596 12.336 49.68 12.36 ;
    END
  END q[473]
  PIN q[474]
    DIRECTION OUTPUT ;
    USE SIGNAL ;
    PORT
      LAYER M4 ;
        RECT  49.596 12.432 49.68 12.456 ;
    END
  END q[474]
  PIN q[475]
    DIRECTION OUTPUT ;
    USE SIGNAL ;
    PORT
      LAYER M4 ;
        RECT  49.596 12.528 49.68 12.552 ;
    END
  END q[475]
  PIN q[476]
    DIRECTION OUTPUT ;
    USE SIGNAL ;
    PORT
      LAYER M4 ;
        RECT  49.596 12.624 49.68 12.648 ;
    END
  END q[476]
  PIN q[477]
    DIRECTION OUTPUT ;
    USE SIGNAL ;
    PORT
      LAYER M4 ;
        RECT  49.596 12.72 49.68 12.744 ;
    END
  END q[477]
  PIN q[478]
    DIRECTION OUTPUT ;
    USE SIGNAL ;
    PORT
      LAYER M4 ;
        RECT  49.596 12.816 49.68 12.84 ;
    END
  END q[478]
  PIN q[479]
    DIRECTION OUTPUT ;
    USE SIGNAL ;
    PORT
      LAYER M4 ;
        RECT  49.596 12.912 49.68 12.936 ;
    END
  END q[479]
  PIN q[47]
    DIRECTION OUTPUT ;
    USE SIGNAL ;
    PORT
      LAYER M4 ;
        RECT  49.596 30.576 49.68 30.6 ;
    END
  END q[47]
  PIN q[480]
    DIRECTION OUTPUT ;
    USE SIGNAL ;
    PORT
      LAYER M4 ;
        RECT  49.596 13.008 49.68 13.032 ;
    END
  END q[480]
  PIN q[481]
    DIRECTION OUTPUT ;
    USE SIGNAL ;
    PORT
      LAYER M4 ;
        RECT  49.596 13.104 49.68 13.128 ;
    END
  END q[481]
  PIN q[482]
    DIRECTION OUTPUT ;
    USE SIGNAL ;
    PORT
      LAYER M4 ;
        RECT  49.596 13.2 49.68 13.224 ;
    END
  END q[482]
  PIN q[483]
    DIRECTION OUTPUT ;
    USE SIGNAL ;
    PORT
      LAYER M4 ;
        RECT  49.596 13.296 49.68 13.32 ;
    END
  END q[483]
  PIN q[484]
    DIRECTION OUTPUT ;
    USE SIGNAL ;
    PORT
      LAYER M4 ;
        RECT  49.596 13.392 49.68 13.416 ;
    END
  END q[484]
  PIN q[485]
    DIRECTION OUTPUT ;
    USE SIGNAL ;
    PORT
      LAYER M4 ;
        RECT  49.596 13.488 49.68 13.512 ;
    END
  END q[485]
  PIN q[486]
    DIRECTION OUTPUT ;
    USE SIGNAL ;
    PORT
      LAYER M4 ;
        RECT  49.596 13.584 49.68 13.608 ;
    END
  END q[486]
  PIN q[487]
    DIRECTION OUTPUT ;
    USE SIGNAL ;
    PORT
      LAYER M4 ;
        RECT  49.596 13.68 49.68 13.704 ;
    END
  END q[487]
  PIN q[488]
    DIRECTION OUTPUT ;
    USE SIGNAL ;
    PORT
      LAYER M4 ;
        RECT  49.596 13.776 49.68 13.8 ;
    END
  END q[488]
  PIN q[489]
    DIRECTION OUTPUT ;
    USE SIGNAL ;
    PORT
      LAYER M4 ;
        RECT  49.596 13.872 49.68 13.896 ;
    END
  END q[489]
  PIN q[48]
    DIRECTION OUTPUT ;
    USE SIGNAL ;
    PORT
      LAYER M4 ;
        RECT  49.596 30.672 49.68 30.696 ;
    END
  END q[48]
  PIN q[490]
    DIRECTION OUTPUT ;
    USE SIGNAL ;
    PORT
      LAYER M4 ;
        RECT  49.596 13.968 49.68 13.992 ;
    END
  END q[490]
  PIN q[491]
    DIRECTION OUTPUT ;
    USE SIGNAL ;
    PORT
      LAYER M4 ;
        RECT  49.596 14.064 49.68 14.088 ;
    END
  END q[491]
  PIN q[492]
    DIRECTION OUTPUT ;
    USE SIGNAL ;
    PORT
      LAYER M4 ;
        RECT  49.596 14.16 49.68 14.184 ;
    END
  END q[492]
  PIN q[493]
    DIRECTION OUTPUT ;
    USE SIGNAL ;
    PORT
      LAYER M4 ;
        RECT  49.596 14.256 49.68 14.28 ;
    END
  END q[493]
  PIN q[494]
    DIRECTION OUTPUT ;
    USE SIGNAL ;
    PORT
      LAYER M4 ;
        RECT  49.596 14.352 49.68 14.376 ;
    END
  END q[494]
  PIN q[495]
    DIRECTION OUTPUT ;
    USE SIGNAL ;
    PORT
      LAYER M4 ;
        RECT  49.596 14.448 49.68 14.472 ;
    END
  END q[495]
  PIN q[496]
    DIRECTION OUTPUT ;
    USE SIGNAL ;
    PORT
      LAYER M4 ;
        RECT  49.596 14.544 49.68 14.568 ;
    END
  END q[496]
  PIN q[497]
    DIRECTION OUTPUT ;
    USE SIGNAL ;
    PORT
      LAYER M4 ;
        RECT  49.596 14.64 49.68 14.664 ;
    END
  END q[497]
  PIN q[498]
    DIRECTION OUTPUT ;
    USE SIGNAL ;
    PORT
      LAYER M4 ;
        RECT  49.596 14.736 49.68 14.76 ;
    END
  END q[498]
  PIN q[499]
    DIRECTION OUTPUT ;
    USE SIGNAL ;
    PORT
      LAYER M4 ;
        RECT  49.596 14.832 49.68 14.856 ;
    END
  END q[499]
  PIN q[49]
    DIRECTION OUTPUT ;
    USE SIGNAL ;
    PORT
      LAYER M4 ;
        RECT  49.596 30.768 49.68 30.792 ;
    END
  END q[49]
  PIN q[4]
    DIRECTION OUTPUT ;
    USE SIGNAL ;
    PORT
      LAYER M4 ;
        RECT  49.596 35.664 49.68 35.688 ;
    END
  END q[4]
  PIN q[500]
    DIRECTION OUTPUT ;
    USE SIGNAL ;
    PORT
      LAYER M4 ;
        RECT  49.596 14.928 49.68 14.952 ;
    END
  END q[500]
  PIN q[501]
    DIRECTION OUTPUT ;
    USE SIGNAL ;
    PORT
      LAYER M4 ;
        RECT  49.596 15.024 49.68 15.048 ;
    END
  END q[501]
  PIN q[502]
    DIRECTION OUTPUT ;
    USE SIGNAL ;
    PORT
      LAYER M4 ;
        RECT  49.596 15.12 49.68 15.144 ;
    END
  END q[502]
  PIN q[503]
    DIRECTION OUTPUT ;
    USE SIGNAL ;
    PORT
      LAYER M4 ;
        RECT  49.596 15.216 49.68 15.24 ;
    END
  END q[503]
  PIN q[504]
    DIRECTION OUTPUT ;
    USE SIGNAL ;
    PORT
      LAYER M4 ;
        RECT  49.596 15.312 49.68 15.336 ;
    END
  END q[504]
  PIN q[505]
    DIRECTION OUTPUT ;
    USE SIGNAL ;
    PORT
      LAYER M4 ;
        RECT  49.596 15.408 49.68 15.432 ;
    END
  END q[505]
  PIN q[506]
    DIRECTION OUTPUT ;
    USE SIGNAL ;
    PORT
      LAYER M4 ;
        RECT  49.596 15.504 49.68 15.528 ;
    END
  END q[506]
  PIN q[507]
    DIRECTION OUTPUT ;
    USE SIGNAL ;
    PORT
      LAYER M4 ;
        RECT  49.596 15.6 49.68 15.624 ;
    END
  END q[507]
  PIN q[508]
    DIRECTION OUTPUT ;
    USE SIGNAL ;
    PORT
      LAYER M4 ;
        RECT  49.596 15.696 49.68 15.72 ;
    END
  END q[508]
  PIN q[509]
    DIRECTION OUTPUT ;
    USE SIGNAL ;
    PORT
      LAYER M4 ;
        RECT  49.596 15.792 49.68 15.816 ;
    END
  END q[509]
  PIN q[50]
    DIRECTION OUTPUT ;
    USE SIGNAL ;
    PORT
      LAYER M4 ;
        RECT  49.596 30.864 49.68 30.888 ;
    END
  END q[50]
  PIN q[510]
    DIRECTION OUTPUT ;
    USE SIGNAL ;
    PORT
      LAYER M4 ;
        RECT  49.596 15.888 49.68 15.912 ;
    END
  END q[510]
  PIN q[511]
    DIRECTION OUTPUT ;
    USE SIGNAL ;
    PORT
      LAYER M4 ;
        RECT  49.596 15.984 49.68 16.008 ;
    END
  END q[511]
  PIN q[51]
    DIRECTION OUTPUT ;
    USE SIGNAL ;
    PORT
      LAYER M4 ;
        RECT  49.596 30.96 49.68 30.984 ;
    END
  END q[51]
  PIN q[52]
    DIRECTION OUTPUT ;
    USE SIGNAL ;
    PORT
      LAYER M4 ;
        RECT  49.596 31.056 49.68 31.08 ;
    END
  END q[52]
  PIN q[53]
    DIRECTION OUTPUT ;
    USE SIGNAL ;
    PORT
      LAYER M4 ;
        RECT  49.596 31.152 49.68 31.176 ;
    END
  END q[53]
  PIN q[54]
    DIRECTION OUTPUT ;
    USE SIGNAL ;
    PORT
      LAYER M4 ;
        RECT  49.596 31.248 49.68 31.272 ;
    END
  END q[54]
  PIN q[55]
    DIRECTION OUTPUT ;
    USE SIGNAL ;
    PORT
      LAYER M4 ;
        RECT  49.596 31.344 49.68 31.368 ;
    END
  END q[55]
  PIN q[56]
    DIRECTION OUTPUT ;
    USE SIGNAL ;
    PORT
      LAYER M4 ;
        RECT  49.596 31.44 49.68 31.464 ;
    END
  END q[56]
  PIN q[57]
    DIRECTION OUTPUT ;
    USE SIGNAL ;
    PORT
      LAYER M4 ;
        RECT  49.596 31.536 49.68 31.56 ;
    END
  END q[57]
  PIN q[58]
    DIRECTION OUTPUT ;
    USE SIGNAL ;
    PORT
      LAYER M4 ;
        RECT  49.596 31.632 49.68 31.656 ;
    END
  END q[58]
  PIN q[59]
    DIRECTION OUTPUT ;
    USE SIGNAL ;
    PORT
      LAYER M4 ;
        RECT  49.596 31.728 49.68 31.752 ;
    END
  END q[59]
  PIN q[5]
    DIRECTION OUTPUT ;
    USE SIGNAL ;
    PORT
      LAYER M4 ;
        RECT  49.596 35.76 49.68 35.784 ;
    END
  END q[5]
  PIN q[60]
    DIRECTION OUTPUT ;
    USE SIGNAL ;
    PORT
      LAYER M4 ;
        RECT  49.596 31.824 49.68 31.848 ;
    END
  END q[60]
  PIN q[61]
    DIRECTION OUTPUT ;
    USE SIGNAL ;
    PORT
      LAYER M4 ;
        RECT  49.596 31.92 49.68 31.944 ;
    END
  END q[61]
  PIN q[62]
    DIRECTION OUTPUT ;
    USE SIGNAL ;
    PORT
      LAYER M4 ;
        RECT  49.596 32.016 49.68 32.04 ;
    END
  END q[62]
  PIN q[63]
    DIRECTION OUTPUT ;
    USE SIGNAL ;
    PORT
      LAYER M4 ;
        RECT  49.596 32.112 49.68 32.136 ;
    END
  END q[63]
  PIN q[64]
    DIRECTION OUTPUT ;
    USE SIGNAL ;
    PORT
      LAYER M4 ;
        RECT  49.596 19.92 49.68 19.944 ;
    END
  END q[64]
  PIN q[65]
    DIRECTION OUTPUT ;
    USE SIGNAL ;
    PORT
      LAYER M4 ;
        RECT  49.596 20.016 49.68 20.04 ;
    END
  END q[65]
  PIN q[66]
    DIRECTION OUTPUT ;
    USE SIGNAL ;
    PORT
      LAYER M4 ;
        RECT  49.596 20.112 49.68 20.136 ;
    END
  END q[66]
  PIN q[67]
    DIRECTION OUTPUT ;
    USE SIGNAL ;
    PORT
      LAYER M4 ;
        RECT  49.596 20.208 49.68 20.232 ;
    END
  END q[67]
  PIN q[68]
    DIRECTION OUTPUT ;
    USE SIGNAL ;
    PORT
      LAYER M4 ;
        RECT  49.596 20.304 49.68 20.328 ;
    END
  END q[68]
  PIN q[69]
    DIRECTION OUTPUT ;
    USE SIGNAL ;
    PORT
      LAYER M4 ;
        RECT  49.596 20.4 49.68 20.424 ;
    END
  END q[69]
  PIN q[6]
    DIRECTION OUTPUT ;
    USE SIGNAL ;
    PORT
      LAYER M4 ;
        RECT  49.596 35.856 49.68 35.88 ;
    END
  END q[6]
  PIN q[70]
    DIRECTION OUTPUT ;
    USE SIGNAL ;
    PORT
      LAYER M4 ;
        RECT  49.596 20.496 49.68 20.52 ;
    END
  END q[70]
  PIN q[71]
    DIRECTION OUTPUT ;
    USE SIGNAL ;
    PORT
      LAYER M4 ;
        RECT  49.596 20.592 49.68 20.616 ;
    END
  END q[71]
  PIN q[72]
    DIRECTION OUTPUT ;
    USE SIGNAL ;
    PORT
      LAYER M4 ;
        RECT  49.596 20.688 49.68 20.712 ;
    END
  END q[72]
  PIN q[73]
    DIRECTION OUTPUT ;
    USE SIGNAL ;
    PORT
      LAYER M4 ;
        RECT  49.596 20.784 49.68 20.808 ;
    END
  END q[73]
  PIN q[74]
    DIRECTION OUTPUT ;
    USE SIGNAL ;
    PORT
      LAYER M4 ;
        RECT  49.596 20.88 49.68 20.904 ;
    END
  END q[74]
  PIN q[75]
    DIRECTION OUTPUT ;
    USE SIGNAL ;
    PORT
      LAYER M4 ;
        RECT  49.596 20.976 49.68 21 ;
    END
  END q[75]
  PIN q[76]
    DIRECTION OUTPUT ;
    USE SIGNAL ;
    PORT
      LAYER M4 ;
        RECT  49.596 21.072 49.68 21.096 ;
    END
  END q[76]
  PIN q[77]
    DIRECTION OUTPUT ;
    USE SIGNAL ;
    PORT
      LAYER M4 ;
        RECT  49.596 21.168 49.68 21.192 ;
    END
  END q[77]
  PIN q[78]
    DIRECTION OUTPUT ;
    USE SIGNAL ;
    PORT
      LAYER M4 ;
        RECT  49.596 21.264 49.68 21.288 ;
    END
  END q[78]
  PIN q[79]
    DIRECTION OUTPUT ;
    USE SIGNAL ;
    PORT
      LAYER M4 ;
        RECT  49.596 21.36 49.68 21.384 ;
    END
  END q[79]
  PIN q[7]
    DIRECTION OUTPUT ;
    USE SIGNAL ;
    PORT
      LAYER M4 ;
        RECT  49.596 35.952 49.68 35.976 ;
    END
  END q[7]
  PIN q[80]
    DIRECTION OUTPUT ;
    USE SIGNAL ;
    PORT
      LAYER M4 ;
        RECT  49.596 21.456 49.68 21.48 ;
    END
  END q[80]
  PIN q[81]
    DIRECTION OUTPUT ;
    USE SIGNAL ;
    PORT
      LAYER M4 ;
        RECT  49.596 21.552 49.68 21.576 ;
    END
  END q[81]
  PIN q[82]
    DIRECTION OUTPUT ;
    USE SIGNAL ;
    PORT
      LAYER M4 ;
        RECT  49.596 21.648 49.68 21.672 ;
    END
  END q[82]
  PIN q[83]
    DIRECTION OUTPUT ;
    USE SIGNAL ;
    PORT
      LAYER M4 ;
        RECT  49.596 21.744 49.68 21.768 ;
    END
  END q[83]
  PIN q[84]
    DIRECTION OUTPUT ;
    USE SIGNAL ;
    PORT
      LAYER M4 ;
        RECT  49.596 21.84 49.68 21.864 ;
    END
  END q[84]
  PIN q[85]
    DIRECTION OUTPUT ;
    USE SIGNAL ;
    PORT
      LAYER M4 ;
        RECT  49.596 21.936 49.68 21.96 ;
    END
  END q[85]
  PIN q[86]
    DIRECTION OUTPUT ;
    USE SIGNAL ;
    PORT
      LAYER M4 ;
        RECT  49.596 22.032 49.68 22.056 ;
    END
  END q[86]
  PIN q[87]
    DIRECTION OUTPUT ;
    USE SIGNAL ;
    PORT
      LAYER M4 ;
        RECT  49.596 22.128 49.68 22.152 ;
    END
  END q[87]
  PIN q[88]
    DIRECTION OUTPUT ;
    USE SIGNAL ;
    PORT
      LAYER M4 ;
        RECT  49.596 22.224 49.68 22.248 ;
    END
  END q[88]
  PIN q[89]
    DIRECTION OUTPUT ;
    USE SIGNAL ;
    PORT
      LAYER M4 ;
        RECT  49.596 22.32 49.68 22.344 ;
    END
  END q[89]
  PIN q[8]
    DIRECTION OUTPUT ;
    USE SIGNAL ;
    PORT
      LAYER M4 ;
        RECT  49.596 36.048 49.68 36.072 ;
    END
  END q[8]
  PIN q[90]
    DIRECTION OUTPUT ;
    USE SIGNAL ;
    PORT
      LAYER M4 ;
        RECT  49.596 22.416 49.68 22.44 ;
    END
  END q[90]
  PIN q[91]
    DIRECTION OUTPUT ;
    USE SIGNAL ;
    PORT
      LAYER M4 ;
        RECT  49.596 22.512 49.68 22.536 ;
    END
  END q[91]
  PIN q[92]
    DIRECTION OUTPUT ;
    USE SIGNAL ;
    PORT
      LAYER M4 ;
        RECT  49.596 22.608 49.68 22.632 ;
    END
  END q[92]
  PIN q[93]
    DIRECTION OUTPUT ;
    USE SIGNAL ;
    PORT
      LAYER M4 ;
        RECT  49.596 22.704 49.68 22.728 ;
    END
  END q[93]
  PIN q[94]
    DIRECTION OUTPUT ;
    USE SIGNAL ;
    PORT
      LAYER M4 ;
        RECT  49.596 22.8 49.68 22.824 ;
    END
  END q[94]
  PIN q[95]
    DIRECTION OUTPUT ;
    USE SIGNAL ;
    PORT
      LAYER M4 ;
        RECT  49.596 22.896 49.68 22.92 ;
    END
  END q[95]
  PIN q[96]
    DIRECTION OUTPUT ;
    USE SIGNAL ;
    PORT
      LAYER M4 ;
        RECT  49.596 32.208 49.68 32.232 ;
    END
  END q[96]
  PIN q[97]
    DIRECTION OUTPUT ;
    USE SIGNAL ;
    PORT
      LAYER M4 ;
        RECT  49.596 32.304 49.68 32.328 ;
    END
  END q[97]
  PIN q[98]
    DIRECTION OUTPUT ;
    USE SIGNAL ;
    PORT
      LAYER M4 ;
        RECT  49.596 32.4 49.68 32.424 ;
    END
  END q[98]
  PIN q[99]
    DIRECTION OUTPUT ;
    USE SIGNAL ;
    PORT
      LAYER M4 ;
        RECT  49.596 32.496 49.68 32.52 ;
    END
  END q[99]
  PIN q[9]
    DIRECTION OUTPUT ;
    USE SIGNAL ;
    PORT
      LAYER M4 ;
        RECT  49.596 36.144 49.68 36.168 ;
    END
  END q[9]
  PIN VDD
    DIRECTION INOUT ;
    USE POWER ;
    PORT
      LAYER M5 ;
        RECT  45.792 2.151 45.912 62.649 ;
        RECT  40.392 2.151 40.512 62.649 ;
        RECT  34.992 2.151 35.112 62.649 ;
        RECT  29.592 2.151 29.712 62.649 ;
        RECT  24.192 2.151 24.312 62.649 ;
        RECT  18.792 2.151 18.912 62.649 ;
        RECT  13.392 2.151 13.512 62.649 ;
        RECT  7.992 2.151 8.112 62.649 ;
        RECT  2.592 2.151 2.712 62.649 ;
    END
  END VDD
  PIN VSS
    DIRECTION INOUT ;
    USE GROUND ;
    PORT
      LAYER M5 ;
        RECT  45.6 2.137 45.72 62.663 ;
        RECT  40.2 2.137 40.32 62.663 ;
        RECT  34.8 2.137 34.92 62.663 ;
        RECT  29.4 2.137 29.52 62.663 ;
        RECT  24 2.137 24.12 62.663 ;
        RECT  18.6 2.137 18.72 62.663 ;
        RECT  13.2 2.137 13.32 62.663 ;
        RECT  7.8 2.137 7.92 62.663 ;
        RECT  2.4 2.137 2.52 62.663 ;
    END
  END VSS
  OBS
    LAYER RVTN ;
     RECT  2.16 2.16 47.52 2.295 ;
     RECT  2.16 2.565 47.52 2.835 ;
     RECT  2.16 3.105 47.52 3.375 ;
     RECT  2.16 3.645 47.52 3.915 ;
     RECT  2.16 4.185 47.52 4.455 ;
     RECT  2.16 4.725 47.52 4.995 ;
     RECT  2.16 5.265 47.52 5.535 ;
     RECT  2.16 5.805 47.52 6.075 ;
     RECT  2.16 6.345 47.52 6.615 ;
     RECT  2.16 6.885 47.52 7.155 ;
     RECT  2.16 7.425 47.52 7.695 ;
     RECT  2.16 7.965 47.52 8.235 ;
     RECT  2.16 8.505 47.52 8.775 ;
     RECT  2.16 9.045 47.52 9.315 ;
     RECT  2.16 9.585 47.52 9.855 ;
     RECT  2.16 10.125 47.52 10.395 ;
     RECT  2.16 10.665 47.52 10.935 ;
     RECT  2.16 11.205 47.52 11.475 ;
     RECT  2.16 11.745 47.52 12.015 ;
     RECT  2.16 12.285 47.52 12.555 ;
     RECT  2.16 12.825 47.52 13.095 ;
     RECT  2.16 13.365 47.52 13.635 ;
     RECT  2.16 13.905 47.52 14.175 ;
     RECT  2.16 14.445 47.52 14.715 ;
     RECT  2.16 14.985 47.52 15.255 ;
     RECT  2.16 15.525 47.52 15.795 ;
     RECT  2.16 16.065 47.52 16.335 ;
     RECT  2.16 16.605 47.52 16.875 ;
     RECT  2.16 17.145 47.52 17.415 ;
     RECT  2.16 17.685 47.52 17.955 ;
     RECT  2.16 18.225 47.52 18.495 ;
     RECT  2.16 18.765 47.52 19.035 ;
     RECT  2.16 19.305 47.52 19.575 ;
     RECT  2.16 19.845 47.52 20.115 ;
     RECT  2.16 20.385 47.52 20.655 ;
     RECT  2.16 20.925 47.52 21.195 ;
     RECT  2.16 21.465 47.52 21.735 ;
     RECT  2.16 22.005 47.52 22.275 ;
     RECT  2.16 22.545 47.52 22.815 ;
     RECT  2.16 23.085 47.52 23.355 ;
     RECT  2.16 23.625 47.52 23.895 ;
     RECT  2.16 24.165 47.52 24.435 ;
     RECT  2.16 24.705 47.52 24.975 ;
     RECT  2.16 25.245 47.52 25.515 ;
     RECT  2.16 25.785 47.52 26.055 ;
     RECT  2.16 26.325 47.52 26.595 ;
     RECT  2.16 26.865 47.52 27.135 ;
     RECT  2.16 27.405 47.52 27.675 ;
     RECT  2.16 27.945 47.52 28.215 ;
     RECT  2.16 28.485 47.52 28.755 ;
     RECT  2.16 29.025 47.52 29.295 ;
     RECT  2.16 29.565 47.52 29.835 ;
     RECT  2.16 30.105 47.52 30.375 ;
     RECT  2.16 30.645 47.52 30.915 ;
     RECT  2.16 31.185 47.52 31.455 ;
     RECT  2.16 31.725 47.52 31.995 ;
     RECT  2.16 32.265 47.52 32.535 ;
     RECT  2.16 32.805 47.52 33.075 ;
     RECT  2.16 33.345 47.52 33.615 ;
     RECT  2.16 33.885 47.52 34.155 ;
     RECT  2.16 34.425 47.52 34.695 ;
     RECT  2.16 34.965 47.52 35.235 ;
     RECT  2.16 35.505 47.52 35.775 ;
     RECT  2.16 36.045 47.52 36.315 ;
     RECT  2.16 36.585 47.52 36.855 ;
     RECT  2.16 37.125 47.52 37.395 ;
     RECT  2.16 37.665 47.52 37.935 ;
     RECT  2.16 38.205 47.52 38.475 ;
     RECT  2.16 38.745 47.52 39.015 ;
     RECT  2.16 39.285 47.52 39.555 ;
     RECT  2.16 39.825 47.52 40.095 ;
     RECT  2.16 40.365 47.52 40.635 ;
     RECT  2.16 40.905 47.52 41.175 ;
     RECT  2.16 41.445 47.52 41.715 ;
     RECT  2.16 41.985 47.52 42.255 ;
     RECT  2.16 42.525 47.52 42.795 ;
     RECT  2.16 43.065 47.52 43.335 ;
     RECT  2.16 43.605 47.52 43.875 ;
     RECT  2.16 44.145 47.52 44.415 ;
     RECT  2.16 44.685 47.52 44.955 ;
     RECT  2.16 45.225 47.52 45.495 ;
     RECT  2.16 45.765 47.52 46.035 ;
     RECT  2.16 46.305 47.52 46.575 ;
     RECT  2.16 46.845 47.52 47.115 ;
     RECT  2.16 47.385 47.52 47.655 ;
     RECT  2.16 47.925 47.52 48.195 ;
     RECT  2.16 48.465 47.52 48.735 ;
     RECT  2.16 49.005 47.52 49.275 ;
     RECT  2.16 49.545 47.52 49.815 ;
     RECT  2.16 50.085 47.52 50.355 ;
     RECT  2.16 50.625 47.52 50.895 ;
     RECT  2.16 51.165 47.52 51.435 ;
     RECT  2.16 51.705 47.52 51.975 ;
     RECT  2.16 52.245 47.52 52.515 ;
     RECT  2.16 52.785 47.52 53.055 ;
     RECT  2.16 53.325 47.52 53.595 ;
     RECT  2.16 53.865 47.52 54.135 ;
     RECT  2.16 54.405 47.52 54.675 ;
     RECT  2.16 54.945 47.52 55.215 ;
     RECT  2.16 55.485 47.52 55.755 ;
     RECT  2.16 56.025 47.52 56.295 ;
     RECT  2.16 56.565 47.52 56.835 ;
     RECT  2.16 57.105 47.52 57.375 ;
     RECT  2.16 57.645 47.52 57.915 ;
     RECT  2.16 58.185 47.52 58.455 ;
     RECT  2.16 58.725 47.52 58.995 ;
     RECT  2.16 59.265 47.52 59.535 ;
     RECT  2.16 59.805 47.52 60.075 ;
     RECT  2.16 60.345 47.52 60.615 ;
     RECT  2.16 60.885 47.52 61.155 ;
     RECT  2.16 61.425 47.52 61.695 ;
     RECT  2.16 61.965 47.52 62.235 ;
     RECT  2.16 62.505 47.52 62.64 ;
    LAYER RVTP ;
     RECT  2.16 2.295 47.52 2.565 ;
     RECT  2.16 2.835 47.52 3.105 ;
     RECT  2.16 3.375 47.52 3.645 ;
     RECT  2.16 3.915 47.52 4.185 ;
     RECT  2.16 4.455 47.52 4.725 ;
     RECT  2.16 4.995 47.52 5.265 ;
     RECT  2.16 5.535 47.52 5.805 ;
     RECT  2.16 6.075 47.52 6.345 ;
     RECT  2.16 6.615 47.52 6.885 ;
     RECT  2.16 7.155 47.52 7.425 ;
     RECT  2.16 7.695 47.52 7.965 ;
     RECT  2.16 8.235 47.52 8.505 ;
     RECT  2.16 8.775 47.52 9.045 ;
     RECT  2.16 9.315 47.52 9.585 ;
     RECT  2.16 9.855 47.52 10.125 ;
     RECT  2.16 10.395 47.52 10.665 ;
     RECT  2.16 10.935 47.52 11.205 ;
     RECT  2.16 11.475 47.52 11.745 ;
     RECT  2.16 12.015 47.52 12.285 ;
     RECT  2.16 12.555 47.52 12.825 ;
     RECT  2.16 13.095 47.52 13.365 ;
     RECT  2.16 13.635 47.52 13.905 ;
     RECT  2.16 14.175 47.52 14.445 ;
     RECT  2.16 14.715 47.52 14.985 ;
     RECT  2.16 15.255 47.52 15.525 ;
     RECT  2.16 15.795 47.52 16.065 ;
     RECT  2.16 16.335 47.52 16.605 ;
     RECT  2.16 16.875 47.52 17.145 ;
     RECT  2.16 17.415 47.52 17.685 ;
     RECT  2.16 17.955 47.52 18.225 ;
     RECT  2.16 18.495 47.52 18.765 ;
     RECT  2.16 19.035 47.52 19.305 ;
     RECT  2.16 19.575 47.52 19.845 ;
     RECT  2.16 20.115 47.52 20.385 ;
     RECT  2.16 20.655 47.52 20.925 ;
     RECT  2.16 21.195 47.52 21.465 ;
     RECT  2.16 21.735 47.52 22.005 ;
     RECT  2.16 22.275 47.52 22.545 ;
     RECT  2.16 22.815 47.52 23.085 ;
     RECT  2.16 23.355 47.52 23.625 ;
     RECT  2.16 23.895 47.52 24.165 ;
     RECT  2.16 24.435 47.52 24.705 ;
     RECT  2.16 24.975 47.52 25.245 ;
     RECT  2.16 25.515 47.52 25.785 ;
     RECT  2.16 26.055 47.52 26.325 ;
     RECT  2.16 26.595 47.52 26.865 ;
     RECT  2.16 27.135 47.52 27.405 ;
     RECT  2.16 27.675 47.52 27.945 ;
     RECT  2.16 28.215 47.52 28.485 ;
     RECT  2.16 28.755 47.52 29.025 ;
     RECT  2.16 29.295 47.52 29.565 ;
     RECT  2.16 29.835 47.52 30.105 ;
     RECT  2.16 30.375 47.52 30.645 ;
     RECT  2.16 30.915 47.52 31.185 ;
     RECT  2.16 31.455 47.52 31.725 ;
     RECT  2.16 31.995 47.52 32.265 ;
     RECT  2.16 32.535 47.52 32.805 ;
     RECT  2.16 33.075 47.52 33.345 ;
     RECT  2.16 33.615 47.52 33.885 ;
     RECT  2.16 34.155 47.52 34.425 ;
     RECT  2.16 34.695 47.52 34.965 ;
     RECT  2.16 35.235 47.52 35.505 ;
     RECT  2.16 35.775 47.52 36.045 ;
     RECT  2.16 36.315 47.52 36.585 ;
     RECT  2.16 36.855 47.52 37.125 ;
     RECT  2.16 37.395 47.52 37.665 ;
     RECT  2.16 37.935 47.52 38.205 ;
     RECT  2.16 38.475 47.52 38.745 ;
     RECT  2.16 39.015 47.52 39.285 ;
     RECT  2.16 39.555 47.52 39.825 ;
     RECT  2.16 40.095 47.52 40.365 ;
     RECT  2.16 40.635 47.52 40.905 ;
     RECT  2.16 41.175 47.52 41.445 ;
     RECT  2.16 41.715 47.52 41.985 ;
     RECT  2.16 42.255 47.52 42.525 ;
     RECT  2.16 42.795 47.52 43.065 ;
     RECT  2.16 43.335 47.52 43.605 ;
     RECT  2.16 43.875 47.52 44.145 ;
     RECT  2.16 44.415 47.52 44.685 ;
     RECT  2.16 44.955 47.52 45.225 ;
     RECT  2.16 45.495 47.52 45.765 ;
     RECT  2.16 46.035 47.52 46.305 ;
     RECT  2.16 46.575 47.52 46.845 ;
     RECT  2.16 47.115 47.52 47.385 ;
     RECT  2.16 47.655 47.52 47.925 ;
     RECT  2.16 48.195 47.52 48.465 ;
     RECT  2.16 48.735 47.52 49.005 ;
     RECT  2.16 49.275 47.52 49.545 ;
     RECT  2.16 49.815 47.52 50.085 ;
     RECT  2.16 50.355 47.52 50.625 ;
     RECT  2.16 50.895 47.52 51.165 ;
     RECT  2.16 51.435 47.52 51.705 ;
     RECT  2.16 51.975 47.52 52.245 ;
     RECT  2.16 52.515 47.52 52.785 ;
     RECT  2.16 53.055 47.52 53.325 ;
     RECT  2.16 53.595 47.52 53.865 ;
     RECT  2.16 54.135 47.52 54.405 ;
     RECT  2.16 54.675 47.52 54.945 ;
     RECT  2.16 55.215 47.52 55.485 ;
     RECT  2.16 55.755 47.52 56.025 ;
     RECT  2.16 56.295 47.52 56.565 ;
     RECT  2.16 56.835 47.52 57.105 ;
     RECT  2.16 57.375 47.52 57.645 ;
     RECT  2.16 57.915 47.52 58.185 ;
     RECT  2.16 58.455 47.52 58.725 ;
     RECT  2.16 58.995 47.52 59.265 ;
     RECT  2.16 59.535 47.52 59.805 ;
     RECT  2.16 60.075 47.52 60.345 ;
     RECT  2.16 60.615 47.52 60.885 ;
     RECT  2.16 61.155 47.52 61.425 ;
     RECT  2.16 61.695 47.52 61.965 ;
     RECT  2.16 62.235 47.52 62.505 ;
    LAYER M1 ;
     RECT  2.16 2.151 47.52 62.649 ;
    LAYER M2 ;
     RECT  0.067 6.588 0.103 6.606 ;
     RECT  0.067 9.252 0.103 9.27 ;
     RECT  0.103 6.588 0.139 6.84 ;
     RECT  0.103 7.632 0.139 7.65 ;
     RECT  0.103 17.082 0.139 17.1 ;
     RECT  0.103 19.89 0.139 20.412 ;
     RECT  0.103 22.212 0.139 23.148 ;
     RECT  0.103 24.75 0.139 24.768 ;
     RECT  0.103 26.1 0.139 26.118 ;
     RECT  0.103 27.882 0.139 29.016 ;
     RECT  0.103 38.682 0.139 38.7 ;
     RECT  0.103 45.54 0.139 46.098 ;
     RECT  0.103 8.631 0.167 10.116 ;
     RECT  0.139 6.588 0.175 7.65 ;
     RECT  0.167 8.631 0.175 8.838 ;
     RECT  0.103 13.068 0.175 13.086 ;
     RECT  0.103 15.3 0.175 15.318 ;
     RECT  0.139 16.38 0.175 17.1 ;
     RECT  0.139 25.83 0.175 26.118 ;
     RECT  0.139 27.882 0.175 29.25 ;
     RECT  0.103 30.384 0.175 30.402 ;
     RECT  0.103 35.514 0.203 35.532 ;
     RECT  0.103 55.881 0.203 55.899 ;
     RECT  0.175 27.882 0.211 30.402 ;
     RECT  0.103 31.194 0.211 31.212 ;
     RECT  0.167 9.828 0.275 10.116 ;
     RECT  0.103 43.542 0.311 44.208 ;
     RECT  0.211 56.376 0.311 56.394 ;
     RECT  0.175 25.83 0.391 26.658 ;
     RECT  0.211 27.882 0.391 31.212 ;
     RECT  0.103 52.722 0.499 52.74 ;
     RECT  0.175 12.834 0.535 13.086 ;
     RECT  0.175 15.3 0.535 17.1 ;
     RECT  0.139 19.62 0.535 20.412 ;
     RECT  0.139 22.212 0.535 23.346 ;
     RECT  0.103 33.012 0.535 33.03 ;
     RECT  0.103 34.362 0.535 34.38 ;
     RECT  0.103 42.732 0.535 42.75 ;
     RECT  0.103 47.322 0.535 47.34 ;
     RECT  0.103 48.402 0.535 48.834 ;
     RECT  0.247 49.824 0.535 49.842 ;
     RECT  0.247 51.102 0.535 51.12 ;
     RECT  0.211 39.87 1.147 39.888 ;
     RECT  0.535 12.834 1.175 13.428 ;
     RECT  1.147 39.798 1.175 39.888 ;
     RECT  0.535 41.526 1.175 42.75 ;
     RECT  1.399 56.772 1.723 56.79 ;
     RECT  1.723 58.392 1.795 58.41 ;
     RECT  1.759 59.202 1.795 59.22 ;
     RECT  1.795 58.392 1.831 59.22 ;
     RECT  1.175 39.798 1.975 39.816 ;
     RECT  1.723 56.304 1.975 56.79 ;
     RECT  0.103 32.202 2.155 32.22 ;
     RECT  0.535 33.012 2.155 34.38 ;
     RECT  0.175 6.588 2.16 8.838 ;
     RECT  0.275 10.098 2.16 10.116 ;
     RECT  0.103 10.98 2.16 10.998 ;
     RECT  0.103 11.79 2.16 11.808 ;
     RECT  1.175 12.906 2.16 13.428 ;
     RECT  0.535 15.3 2.16 17.478 ;
     RECT  0.103 18.774 2.16 18.792 ;
     RECT  0.535 19.62 2.16 20.448 ;
     RECT  0.535 22.086 2.16 23.346 ;
     RECT  0.139 24.75 2.16 24.93 ;
     RECT  0.391 25.83 2.16 31.212 ;
     RECT  2.155 32.202 2.16 34.38 ;
     RECT  2.155 35.442 2.16 35.46 ;
     RECT  1.723 37.134 2.16 37.152 ;
     RECT  0.139 38.178 2.16 38.7 ;
     RECT  1.975 39.798 2.16 40.428 ;
     RECT  1.175 41.526 2.16 42.354 ;
     RECT  0.311 43.614 2.16 44.208 ;
     RECT  0.139 45.54 2.16 46.332 ;
     RECT  0.535 47.322 2.16 48.834 ;
     RECT  0.535 49.824 2.16 49.878 ;
     RECT  0.535 51.102 2.16 51.804 ;
     RECT  0.499 52.722 2.16 52.884 ;
     RECT  1.975 55.962 2.16 56.79 ;
     RECT  1.831 58.392 2.16 59.49 ;
     RECT  2.16 2.151 47.52 62.649 ;
     RECT  47.52 3.924 48.371 60.714 ;
     RECT  48.371 3.924 48.407 58.644 ;
     RECT  48.407 3.924 48.443 58.374 ;
     RECT  48.443 3.924 48.479 58.284 ;
     RECT  48.371 59.544 48.731 60.714 ;
     RECT  48.479 38.916 48.911 58.284 ;
     RECT  48.479 3.924 48.983 38.124 ;
     RECT  48.911 39.186 48.983 58.284 ;
     RECT  48.983 3.924 49.019 25.974 ;
     RECT  48.983 26.946 49.019 37.854 ;
     RECT  48.983 39.186 49.019 45.144 ;
     RECT  48.983 45.936 49.019 47.259 ;
     RECT  48.983 48.276 49.019 58.284 ;
     RECT  49.019 10.206 49.055 13.356 ;
     RECT  49.019 17.766 49.055 18.252 ;
     RECT  49.019 19.926 49.055 25.074 ;
     RECT  49.019 39.456 49.055 43.362 ;
     RECT  49.019 46.116 49.055 47.259 ;
     RECT  49.019 48.276 49.055 50.148 ;
     RECT  49.019 51.444 49.055 54.162 ;
     RECT  49.019 55.188 49.055 58.284 ;
     RECT  49.019 3.924 49.091 9.414 ;
     RECT  49.055 55.836 49.091 58.284 ;
     RECT  49.091 4.698 49.127 9.414 ;
     RECT  49.055 10.206 49.127 11.844 ;
     RECT  49.127 5.346 49.235 9.414 ;
     RECT  49.235 6.201 49.343 9.414 ;
     RECT  49.091 57.006 49.387 58.284 ;
     RECT  49.343 6.201 49.415 6.759 ;
     RECT  48.731 59.544 49.415 60.408 ;
     RECT  49.415 6.588 49.451 6.759 ;
     RECT  49.387 57.006 49.451 58.644 ;
     RECT  49.415 59.544 49.451 60.174 ;
     RECT  49.451 58.581 49.459 58.644 ;
     RECT  49.343 7.668 49.487 9.414 ;
     RECT  49.019 44.658 49.487 44.712 ;
     RECT  49.451 57.006 49.487 57.564 ;
     RECT  49.451 59.706 49.487 60.174 ;
     RECT  49.235 5.346 49.523 5.364 ;
     RECT  49.487 7.668 49.523 8.532 ;
     RECT  49.055 12.906 49.523 13.284 ;
     RECT  49.055 21.096 49.523 23.922 ;
     RECT  49.019 32.166 49.523 35.064 ;
     RECT  49.055 39.456 49.523 40.86 ;
     RECT  49.487 44.694 49.523 44.712 ;
     RECT  49.055 48.276 49.523 49.734 ;
     RECT  49.487 57.276 49.523 57.564 ;
     RECT  49.459 58.581 49.523 58.716 ;
     RECT  49.091 3.924 49.559 3.942 ;
     RECT  49.523 8.514 49.559 8.532 ;
     RECT  49.127 10.746 49.559 11.844 ;
     RECT  49.019 14.184 49.559 16.524 ;
     RECT  49.523 21.096 49.559 22.464 ;
     RECT  49.523 23.328 49.559 23.346 ;
     RECT  49.019 27.414 49.559 30.906 ;
     RECT  49.523 32.166 49.559 33.804 ;
     RECT  49.523 34.938 49.559 35.028 ;
     RECT  49.019 35.946 49.559 36.846 ;
     RECT  49.523 39.456 49.559 40.824 ;
     RECT  49.055 41.616 49.559 43.362 ;
     RECT  49.523 48.276 49.559 49.068 ;
     RECT  49.055 51.876 49.559 54.162 ;
     RECT  49.091 55.836 49.559 56.124 ;
     RECT  49.523 58.698 49.559 58.716 ;
     RECT  49.487 9.396 49.595 9.414 ;
     RECT  49.559 10.746 49.595 11.394 ;
     RECT  49.523 12.906 49.595 12.924 ;
     RECT  49.559 14.346 49.595 16.524 ;
     RECT  49.055 17.766 49.595 17.784 ;
     RECT  49.055 19.926 49.595 19.944 ;
     RECT  49.559 21.096 49.595 21.114 ;
     RECT  49.559 22.284 49.595 22.464 ;
     RECT  49.055 24.714 49.595 25.074 ;
     RECT  49.559 27.414 49.595 27.774 ;
     RECT  49.559 28.836 49.595 30.906 ;
     RECT  49.559 32.166 49.595 32.184 ;
     RECT  49.559 33.12 49.595 33.804 ;
     RECT  49.559 35.01 49.595 35.028 ;
     RECT  49.559 35.946 49.595 36.504 ;
     RECT  49.559 39.456 49.595 39.474 ;
     RECT  49.559 40.68 49.595 40.698 ;
     RECT  49.559 42.156 49.595 43.056 ;
     RECT  49.055 47.016 49.595 47.259 ;
     RECT  49.559 48.591 49.595 49.068 ;
     RECT  49.559 51.876 49.595 53.784 ;
     RECT  49.559 55.836 49.595 55.854 ;
     RECT  49.523 57.546 49.595 57.564 ;
     RECT  49.523 7.668 49.631 7.686 ;
     RECT  49.595 10.746 49.631 10.809 ;
     RECT  49.487 60.156 49.631 60.174 ;
     RECT  49.451 6.741 49.667 6.759 ;
     RECT  49.631 10.791 49.667 10.809 ;
     RECT  49.595 14.652 49.667 14.67 ;
     RECT  49.595 15.966 49.667 15.984 ;
     RECT  49.055 46.116 49.667 46.134 ;
     RECT  49.595 48.591 49.667 48.609 ;
    LAYER M3 ;
     RECT  2.415 2.143 2.505 2.413 ;
     RECT  7.815 2.143 7.905 2.413 ;
     RECT  13.215 2.143 13.305 2.413 ;
     RECT  18.615 2.143 18.705 2.413 ;
     RECT  24.015 2.143 24.105 2.413 ;
     RECT  29.415 2.143 29.505 2.413 ;
     RECT  34.815 2.143 34.905 2.413 ;
     RECT  40.215 2.143 40.305 2.413 ;
     RECT  45.615 2.143 45.705 2.413 ;
     RECT  45.615 2.413 45.897 3.847 ;
     RECT  45.252 3.847 45.897 3.883 ;
     RECT  45.252 3.883 46.062 3.955 ;
     RECT  46.836 3.721 46.854 3.955 ;
     RECT  44.784 3.955 46.854 3.991 ;
     RECT  48.78 4.261 48.798 4.351 ;
     RECT  48.708 4.351 48.798 4.387 ;
     RECT  49.536 3.919 49.554 4.387 ;
     RECT  44.172 3.991 47.142 4.621 ;
     RECT  44.1 4.621 47.142 4.693 ;
     RECT  44.1 4.693 47.25 4.801 ;
     RECT  48.708 4.387 49.554 4.927 ;
     RECT  44.1 4.801 47.394 5.035 ;
     RECT  44.028 5.035 47.394 5.071 ;
     RECT  48.132 4.927 49.554 5.071 ;
     RECT  41.22 3.541 41.238 5.305 ;
     RECT  42.516 5.161 43.002 5.305 ;
     RECT  44.028 5.071 49.554 5.305 ;
     RECT  41.22 5.305 41.31 5.467 ;
     RECT  42.516 5.305 49.554 5.467 ;
     RECT  40.215 2.413 40.497 5.575 ;
     RECT  41.22 5.467 49.554 5.575 ;
     RECT  40.215 5.575 49.554 6.151 ;
     RECT  37.908 6.241 37.926 6.313 ;
     RECT  38.736 6.277 38.754 6.349 ;
     RECT  36.612 5.431 36.63 6.379 ;
     RECT  36.612 6.379 37.062 6.385 ;
     RECT  37.908 6.313 37.962 6.385 ;
     RECT  38.736 6.349 39.078 6.385 ;
     RECT  39.888 6.151 49.554 6.385 ;
     RECT  33.588 5.809 33.606 6.421 ;
     RECT  36.612 6.385 37.962 6.511 ;
     RECT  38.736 6.385 49.554 6.511 ;
     RECT  2.415 2.413 2.697 6.547 ;
     RECT  4.428 6.421 4.446 6.547 ;
     RECT  7.815 2.413 8.097 6.547 ;
     RECT  13.215 2.413 13.497 6.547 ;
     RECT  24.015 2.413 24.297 6.619 ;
     RECT  33.588 6.421 33.822 6.647 ;
     RECT  0.072 6.583 0.09 6.655 ;
     RECT  4.428 6.547 4.698 6.655 ;
     RECT  10.188 6.547 10.854 6.655 ;
     RECT  2.415 6.547 2.862 6.691 ;
     RECT  3.708 6.655 4.698 6.691 ;
     RECT  6.3 6.421 6.318 6.691 ;
     RECT  7.308 6.547 8.097 6.691 ;
     RECT  13.212 6.547 13.497 6.691 ;
     RECT  23.976 6.619 24.297 6.691 ;
     RECT  34.815 2.413 35.097 6.691 ;
     RECT  36.612 6.511 49.554 6.691 ;
     RECT  35.856 6.691 49.554 6.736 ;
     RECT  3.708 6.691 5.562 6.781 ;
     RECT  6.3 6.691 8.097 6.781 ;
     RECT  9.792 6.655 10.854 6.781 ;
     RECT  23.94 6.691 24.297 6.817 ;
     RECT  11.736 6.691 11.754 6.853 ;
     RECT  31.752 6.547 31.77 6.853 ;
     RECT  3.708 6.781 8.097 6.889 ;
     RECT  11.592 6.853 11.754 6.889 ;
     RECT  12.528 6.691 13.554 6.889 ;
     RECT  3.708 6.889 8.19 6.925 ;
     RECT  9.324 6.781 10.854 6.925 ;
     RECT  11.592 6.889 14.13 6.925 ;
     RECT  16.812 6.889 16.83 6.925 ;
     RECT  2.376 6.691 2.862 6.961 ;
     RECT  3.672 6.925 8.298 6.961 ;
     RECT  9.324 6.925 14.13 6.961 ;
     RECT  18.615 2.413 18.897 6.961 ;
     RECT  20.484 6.889 20.502 6.961 ;
     RECT  22.536 6.889 22.554 6.961 ;
     RECT  29.415 2.413 29.697 6.961 ;
     RECT  30.456 6.925 30.474 6.961 ;
     RECT  20.484 6.961 21.078 7.051 ;
     RECT  9.18 6.961 14.274 7.087 ;
     RECT  20.268 7.051 21.078 7.087 ;
     RECT  22.212 6.961 22.554 7.087 ;
     RECT  23.652 6.817 24.297 7.087 ;
     RECT  31.752 6.853 31.986 7.087 ;
     RECT  0.072 6.655 0.234 7.123 ;
     RECT  22.212 7.087 24.297 7.123 ;
     RECT  34.776 6.691 35.097 7.123 ;
     RECT  35.856 6.736 49.662 7.123 ;
     RECT  29.34 6.961 29.697 7.159 ;
     RECT  30.456 6.961 30.87 7.159 ;
     RECT  31.716 7.087 31.986 7.159 ;
     RECT  2.376 6.961 8.298 7.195 ;
     RECT  29.34 7.159 30.87 7.195 ;
     RECT  31.716 7.159 32.022 7.195 ;
     RECT  16.452 6.925 16.83 7.231 ;
     RECT  18.18 6.961 18.897 7.231 ;
     RECT  20.268 7.087 21.366 7.231 ;
     RECT  22.212 7.123 24.354 7.231 ;
     RECT  2.304 7.195 8.298 7.321 ;
     RECT  9.18 7.087 14.742 7.321 ;
     RECT  17.82 7.231 25.182 7.321 ;
     RECT  28.296 6.853 28.314 7.321 ;
     RECT  29.124 7.195 30.87 7.321 ;
     RECT  28.224 7.321 28.314 7.357 ;
     RECT  29.124 7.321 30.942 7.357 ;
     RECT  28.224 7.357 30.942 7.387 ;
     RECT  31.716 7.195 32.166 7.387 ;
     RECT  26.748 6.961 27.378 7.429 ;
     RECT  28.224 7.387 32.166 7.429 ;
     RECT  33.588 6.647 33.858 7.429 ;
     RECT  34.776 7.123 49.662 7.429 ;
     RECT  2.304 7.321 14.742 7.465 ;
     RECT  15.804 7.231 17.082 7.465 ;
     RECT  17.82 7.321 25.218 7.465 ;
     RECT  26.64 7.429 32.166 7.465 ;
     RECT  2.304 7.465 25.614 7.483 ;
     RECT  0.072 7.123 0.27 7.501 ;
     RECT  1.152 7.321 1.17 7.501 ;
     RECT  2.304 7.483 25.65 7.501 ;
     RECT  26.64 7.465 32.562 7.501 ;
     RECT  2.304 7.501 32.562 7.627 ;
     RECT  33.444 7.429 33.858 7.627 ;
     RECT  2.304 7.627 33.858 7.655 ;
     RECT  11.988 7.655 33.858 7.723 ;
     RECT  11.988 7.723 33.966 8.005 ;
     RECT  34.74 7.429 49.662 8.005 ;
     RECT  2.304 7.655 11.25 8.195 ;
     RECT  0.072 7.501 1.17 8.333 ;
     RECT  11.988 8.005 49.662 8.429 ;
     RECT  2.34 8.195 11.25 8.437 ;
     RECT  11.988 8.429 35.586 8.437 ;
     RECT  0.072 8.333 0.414 8.813 ;
     RECT  2.34 8.437 35.586 8.968 ;
     RECT  2.232 8.968 35.586 9.005 ;
     RECT  1.152 8.333 1.17 9.211 ;
     RECT  0.072 8.813 0.378 9.275 ;
     RECT  2.304 9.005 35.586 9.283 ;
     RECT  36.324 8.429 49.662 9.283 ;
     RECT  2.304 9.283 49.662 9.389 ;
     RECT  1.152 9.211 1.242 9.485 ;
     RECT  1.224 9.485 1.242 9.677 ;
     RECT  0.108 9.275 0.378 9.739 ;
     RECT  0.108 9.739 0.414 9.869 ;
     RECT  2.304 9.389 47.61 9.959 ;
     RECT  18.216 9.959 47.61 10.109 ;
     RECT  2.304 9.959 17.442 10.253 ;
     RECT  32.184 10.109 47.61 10.435 ;
     RECT  0.108 9.869 0.378 10.637 ;
     RECT  2.304 10.253 10.638 10.705 ;
     RECT  32.184 10.435 47.862 10.705 ;
     RECT  48.708 9.389 49.662 10.705 ;
     RECT  32.184 10.705 49.662 10.814 ;
     RECT  0.108 10.637 0.162 10.829 ;
     RECT  11.484 10.253 17.442 10.831 ;
     RECT  18.216 10.109 31.266 10.831 ;
     RECT  32.184 10.814 49.59 10.831 ;
     RECT  11.484 10.831 49.59 11.101 ;
     RECT  2.268 10.705 10.638 11.209 ;
     RECT  11.412 11.101 49.59 11.209 ;
     RECT  2.268 11.209 49.59 11.213 ;
     RECT  2.268 11.213 47.394 11.501 ;
     RECT  2.268 11.501 47.178 11.705 ;
     RECT  0.108 10.829 0.126 11.707 ;
     RECT  2.268 11.705 47.142 11.777 ;
     RECT  48.42 11.213 49.59 11.789 ;
     RECT  2.268 11.777 47.07 11.885 ;
     RECT  2.304 11.885 47.07 11.933 ;
     RECT  0.108 11.707 0.198 12.077 ;
     RECT  2.304 11.933 26.37 12.317 ;
     RECT  48.024 12.043 48.042 12.389 ;
     RECT  0.324 12.331 0.342 12.461 ;
     RECT  27.252 11.933 47.07 12.631 ;
     RECT  27.252 12.631 47.142 12.721 ;
     RECT  48.96 11.789 49.59 12.865 ;
     RECT  1.152 12.829 1.17 12.929 ;
     RECT  48.42 12.865 49.59 12.929 ;
     RECT  9 12.317 26.37 12.991 ;
     RECT  27.252 12.721 47.286 12.991 ;
     RECT  0.18 12.829 0.234 13.063 ;
     RECT  9 12.991 47.286 13.063 ;
     RECT  9 13.063 47.466 13.099 ;
     RECT  2.304 12.317 8.097 13.171 ;
     RECT  8.82 13.099 47.466 13.171 ;
     RECT  2.304 13.171 47.466 13.387 ;
     RECT  48.42 12.929 49.518 13.387 ;
     RECT  0.108 13.063 0.234 13.405 ;
     RECT  0.108 13.405 0.558 13.421 ;
     RECT  2.304 13.387 49.518 13.559 ;
     RECT  47.988 13.559 49.518 13.771 ;
     RECT  0.54 13.421 0.558 13.805 ;
     RECT  2.304 13.559 47.178 13.837 ;
     RECT  2.268 13.837 47.178 13.997 ;
     RECT  47.988 13.771 49.59 13.997 ;
     RECT  48.024 13.997 49.59 14.009 ;
     RECT  0.324 14.539 0.342 14.635 ;
     RECT  48.456 14.009 49.59 14.647 ;
     RECT  0.144 14.635 0.342 14.669 ;
     RECT  2.304 13.997 47.178 15.025 ;
     RECT  0.144 14.669 0.162 15.292 ;
     RECT  0.108 15.292 0.162 15.437 ;
     RECT  2.304 15.025 47.394 15.437 ;
     RECT  2.304 15.437 47.322 15.493 ;
     RECT  2.268 15.493 47.322 15.719 ;
     RECT  2.268 15.719 31.842 15.869 ;
     RECT  48.456 14.647 49.662 15.989 ;
     RECT  0.18 15.871 0.234 15.997 ;
     RECT  0.18 15.997 0.342 16.301 ;
     RECT  48.456 15.989 49.59 16.397 ;
     RECT  48.492 16.397 49.59 16.493 ;
     RECT  10.656 15.869 31.842 16.501 ;
     RECT  10.656 16.501 31.878 16.573 ;
     RECT  32.616 15.719 47.322 16.573 ;
     RECT  10.656 16.573 47.322 16.609 ;
     RECT  2.268 15.869 9.846 16.681 ;
     RECT  10.584 16.609 47.322 16.681 ;
     RECT  0.144 16.375 0.162 17.077 ;
     RECT  2.268 16.681 47.322 17.077 ;
     RECT  2.232 17.077 47.394 17.141 ;
     RECT  0.108 17.077 0.162 17.165 ;
     RECT  48.924 16.493 49.59 17.227 ;
     RECT  2.268 17.141 47.394 17.357 ;
     RECT  0.144 17.165 0.162 17.453 ;
     RECT  48.42 17.227 49.59 17.611 ;
     RECT  48.384 17.611 49.59 17.707 ;
     RECT  0.18 17.455 0.558 17.981 ;
     RECT  0.324 17.981 0.558 18.029 ;
     RECT  0.324 18.029 0.342 18.221 ;
     RECT  2.268 17.357 47.178 18.229 ;
     RECT  2.268 18.229 47.25 18.283 ;
     RECT  2.232 18.283 47.25 18.301 ;
     RECT  2.232 18.301 47.322 18.379 ;
     RECT  2.232 18.379 47.358 18.563 ;
     RECT  2.268 18.563 47.358 18.571 ;
     RECT  48.24 17.707 49.59 18.571 ;
     RECT  2.268 18.571 49.59 18.599 ;
     RECT  2.268 18.599 47.862 19.103 ;
     RECT  2.304 19.103 47.862 19.409 ;
     RECT  0.108 18.769 0.126 19.615 ;
     RECT  32.832 19.409 47.358 19.757 ;
     RECT  2.304 19.409 32.094 20.011 ;
     RECT  2.232 20.011 32.094 20.155 ;
     RECT  32.832 19.757 47.25 20.155 ;
     RECT  48.96 18.599 49.59 20.191 ;
     RECT  2.232 20.155 47.25 20.309 ;
     RECT  34.2 20.309 47.25 20.381 ;
     RECT  0.108 19.615 0.162 20.425 ;
     RECT  2.232 20.309 33.462 20.687 ;
     RECT  0.108 20.425 0.558 20.717 ;
     RECT  0.108 20.717 0.162 20.813 ;
     RECT  48.924 20.191 49.59 20.971 ;
     RECT  2.304 20.687 33.462 21.091 ;
     RECT  34.2 20.381 47.214 21.091 ;
     RECT  2.304 21.091 47.214 21.115 ;
     RECT  2.304 21.115 47.286 21.355 ;
     RECT  48.456 20.971 49.59 21.355 ;
     RECT  0.144 20.813 0.162 21.437 ;
     RECT  2.304 21.355 49.59 21.569 ;
     RECT  0.18 21.643 0.342 22.081 ;
     RECT  0.18 22.081 0.558 22.207 ;
     RECT  2.304 21.569 47.394 22.207 ;
     RECT  2.232 22.207 47.394 22.307 ;
     RECT  2.304 22.307 47.394 22.351 ;
     RECT  48.384 21.569 49.59 22.351 ;
     RECT  2.304 22.351 49.59 22.469 ;
     RECT  2.304 22.469 49.518 23.021 ;
     RECT  2.304 23.021 15.174 23.045 ;
     RECT  0.108 22.207 0.558 23.213 ;
     RECT  15.912 23.021 49.518 23.309 ;
     RECT  48.456 23.309 49.518 23.323 ;
     RECT  2.304 23.045 9.522 23.755 ;
     RECT  10.26 23.045 15.174 23.863 ;
     RECT  15.912 23.309 47.394 23.863 ;
     RECT  2.268 23.755 9.522 23.927 ;
     RECT  0.108 23.213 0.162 23.981 ;
     RECT  10.26 23.863 47.394 23.999 ;
     RECT  0.144 23.981 0.162 24.187 ;
     RECT  0.144 24.187 0.198 24.331 ;
     RECT  2.304 23.927 9.522 24.367 ;
     RECT  10.26 23.999 27.774 24.367 ;
     RECT  48.456 23.323 49.554 24.368 ;
     RECT  49.5 24.368 49.554 24.427 ;
     RECT  28.512 23.999 47.394 24.571 ;
     RECT  48.456 24.368 48.474 24.571 ;
     RECT  28.512 24.571 48.474 24.665 ;
     RECT  0.144 24.331 0.342 24.745 ;
     RECT  0.108 24.745 0.342 24.749 ;
     RECT  34.776 24.665 48.474 24.809 ;
     RECT  34.815 24.809 48.474 24.845 ;
     RECT  2.304 24.367 27.774 24.871 ;
     RECT  28.512 24.665 34.038 24.871 ;
     RECT  0.108 24.749 0.198 24.989 ;
     RECT  49.5 24.427 49.59 25.099 ;
     RECT  0.108 24.989 0.162 25.133 ;
     RECT  2.304 24.871 34.038 25.555 ;
     RECT  34.815 24.845 48.042 25.555 ;
     RECT  48.96 25.099 49.59 25.613 ;
     RECT  0.144 25.133 0.162 25.723 ;
     RECT  0.144 25.723 0.234 26.095 ;
     RECT  2.304 25.555 48.042 26.251 ;
     RECT  48.96 25.613 49.518 26.251 ;
     RECT  2.304 26.251 49.518 26.591 ;
     RECT  36.288 26.591 49.518 26.621 ;
     RECT  0.108 26.095 0.234 26.669 ;
     RECT  0.144 26.669 0.234 26.782 ;
     RECT  0.18 26.782 0.234 26.861 ;
     RECT  2.304 26.591 35.55 26.905 ;
     RECT  0.216 26.861 0.234 26.941 ;
     RECT  2.268 26.905 35.55 27.167 ;
     RECT  36.288 26.621 49.482 27.4 ;
     RECT  2.304 27.167 35.55 27.409 ;
     RECT  36.288 27.4 49.59 27.409 ;
     RECT  2.304 27.409 49.59 27.599 ;
     RECT  0.216 26.941 0.558 27.629 ;
     RECT  36.684 27.599 49.59 27.635 ;
     RECT  0.216 27.629 0.414 27.877 ;
     RECT  0.108 27.877 0.414 28.253 ;
     RECT  36.792 27.635 49.59 28.301 ;
     RECT  2.304 27.599 35.91 28.453 ;
     RECT  36.792 28.301 47.322 28.453 ;
     RECT  0.108 28.253 0.162 28.454 ;
     RECT  48.42 28.301 49.59 28.493 ;
     RECT  2.304 28.453 47.322 29.065 ;
     RECT  0.108 28.454 0.126 29.227 ;
     RECT  0.108 29.227 0.162 29.261 ;
     RECT  2.304 29.065 47.394 29.405 ;
     RECT  0.144 29.261 0.162 29.839 ;
     RECT  48.456 28.493 49.59 29.867 ;
     RECT  0.144 29.839 0.198 30.037 ;
     RECT  2.304 29.405 47.322 30.283 ;
     RECT  0.144 30.037 0.234 30.379 ;
     RECT  2.304 30.283 47.718 30.413 ;
     RECT  2.304 30.413 47.394 30.509 ;
     RECT  48.996 29.867 49.59 30.955 ;
     RECT  2.304 30.509 47.286 31.243 ;
     RECT  48.384 30.955 49.59 31.339 ;
     RECT  2.268 31.243 47.286 31.351 ;
     RECT  48.024 31.339 49.59 31.351 ;
     RECT  2.268 31.351 49.59 31.451 ;
     RECT  2.268 31.451 48.042 31.487 ;
     RECT  2.268 31.487 47.934 32.237 ;
     RECT  2.268 32.237 47.862 32.299 ;
     RECT  2.16 32.299 47.862 32.495 ;
     RECT  0.108 30.379 0.234 32.587 ;
     RECT  48.996 31.451 49.59 32.779 ;
     RECT  2.304 32.495 47.862 33.067 ;
     RECT  2.304 33.067 48.042 33.259 ;
     RECT  2.268 33.259 48.042 33.305 ;
     RECT  0.108 32.587 0.342 33.349 ;
     RECT  2.304 33.305 48.042 33.643 ;
     RECT  48.96 32.779 49.59 33.643 ;
     RECT  2.304 33.643 49.59 34.027 ;
     RECT  0.108 33.349 0.558 34.253 ;
     RECT  2.268 34.027 49.59 34.429 ;
     RECT  2.232 34.429 49.59 34.637 ;
     RECT  2.268 34.637 49.59 35.371 ;
     RECT  0.108 34.253 0.126 35.419 ;
     RECT  2.16 35.371 49.59 35.465 ;
     RECT  0.108 35.419 0.198 35.537 ;
     RECT  0.144 35.537 0.162 35.741 ;
     RECT  2.268 35.465 49.59 35.879 ;
     RECT  2.268 35.879 47.358 36.235 ;
     RECT  1.728 36.235 47.358 36.619 ;
     RECT  48.456 35.879 49.59 36.619 ;
     RECT  1.728 36.619 49.59 37.157 ;
     RECT  2.268 37.157 49.59 37.499 ;
     RECT  2.304 37.499 49.59 37.859 ;
     RECT  9.756 37.859 49.59 38.309 ;
     RECT  2.304 37.859 8.91 38.347 ;
     RECT  9.756 38.309 47.358 38.429 ;
     RECT  2.268 38.347 8.91 38.443 ;
     RECT  0.144 37.195 0.162 38.491 ;
     RECT  2.232 38.443 8.91 38.539 ;
     RECT  0.144 38.491 0.198 38.669 ;
     RECT  0.144 38.669 0.162 38.677 ;
     RECT  9.756 38.429 47.322 38.713 ;
     RECT  2.196 38.539 8.91 38.821 ;
     RECT  9.684 38.713 47.322 38.821 ;
     RECT  2.196 38.821 47.322 38.827 ;
     RECT  0.108 38.677 0.162 39.341 ;
     RECT  48.42 38.309 49.59 39.479 ;
     RECT  48.42 39.479 49.554 39.659 ;
     RECT  0.144 39.341 0.162 39.865 ;
     RECT  1.152 39.793 1.17 39.893 ;
     RECT  0.144 39.865 0.234 40.013 ;
     RECT  0.144 40.013 0.162 40.061 ;
     RECT  48.456 39.659 49.554 40.267 ;
     RECT  1.98 38.827 47.322 40.433 ;
     RECT  2.16 40.433 47.322 40.639 ;
     RECT  48.456 40.267 49.59 40.639 ;
     RECT  2.16 40.639 49.59 40.973 ;
     RECT  36.72 40.973 49.59 41.069 ;
     RECT  36.72 41.069 47.322 41.171 ;
     RECT  0.144 41.035 0.162 41.213 ;
     RECT  48.312 41.069 49.59 41.279 ;
     RECT  2.16 40.973 35.982 41.369 ;
     RECT  33.012 41.369 35.982 41.791 ;
     RECT  36.72 41.171 47.106 41.791 ;
     RECT  0.54 41.521 0.558 41.899 ;
     RECT  33.012 41.791 47.106 41.917 ;
     RECT  0.54 41.899 1.278 41.947 ;
     RECT  33.012 41.917 47.322 41.989 ;
     RECT  0.144 41.947 1.278 42.029 ;
     RECT  48.456 41.279 49.59 42.052 ;
     RECT  33.012 41.989 47.394 42.106 ;
     RECT  48.42 42.052 49.59 42.125 ;
     RECT  2.16 41.369 31.986 42.151 ;
     RECT  33.012 42.106 47.574 42.151 ;
     RECT  2.16 42.151 47.574 42.215 ;
     RECT  48.492 42.125 49.59 42.317 ;
     RECT  2.232 42.215 47.466 42.719 ;
     RECT  0.144 42.029 1.17 42.727 ;
     RECT  0.108 42.727 1.17 42.755 ;
     RECT  2.232 42.719 47.394 42.827 ;
     RECT  48.888 42.317 49.59 43.061 ;
     RECT  48.888 43.061 49.554 43.141 ;
     RECT  48.42 43.141 49.554 43.367 ;
     RECT  2.268 42.827 47.394 43.529 ;
     RECT  26.424 43.529 47.394 43.627 ;
     RECT  48.42 43.367 49.518 43.627 ;
     RECT  26.424 43.627 49.518 43.709 ;
     RECT  48.024 43.709 49.518 43.853 ;
     RECT  0.108 42.755 0.558 43.949 ;
     RECT  2.268 43.529 25.686 44.311 ;
     RECT  26.424 43.709 47.106 44.311 ;
     RECT  48.024 43.853 49.014 44.429 ;
     RECT  2.268 44.311 47.106 44.483 ;
     RECT  2.304 44.483 47.106 44.653 ;
     RECT  48.96 44.429 49.014 44.653 ;
     RECT  48.96 44.653 49.482 44.689 ;
     RECT  2.304 44.653 47.25 44.779 ;
     RECT  48.024 44.429 48.042 44.779 ;
     RECT  0.108 43.949 0.126 44.813 ;
     RECT  48.96 44.689 49.518 44.909 ;
     RECT  2.304 44.779 48.042 44.951 ;
     RECT  48.96 44.909 49.482 45.005 ;
     RECT  48.96 45.005 49.014 45.355 ;
     RECT  48.312 45.355 49.014 45.599 ;
     RECT  0.108 45.535 0.126 45.733 ;
     RECT  2.304 44.951 47.178 45.835 ;
     RECT  0.108 45.733 0.198 45.931 ;
     RECT  2.268 45.835 47.178 45.959 ;
     RECT  15.048 45.959 47.178 46.003 ;
     RECT  0.108 45.931 0.342 46.039 ;
     RECT  2.268 45.959 14.202 46.103 ;
     RECT  48.42 45.599 49.014 46.111 ;
     RECT  2.268 46.103 14.058 46.265 ;
     RECT  0.108 46.039 0.558 46.349 ;
     RECT  48.42 46.111 49.662 46.603 ;
     RECT  0.144 46.349 0.558 46.637 ;
     RECT  15.048 46.003 47.25 46.891 ;
     RECT  2.304 46.265 14.058 46.921 ;
     RECT  14.976 46.891 47.25 46.921 ;
     RECT  48.384 46.603 49.662 46.987 ;
     RECT  2.304 46.921 47.25 47.011 ;
     RECT  2.304 47.011 47.322 47.039 ;
     RECT  12.06 47.039 47.322 47.179 ;
     RECT  12.06 47.179 47.574 47.264 ;
     RECT  12.06 47.264 47.322 47.309 ;
     RECT  0.144 46.637 0.162 47.317 ;
     RECT  2.304 47.039 11.322 47.425 ;
     RECT  2.268 47.425 11.322 47.615 ;
     RECT  0.108 47.317 0.162 47.731 ;
     RECT  48.312 46.987 49.662 47.759 ;
     RECT  17.064 47.309 47.322 47.885 ;
     RECT  2.304 47.615 11.322 47.965 ;
     RECT  12.06 47.309 16.254 47.965 ;
     RECT  28.368 47.885 47.322 48.001 ;
     RECT  0.108 47.731 0.558 48.173 ;
     RECT  2.304 47.965 16.254 48.271 ;
     RECT  17.064 47.885 27.63 48.271 ;
     RECT  48.384 47.759 49.662 48.614 ;
     RECT  2.304 48.271 27.63 48.631 ;
     RECT  28.368 48.001 47.394 48.631 ;
     RECT  0.108 48.173 0.162 48.653 ;
     RECT  48.384 48.614 49.59 48.929 ;
     RECT  0.108 48.653 0.126 49.037 ;
     RECT  48.924 48.929 49.59 49.073 ;
     RECT  2.304 48.631 47.394 49.099 ;
     RECT  2.268 49.099 47.394 49.199 ;
     RECT  48.924 49.073 49.554 49.229 ;
     RECT  2.268 49.199 32.886 49.307 ;
     RECT  33.624 49.199 47.394 49.351 ;
     RECT  33.624 49.351 48.042 49.505 ;
     RECT  0.324 49.675 0.342 49.771 ;
     RECT  0.18 49.771 0.342 49.855 ;
     RECT  2.304 49.307 32.886 49.981 ;
     RECT  33.624 49.505 47.106 49.981 ;
     RECT  47.844 49.505 48.042 50.059 ;
     RECT  48.924 49.229 49.518 50.059 ;
     RECT  2.304 49.981 47.106 50.251 ;
     RECT  2.268 50.251 47.106 50.315 ;
     RECT  47.844 50.059 49.518 50.351 ;
     RECT  2.268 50.315 15.894 50.423 ;
     RECT  47.844 50.351 48.042 50.459 ;
     RECT  48.888 50.351 49.518 50.477 ;
     RECT  31.716 50.315 47.106 50.665 ;
     RECT  47.844 50.459 48.006 50.665 ;
     RECT  0.18 49.855 0.558 50.669 ;
     RECT  0.18 50.669 0.27 50.717 ;
     RECT  16.632 50.315 30.834 51.061 ;
     RECT  2.304 50.423 15.894 51.205 ;
     RECT  16.632 51.061 30.942 51.205 ;
     RECT  2.304 51.205 30.942 51.367 ;
     RECT  2.268 51.367 30.942 51.395 ;
     RECT  16.848 51.395 30.942 51.403 ;
     RECT  31.716 50.665 48.006 51.403 ;
     RECT  48.888 50.477 49.014 51.403 ;
     RECT  16.848 51.403 48.006 51.499 ;
     RECT  48.888 51.403 49.59 51.499 ;
     RECT  2.268 51.395 16.038 51.533 ;
     RECT  0.252 50.717 0.27 51.781 ;
     RECT  0.252 51.781 0.558 51.979 ;
     RECT  0.216 51.979 0.558 52.267 ;
     RECT  2.304 51.533 16.038 52.363 ;
     RECT  16.848 51.499 49.59 52.363 ;
     RECT  2.304 52.363 49.59 52.411 ;
     RECT  0.18 52.267 0.558 52.717 ;
     RECT  0.108 52.717 0.558 52.973 ;
     RECT  2.268 52.411 49.59 52.979 ;
     RECT  0.108 52.973 0.522 53.069 ;
     RECT  2.268 52.979 48.438 53.249 ;
     RECT  20.52 53.249 48.438 53.285 ;
     RECT  0.108 53.069 0.126 53.453 ;
     RECT  20.556 53.285 48.438 53.519 ;
     RECT  20.556 53.519 48.402 53.555 ;
     RECT  49.464 52.979 49.59 53.803 ;
     RECT  2.268 53.249 19.674 53.905 ;
     RECT  28.476 53.555 48.402 53.981 ;
     RECT  38.412 53.981 48.402 54.059 ;
     RECT  2.232 53.905 19.674 54.103 ;
     RECT  20.556 53.555 27.522 54.103 ;
     RECT  28.476 53.981 37.674 54.131 ;
     RECT  38.484 54.059 48.402 54.283 ;
     RECT  49.428 53.803 49.59 54.283 ;
     RECT  2.232 54.103 27.522 54.365 ;
     RECT  1.404 54.283 1.422 54.475 ;
     RECT  2.232 54.365 19.134 54.475 ;
     RECT  19.908 54.365 27.522 54.557 ;
     RECT  28.476 54.131 35.514 54.571 ;
     RECT  19.944 54.557 27.522 54.715 ;
     RECT  28.332 54.571 35.514 54.715 ;
     RECT  36.36 54.131 37.674 54.841 ;
     RECT  38.484 54.283 49.59 54.841 ;
     RECT  36.36 54.841 49.59 54.977 ;
     RECT  19.944 54.715 35.514 54.985 ;
     RECT  36.36 54.977 37.35 54.985 ;
     RECT  19.944 54.985 37.35 54.989 ;
     RECT  1.404 54.475 19.134 55.283 ;
     RECT  16.992 55.283 19.134 55.291 ;
     RECT  16.992 55.291 19.206 55.381 ;
     RECT  19.944 54.989 31.554 55.381 ;
     RECT  16.992 55.381 31.554 55.409 ;
     RECT  0.108 55.627 0.126 55.675 ;
     RECT  16.992 55.409 21.726 55.715 ;
     RECT  0.108 55.675 0.198 55.915 ;
     RECT  0.108 55.915 0.342 55.916 ;
     RECT  22.572 55.409 31.554 55.921 ;
     RECT  32.4 54.989 37.35 55.921 ;
     RECT  38.16 54.977 49.59 55.921 ;
     RECT  1.404 55.283 16.182 56.101 ;
     RECT  22.572 55.921 49.59 56.129 ;
     RECT  0.18 55.916 0.342 56.203 ;
     RECT  17.496 55.715 21.726 56.219 ;
     RECT  31.392 56.129 49.59 56.219 ;
     RECT  20.448 56.219 21.726 56.227 ;
     RECT  22.572 56.129 30.438 56.227 ;
     RECT  31.392 56.219 32.562 56.255 ;
     RECT  0.18 56.203 0.378 56.285 ;
     RECT  20.448 56.227 30.438 56.291 ;
     RECT  0.216 56.285 0.378 56.333 ;
     RECT  0.216 56.333 0.306 56.399 ;
     RECT  0.216 56.399 0.234 56.429 ;
     RECT  1.404 56.101 16.614 56.461 ;
     RECT  17.496 56.219 19.566 56.461 ;
     RECT  21.672 56.291 30.438 56.759 ;
     RECT  1.404 56.461 19.566 56.795 ;
     RECT  21.672 56.759 26.946 56.795 ;
     RECT  33.444 56.219 49.59 56.795 ;
     RECT  27.972 56.759 30.438 56.875 ;
     RECT  31.392 56.255 32.31 56.875 ;
     RECT  21.672 56.795 22.014 56.939 ;
     RECT  22.788 56.795 26.946 56.939 ;
     RECT  20.448 56.291 20.826 57.019 ;
     RECT  27.972 56.875 32.31 57.037 ;
     RECT  33.444 56.795 35.91 57.037 ;
     RECT  36.648 56.795 49.59 57.053 ;
     RECT  21.672 56.939 21.978 57.073 ;
     RECT  20.34 57.019 20.826 57.181 ;
     RECT  21.564 57.073 21.978 57.181 ;
     RECT  27.972 57.037 35.91 57.293 ;
     RECT  33.12 57.293 35.91 57.335 ;
     RECT  38.124 57.053 49.59 57.335 ;
     RECT  38.124 57.335 38.718 57.407 ;
     RECT  1.728 56.795 19.566 57.415 ;
     RECT  20.34 57.181 21.978 57.415 ;
     RECT  22.788 56.939 26.406 57.479 ;
     RECT  27.972 57.293 32.31 57.541 ;
     RECT  39.492 57.335 49.59 57.547 ;
     RECT  27.36 57.541 32.31 57.569 ;
     RECT  33.48 57.335 35.91 57.569 ;
     RECT  1.728 57.415 21.978 57.605 ;
     RECT  22.788 57.479 25.434 57.605 ;
     RECT  27.36 57.569 32.13 57.605 ;
     RECT  22.788 57.605 24.39 57.641 ;
     RECT  33.516 57.569 35.91 57.677 ;
     RECT  1.728 57.605 21.366 57.713 ;
     RECT  22.788 57.641 24.297 57.721 ;
     RECT  27.36 57.605 31.59 57.721 ;
     RECT  22.716 57.721 24.297 57.749 ;
     RECT  36.648 57.053 37.386 57.749 ;
     RECT  22.716 57.749 23.166 57.811 ;
     RECT  22.536 57.811 23.166 57.839 ;
     RECT  1.728 57.713 11.43 57.875 ;
     RECT  12.168 57.713 21.366 57.911 ;
     RECT  26.424 57.721 31.59 57.911 ;
     RECT  39.492 57.547 49.626 57.911 ;
     RECT  22.536 57.839 23.058 57.917 ;
     RECT  22.644 57.917 23.058 57.92 ;
     RECT  1.728 57.875 9.774 57.983 ;
     RECT  34.632 57.677 35.91 57.991 ;
     RECT  36.648 57.749 36.81 57.991 ;
     RECT  15.084 57.911 21.366 58.019 ;
     RECT  33.516 57.677 33.714 58.019 ;
     RECT  34.632 57.991 36.81 58.019 ;
     RECT  39.492 57.911 47.322 58.019 ;
     RECT  9.144 57.983 9.774 58.109 ;
     RECT  10.548 57.875 11.43 58.109 ;
     RECT  12.168 57.911 14.274 58.109 ;
     RECT  15.084 58.019 16.218 58.109 ;
     RECT  25.128 57.605 25.434 58.109 ;
     RECT  35.964 58.019 36.81 58.109 ;
     RECT  41.364 58.019 47.322 58.109 ;
     RECT  16.992 58.019 21.366 58.124 ;
     RECT  9.576 58.109 9.702 58.145 ;
     RECT  10.62 58.109 11.43 58.145 ;
     RECT  15.084 58.109 16.002 58.145 ;
     RECT  22.644 57.92 23.022 58.145 ;
     RECT  26.424 57.911 28.242 58.145 ;
     RECT  34.632 58.019 35.19 58.145 ;
     RECT  36.648 58.109 36.666 58.145 ;
     RECT  38.16 57.407 38.718 58.145 ;
     RECT  16.992 58.124 21.33 58.253 ;
     RECT  26.424 58.145 27.666 58.253 ;
     RECT  29.268 57.911 31.59 58.289 ;
     RECT  1.728 57.983 8.154 58.379 ;
     RECT  15.48 58.145 16.002 58.379 ;
     RECT  22.788 58.145 23.022 58.379 ;
     RECT  26.424 58.253 27.378 58.379 ;
     RECT  29.268 58.289 31.374 58.379 ;
     RECT  33.516 58.019 33.606 58.379 ;
     RECT  37.728 58.261 37.89 58.379 ;
     RECT  1.728 58.379 6.282 58.415 ;
     RECT  7.164 58.379 8.097 58.415 ;
     RECT  9.684 58.145 9.702 58.415 ;
     RECT  10.836 58.145 11.43 58.415 ;
     RECT  12.276 58.109 14.274 58.415 ;
     RECT  15.984 58.379 16.002 58.415 ;
     RECT  17.64 58.253 21.33 58.415 ;
     RECT  23.94 57.749 24.297 58.415 ;
     RECT  26.424 58.379 26.514 58.415 ;
     RECT  27.36 58.379 27.378 58.415 ;
     RECT  29.415 58.379 31.338 58.415 ;
     RECT  33.588 58.379 33.606 58.415 ;
     RECT  37.728 58.379 37.746 58.415 ;
     RECT  39.492 58.019 40.626 58.415 ;
     RECT  41.544 58.109 47.322 58.415 ;
     RECT  17.784 58.415 19.926 58.451 ;
     RECT  22.86 58.379 23.022 58.451 ;
     RECT  39.744 58.415 40.626 58.487 ;
     RECT  23.976 58.415 24.297 58.531 ;
     RECT  34.632 58.145 35.097 58.531 ;
     RECT  5.328 58.415 6.282 58.559 ;
     RECT  11.412 58.415 11.43 58.559 ;
     RECT  12.636 58.415 14.274 58.559 ;
     RECT  38.772 58.459 38.79 58.559 ;
     RECT  1.764 58.415 4.446 58.649 ;
     RECT  5.328 58.559 5.49 58.649 ;
     RECT  6.264 58.559 6.282 58.649 ;
     RECT  13.176 58.559 14.274 58.649 ;
     RECT  17.784 58.451 19.386 58.649 ;
     RECT  21.312 58.415 21.33 58.649 ;
     RECT  22.86 58.451 22.878 58.649 ;
     RECT  25.848 58.495 25.866 58.649 ;
     RECT  29.415 58.415 30.222 58.649 ;
     RECT  31.32 58.415 31.338 58.649 ;
     RECT  42.192 58.415 47.322 58.649 ;
     RECT  1.764 58.649 4.194 58.685 ;
     RECT  5.328 58.649 5.346 58.685 ;
     RECT  13.176 58.649 13.986 58.685 ;
     RECT  17.784 58.649 18.99 58.685 ;
     RECT  23.976 58.531 24.894 58.685 ;
     RECT  34.452 58.531 35.097 58.685 ;
     RECT  42.192 58.649 42.21 58.685 ;
     RECT  43.308 58.649 47.322 58.685 ;
     RECT  43.416 58.685 47.322 58.729 ;
     RECT  43.416 58.729 47.394 58.793 ;
     RECT  1.764 58.685 3.222 58.919 ;
     RECT  4.176 58.685 4.194 58.919 ;
     RECT  17.784 58.685 17.802 58.919 ;
     RECT  48.132 57.911 49.626 58.919 ;
     RECT  1.764 58.919 3.114 59.189 ;
     RECT  48.348 58.919 49.626 59.189 ;
     RECT  1.764 59.189 2.898 59.225 ;
     RECT  1.836 59.225 2.754 59.459 ;
     RECT  39.744 58.487 40.497 59.459 ;
     RECT  1.836 59.459 2.697 59.495 ;
     RECT  43.776 58.793 47.394 59.575 ;
     RECT  43.668 59.575 47.394 59.729 ;
     RECT  43.668 59.729 44.766 59.837 ;
     RECT  44.388 59.837 44.766 59.909 ;
     RECT  44.388 59.909 44.658 59.999 ;
     RECT  44.64 59.999 44.658 60.035 ;
     RECT  48.708 59.189 49.626 60.179 ;
     RECT  48.708 60.179 49.41 60.413 ;
     RECT  45.615 59.729 47.394 60.575 ;
     RECT  45.615 60.575 46.386 60.719 ;
     RECT  48.708 60.413 48.726 60.719 ;
     RECT  47.376 60.575 47.394 60.845 ;
     RECT  45.615 60.719 46.098 60.989 ;
     RECT  2.415 59.495 2.697 62.387 ;
     RECT  7.815 58.415 8.097 62.387 ;
     RECT  13.215 58.685 13.497 62.387 ;
     RECT  18.615 58.685 18.897 62.387 ;
     RECT  24.015 58.685 24.297 62.387 ;
     RECT  29.415 58.649 29.697 62.387 ;
     RECT  34.815 58.685 35.097 62.387 ;
     RECT  40.215 59.459 40.497 62.387 ;
     RECT  45.615 60.989 45.897 62.387 ;
     RECT  2.415 62.387 2.505 62.657 ;
     RECT  7.815 62.387 7.905 62.657 ;
     RECT  13.215 62.387 13.305 62.657 ;
     RECT  18.615 62.387 18.705 62.657 ;
     RECT  24.015 62.387 24.105 62.657 ;
     RECT  29.415 62.387 29.505 62.657 ;
     RECT  34.815 62.387 34.905 62.657 ;
     RECT  40.215 62.387 40.305 62.657 ;
     RECT  45.615 62.387 45.705 62.657 ;
    LAYER M4 ;
     RECT  0.06 7.248 2.408 57.864 ;
     RECT  2.408 2.148 2.512 62.652 ;
     RECT  2.512 2.418 2.704 62.382 ;
     RECT  2.704 7.248 2.801 58.536 ;
     RECT  2.801 7.248 2.837 58.44 ;
     RECT  2.837 7.248 3.377 58.2 ;
     RECT  3.377 7.248 3.413 54.264 ;
     RECT  3.413 7.248 3.697 54.168 ;
     RECT  3.697 6.816 3.836 54.168 ;
     RECT  3.836 6.72 3.923 54.168 ;
     RECT  3.377 55.248 4.241 58.2 ;
     RECT  3.923 6.816 4.349 54.168 ;
     RECT  4.349 21.552 4.453 54.168 ;
     RECT  4.241 55.248 4.453 58.152 ;
     RECT  4.453 21.552 4.501 58.152 ;
     RECT  4.349 6.816 4.673 20.472 ;
     RECT  4.501 21.552 4.781 57.528 ;
     RECT  4.673 7.248 4.889 20.472 ;
     RECT  4.889 7.248 5.141 20.232 ;
     RECT  4.781 21.552 5.389 27.336 ;
     RECT  5.141 7.824 5.857 20.232 ;
     RECT  5.389 21.504 5.857 27.336 ;
     RECT  5.857 7.824 5.891 27.336 ;
     RECT  4.781 28.416 6.073 57.528 ;
     RECT  5.891 7.824 6.077 27.144 ;
     RECT  6.037 6.816 6.217 6.84 ;
     RECT  6.077 7.824 6.217 25.176 ;
     RECT  6.073 28.176 6.253 57.528 ;
     RECT  6.253 28.176 6.365 58.152 ;
     RECT  6.365 28.176 6.401 54.552 ;
     RECT  6.401 28.176 6.797 54.408 ;
     RECT  6.365 55.536 7.153 58.152 ;
     RECT  6.797 52.8 7.477 54.408 ;
     RECT  7.153 55.536 7.477 58.392 ;
     RECT  6.217 6.816 7.549 25.176 ;
     RECT  6.077 26.16 7.549 27.144 ;
     RECT  7.549 6.816 7.808 27.144 ;
     RECT  6.797 28.176 7.808 51.384 ;
     RECT  7.477 52.8 7.808 58.392 ;
     RECT  7.808 2.148 7.912 62.652 ;
     RECT  7.912 2.418 8.104 62.382 ;
     RECT  8.104 28.32 8.129 54.696 ;
     RECT  8.104 9.504 8.165 14.712 ;
     RECT  8.104 15.984 8.201 26.856 ;
     RECT  8.201 15.984 8.273 26.808 ;
     RECT  8.165 10.8 8.741 14.712 ;
     RECT  8.273 15.984 8.813 25.032 ;
     RECT  8.129 30.048 9.029 54.696 ;
     RECT  8.104 7.2 9.097 7.224 ;
     RECT  8.813 17.088 9.1 25.032 ;
     RECT  8.129 28.32 9.137 28.968 ;
     RECT  8.104 56.352 9.169 57.912 ;
     RECT  8.273 26.16 9.205 26.808 ;
     RECT  9.029 30.048 9.245 39.576 ;
     RECT  9.029 40.944 9.277 54.696 ;
     RECT  9.245 30.144 9.317 39.576 ;
     RECT  9.277 40.944 9.349 55.128 ;
     RECT  9.169 56.352 9.349 58.056 ;
     RECT  9.1 21.456 9.385 25.032 ;
     RECT  9.205 26.16 9.385 27.048 ;
     RECT  8.813 15.984 9.421 16.104 ;
     RECT  9.349 40.944 9.493 58.056 ;
     RECT  9.317 38.16 9.677 39.576 ;
     RECT  9.677 38.16 9.731 39.432 ;
     RECT  8.741 11.232 9.925 14.712 ;
     RECT  9.097 7.2 10.069 7.848 ;
     RECT  9.421 15.84 10.105 16.104 ;
     RECT  9.1 17.088 10.105 20.184 ;
     RECT  9.385 21.456 10.105 27.048 ;
     RECT  9.317 30.144 10.109 36.936 ;
     RECT  8.165 9.504 10.141 9.816 ;
     RECT  10.069 6.816 10.153 7.848 ;
     RECT  10.141 9.504 10.177 10.152 ;
     RECT  10.105 21.456 10.177 27.24 ;
     RECT  9.493 40.944 10.177 58.104 ;
     RECT  10.177 21.456 10.213 27.336 ;
     RECT  9.137 28.32 10.213 28.776 ;
     RECT  10.177 9.504 10.259 10.248 ;
     RECT  10.105 15.84 10.285 20.184 ;
     RECT  10.213 21.456 10.285 28.776 ;
     RECT  10.109 30.144 10.285 33.768 ;
     RECT  10.177 40.416 10.289 58.104 ;
     RECT  10.285 15.84 10.505 33.768 ;
     RECT  10.505 15.84 10.541 27.336 ;
     RECT  10.259 9.6 10.685 10.248 ;
     RECT  10.109 35.184 10.691 36.936 ;
     RECT  9.731 38.16 10.789 39.048 ;
     RECT  10.289 40.416 10.789 55.272 ;
     RECT  10.685 9.648 10.885 10.248 ;
     RECT  9.925 11.232 10.885 14.856 ;
     RECT  10.885 9.648 10.901 14.856 ;
     RECT  10.691 36.432 10.901 36.936 ;
     RECT  10.289 56.4 10.901 58.104 ;
     RECT  10.901 9.648 10.931 14.232 ;
     RECT  10.505 28.32 10.937 33.768 ;
     RECT  10.901 36.48 10.969 36.936 ;
     RECT  10.789 38.16 10.969 55.272 ;
     RECT  10.901 56.4 10.979 57.912 ;
     RECT  10.937 33.744 11.221 33.768 ;
     RECT  10.979 56.88 11.225 57.912 ;
     RECT  10.969 36.48 11.261 55.272 ;
     RECT  10.541 15.984 11.333 27.336 ;
     RECT  10.153 7.2 11.365 7.848 ;
     RECT  11.333 15.984 11.369 26.76 ;
     RECT  11.261 36.48 11.405 49.56 ;
     RECT  11.365 6.816 11.452 7.848 ;
     RECT  11.221 33.744 11.581 34.008 ;
     RECT  10.691 35.184 11.581 35.4 ;
     RECT  11.261 50.592 11.581 55.272 ;
     RECT  11.369 15.984 11.689 20.136 ;
     RECT  11.369 21.12 11.693 26.76 ;
     RECT  11.581 50.592 11.765 55.848 ;
     RECT  10.937 28.32 11.905 32.472 ;
     RECT  11.765 53.568 11.909 55.848 ;
     RECT  11.909 53.856 11.945 55.848 ;
     RECT  11.905 28.176 11.977 32.472 ;
     RECT  11.977 28.176 11.981 32.52 ;
     RECT  11.405 36.528 12.017 49.56 ;
     RECT  11.765 50.592 12.089 52.2 ;
     RECT  11.981 29.616 12.229 32.52 ;
     RECT  11.581 33.744 12.229 35.4 ;
     RECT  12.229 29.616 12.233 35.4 ;
     RECT  11.945 54.096 12.373 55.848 ;
     RECT  11.225 56.88 12.373 57.576 ;
     RECT  10.931 10.128 12.409 14.232 ;
     RECT  11.689 15.312 12.409 20.136 ;
     RECT  12.233 31.92 12.517 35.4 ;
     RECT  12.017 36.528 12.517 42.792 ;
     RECT  12.373 54.096 12.553 57.576 ;
     RECT  11.581 8.448 12.661 8.472 ;
     RECT  11.693 21.456 12.805 26.76 ;
     RECT  11.452 6.816 13.021 6.84 ;
     RECT  12.553 54.096 13.021 57.624 ;
     RECT  12.409 10.128 13.057 20.136 ;
     RECT  12.805 21.168 13.057 26.76 ;
     RECT  12.517 31.92 13.085 42.792 ;
     RECT  13.085 31.92 13.093 42.936 ;
     RECT  11.981 28.176 13.129 28.44 ;
     RECT  12.233 29.616 13.129 30.696 ;
     RECT  13.057 10.128 13.165 26.76 ;
     RECT  13.129 28.176 13.201 30.696 ;
     RECT  13.093 31.92 13.201 43.032 ;
     RECT  13.021 6.816 13.208 7.224 ;
     RECT  12.661 8.448 13.208 8.52 ;
     RECT  13.165 9.6 13.208 26.76 ;
     RECT  13.201 28.176 13.208 43.032 ;
     RECT  12.017 44.064 13.208 49.56 ;
     RECT  12.089 50.736 13.208 52.2 ;
     RECT  13.021 53.52 13.208 57.624 ;
     RECT  13.208 2.148 13.312 62.652 ;
     RECT  13.312 2.418 13.504 62.382 ;
     RECT  13.504 14.688 13.745 19.8 ;
     RECT  13.504 29.472 13.781 48.456 ;
     RECT  13.781 29.472 13.817 47.88 ;
     RECT  13.504 8.496 13.853 13.704 ;
     RECT  13.504 49.488 14.285 53.832 ;
     RECT  14.285 49.488 14.357 52.728 ;
     RECT  14.285 53.808 14.357 53.832 ;
     RECT  13.504 55.056 14.465 55.56 ;
     RECT  13.504 57.264 14.537 57.72 ;
     RECT  13.504 20.976 14.677 28.2 ;
     RECT  13.504 7.2 14.681 7.224 ;
     RECT  13.817 34.656 14.785 47.88 ;
     RECT  14.357 49.488 14.785 49.8 ;
     RECT  13.817 29.472 14.893 33.528 ;
     RECT  14.465 55.248 14.893 55.56 ;
     RECT  13.853 9.216 15.073 13.704 ;
     RECT  14.713 53.952 15.073 53.976 ;
     RECT  14.677 20.544 15.145 28.2 ;
     RECT  14.893 29.472 15.145 33.576 ;
     RECT  14.893 55.248 15.185 55.944 ;
     RECT  15.073 8.544 15.221 13.704 ;
     RECT  15.145 20.544 15.26 33.576 ;
     RECT  14.785 34.656 15.26 49.8 ;
     RECT  15.26 20.544 15.325 49.8 ;
     RECT  15.325 20.352 15.347 49.8 ;
     RECT  13.745 14.688 15.401 19.368 ;
     RECT  15.347 34.656 15.437 49.8 ;
     RECT  15.221 11.232 15.505 13.704 ;
     RECT  15.401 14.688 15.505 15.096 ;
     RECT  14.537 57.264 15.505 57.624 ;
     RECT  15.073 53.952 15.541 54.072 ;
     RECT  15.505 57.024 15.589 57.624 ;
     RECT  15.221 8.544 15.613 10.056 ;
     RECT  15.589 57.36 15.617 57.624 ;
     RECT  15.541 53.952 15.793 54.12 ;
     RECT  15.505 11.232 15.797 15.096 ;
     RECT  15.401 16.224 15.941 19.368 ;
     RECT  15.185 55.248 16.157 55.56 ;
     RECT  15.613 8.496 16.261 10.056 ;
     RECT  15.797 11.232 16.261 14.856 ;
     RECT  16.261 8.496 16.333 14.856 ;
     RECT  14.357 50.784 16.333 52.728 ;
     RECT  15.793 53.952 16.333 54.168 ;
     RECT  15.941 16.224 16.403 19.32 ;
     RECT  15.347 20.352 16.477 33.576 ;
     RECT  15.437 34.656 16.477 49.608 ;
     RECT  16.477 20.352 16.517 49.608 ;
     RECT  16.333 50.784 16.549 54.168 ;
     RECT  16.157 55.248 16.549 55.416 ;
     RECT  16.517 20.352 16.553 37.992 ;
     RECT  16.517 39.024 16.621 49.608 ;
     RECT  16.549 50.784 16.621 55.416 ;
     RECT  16.333 7.92 16.841 14.856 ;
     RECT  16.403 16.368 16.945 19.32 ;
     RECT  16.621 39.024 17.201 55.416 ;
     RECT  17.201 53.952 17.237 55.416 ;
     RECT  16.945 16.368 17.273 19.368 ;
     RECT  16.841 7.92 17.345 13.56 ;
     RECT  16.841 14.64 17.345 14.856 ;
     RECT  16.553 31.968 17.489 37.992 ;
     RECT  17.273 16.368 17.521 17.688 ;
     RECT  15.617 57.36 17.557 57.384 ;
     RECT  16.553 20.352 17.593 30.888 ;
     RECT  17.489 31.968 17.593 33.144 ;
     RECT  17.557 56.928 17.629 57.384 ;
     RECT  17.489 34.368 17.653 37.992 ;
     RECT  17.201 39.024 17.653 52.488 ;
     RECT  17.521 16.032 17.989 17.688 ;
     RECT  17.273 18.72 18.097 19.368 ;
     RECT  17.593 20.352 18.097 33.144 ;
     RECT  17.345 14.688 18.421 14.856 ;
     RECT  17.345 8.496 18.457 13.56 ;
     RECT  18.421 14.688 18.457 14.952 ;
     RECT  17.989 15.984 18.457 17.688 ;
     RECT  17.653 34.368 18.565 52.488 ;
     RECT  17.237 53.952 18.565 55.128 ;
     RECT  18.457 8.496 18.608 17.688 ;
     RECT  18.097 18.72 18.608 33.144 ;
     RECT  18.565 34.368 18.608 55.128 ;
     RECT  17.629 56.4 18.608 57.384 ;
     RECT  18.608 2.148 18.712 62.652 ;
     RECT  18.712 2.418 18.904 62.382 ;
     RECT  18.904 40.32 18.929 49.608 ;
     RECT  18.904 7.728 19.181 17.736 ;
     RECT  18.904 50.64 19.289 50.664 ;
     RECT  18.929 40.32 19.427 49.464 ;
     RECT  19.427 47.856 19.468 49.464 ;
     RECT  18.904 18.768 19.505 39.336 ;
     RECT  19.427 40.32 19.505 46.872 ;
     RECT  19.505 40.416 19.613 46.872 ;
     RECT  18.904 52.176 19.897 57.384 ;
     RECT  19.181 7.92 19.909 17.736 ;
     RECT  19.505 18.768 19.909 24.264 ;
     RECT  19.897 52.032 19.909 57.384 ;
     RECT  19.505 25.296 19.955 39.336 ;
     RECT  19.613 40.464 19.973 46.872 ;
     RECT  19.909 51.648 20.041 57.384 ;
     RECT  19.955 25.296 20.117 37.944 ;
     RECT  20.041 50.832 20.149 57.384 ;
     RECT  20.117 36.432 20.261 37.944 ;
     RECT  19.955 38.976 20.369 39.336 ;
     RECT  20.149 50.832 20.369 57.576 ;
     RECT  19.468 47.952 20.401 49.464 ;
     RECT  20.117 25.296 20.441 35.448 ;
     RECT  20.401 47.952 20.509 49.656 ;
     RECT  20.369 51.648 20.513 57.576 ;
     RECT  19.909 7.92 20.549 24.264 ;
     RECT  20.549 8.928 20.729 24.264 ;
     RECT  19.973 40.464 20.761 46.68 ;
     RECT  20.513 51.648 20.765 56.472 ;
     RECT  20.765 53.712 20.801 56.472 ;
     RECT  20.441 25.776 20.909 35.448 ;
     RECT  20.761 40.368 20.941 46.68 ;
     RECT  20.509 47.712 20.941 49.656 ;
     RECT  20.261 36.48 20.977 37.944 ;
     RECT  20.369 38.976 20.977 39.192 ;
     RECT  20.729 13.44 20.981 24.264 ;
     RECT  20.981 14.688 21.049 24.264 ;
     RECT  21.049 14.688 21.197 24.792 ;
     RECT  20.513 57.552 21.301 57.576 ;
     RECT  20.765 51.648 21.337 52.488 ;
     RECT  20.941 7.872 21.341 7.896 ;
     RECT  20.941 40.368 21.341 49.656 ;
     RECT  21.301 57.552 21.385 58.152 ;
     RECT  21.197 14.88 21.481 24.792 ;
     RECT  20.909 25.776 21.481 35.256 ;
     RECT  20.977 36.48 21.481 39.192 ;
     RECT  21.385 57.552 21.553 57.576 ;
     RECT  20.729 8.928 21.625 12.456 ;
     RECT  21.481 36.48 21.665 39.336 ;
     RECT  20.801 53.712 21.737 56.28 ;
     RECT  21.737 53.712 21.788 55.944 ;
     RECT  21.341 40.368 21.809 47.208 ;
     RECT  21.553 57.36 21.841 57.576 ;
     RECT  21.809 40.368 21.917 46.728 ;
     RECT  21.341 48.192 22.021 49.656 ;
     RECT  21.337 51.36 22.021 52.488 ;
     RECT  21.481 14.88 22.057 35.256 ;
     RECT  22.021 48.192 22.165 52.488 ;
     RECT  21.788 53.52 22.165 55.944 ;
     RECT  22.057 14.88 22.273 35.304 ;
     RECT  21.665 36.48 22.273 36.504 ;
     RECT  22.165 48.192 22.345 55.944 ;
     RECT  22.273 14.88 22.349 36.504 ;
     RECT  21.665 37.536 22.421 39.336 ;
     RECT  21.625 8.496 22.493 12.456 ;
     RECT  21.841 57.12 22.525 57.576 ;
     RECT  22.349 20.496 22.54 36.504 ;
     RECT  22.421 37.584 22.565 39.336 ;
     RECT  20.981 13.44 22.669 13.56 ;
     RECT  22.349 14.88 22.669 19.464 ;
     RECT  21.917 40.464 22.673 46.728 ;
     RECT  22.673 40.608 22.777 46.728 ;
     RECT  22.345 47.76 22.777 55.944 ;
     RECT  21.985 7.344 22.781 7.512 ;
     RECT  22.669 13.44 22.813 19.464 ;
     RECT  22.777 40.608 22.813 55.944 ;
     RECT  22.525 57.12 22.813 57.912 ;
     RECT  22.565 37.584 22.997 38.568 ;
     RECT  22.813 40.608 22.997 57.912 ;
     RECT  22.781 7.488 23.209 7.512 ;
     RECT  22.493 8.496 23.209 12.312 ;
     RECT  22.997 37.584 23.461 38.472 ;
     RECT  23.209 7.488 23.497 12.312 ;
     RECT  22.813 13.296 23.497 19.464 ;
     RECT  22.54 20.496 23.641 35.736 ;
     RECT  23.461 37.056 23.641 38.472 ;
     RECT  23.497 7.488 23.821 19.464 ;
     RECT  23.641 20.496 23.821 38.472 ;
     RECT  23.821 7.488 24.008 38.472 ;
     RECT  22.997 40.608 24.008 56.328 ;
     RECT  22.997 57.888 24.008 57.912 ;
     RECT  24.008 2.148 24.112 62.652 ;
     RECT  24.112 2.418 24.304 62.382 ;
     RECT  24.304 7.488 24.365 17.112 ;
     RECT  24.304 18.096 24.437 57.336 ;
     RECT  24.437 18.096 24.869 53.064 ;
     RECT  24.365 7.488 25.121 16.968 ;
     RECT  25.121 14.784 25.369 16.968 ;
     RECT  25.369 14.784 25.477 17.064 ;
     RECT  24.869 18.096 25.477 26.664 ;
     RECT  24.437 54.096 25.523 57.336 ;
     RECT  25.121 7.488 25.661 13.8 ;
     RECT  25.477 14.784 25.661 26.664 ;
     RECT  24.869 27.792 25.733 53.064 ;
     RECT  25.523 54.576 25.769 57.336 ;
     RECT  25.661 18.72 25.841 26.664 ;
     RECT  25.733 27.792 25.877 46.248 ;
     RECT  25.877 28.992 26.021 46.248 ;
     RECT  26.021 37.584 26.243 46.248 ;
     RECT  25.661 7.536 26.309 13.8 ;
     RECT  25.733 50.64 26.309 53.064 ;
     RECT  26.021 28.992 26.345 36.408 ;
     RECT  26.243 40.992 26.345 46.248 ;
     RECT  26.309 13.68 26.413 13.8 ;
     RECT  25.661 14.784 26.413 17.544 ;
     RECT  25.841 18.768 26.449 26.664 ;
     RECT  25.877 27.792 26.449 27.864 ;
     RECT  26.413 13.68 26.597 17.544 ;
     RECT  25.733 47.28 26.773 49.656 ;
     RECT  26.309 50.64 26.773 50.808 ;
     RECT  26.597 13.68 26.777 13.8 ;
     RECT  26.309 51.936 26.809 53.064 ;
     RECT  26.449 18.768 26.813 27.864 ;
     RECT  26.345 41.232 26.881 46.248 ;
     RECT  26.773 47.28 26.881 50.808 ;
     RECT  26.345 28.992 26.885 36.264 ;
     RECT  26.597 14.976 26.989 17.544 ;
     RECT  26.813 18.768 26.989 27.288 ;
     RECT  26.885 28.992 26.989 34.824 ;
     RECT  26.809 51.936 27.097 53.208 ;
     RECT  26.243 37.584 27.205 39.768 ;
     RECT  26.989 14.976 27.245 27.288 ;
     RECT  26.309 9.6 27.301 12.312 ;
     RECT  26.881 41.232 27.313 50.808 ;
     RECT  27.097 51.936 27.313 53.256 ;
     RECT  25.769 54.576 27.313 56.616 ;
     RECT  27.301 9.552 27.341 12.312 ;
     RECT  26.885 36.192 27.385 36.264 ;
     RECT  27.205 37.584 27.385 39.864 ;
     RECT  27.245 15.168 27.389 27.288 ;
     RECT  26.989 28.944 27.389 34.824 ;
     RECT  27.389 15.168 27.461 26.088 ;
     RECT  26.777 13.68 27.497 13.704 ;
     RECT  27.385 36.192 27.529 39.864 ;
     RECT  27.313 54.576 27.533 56.712 ;
     RECT  27.313 41.232 27.569 53.256 ;
     RECT  27.461 15.168 27.677 24.648 ;
     RECT  27.389 28.944 27.709 34.632 ;
     RECT  27.389 27.264 27.713 27.288 ;
     RECT  26.309 7.536 27.745 8.568 ;
     RECT  27.677 15.168 27.785 24.456 ;
     RECT  27.569 41.232 27.857 52.872 ;
     RECT  27.857 41.232 27.893 50.808 ;
     RECT  27.893 45.984 27.929 50.808 ;
     RECT  27.857 52.224 27.965 52.872 ;
     RECT  27.533 55.296 28.073 56.712 ;
     RECT  27.529 36.192 28.109 39.912 ;
     RECT  28.109 36.192 28.141 37.08 ;
     RECT  28.109 38.208 28.145 39.912 ;
     RECT  27.785 15.168 28.213 23.928 ;
     RECT  27.745 7.44 28.316 8.568 ;
     RECT  27.341 9.552 28.316 12.552 ;
     RECT  27.709 28.512 28.321 34.632 ;
     RECT  28.073 55.296 28.325 56.616 ;
     RECT  28.316 7.44 28.405 12.552 ;
     RECT  28.141 36.048 28.465 37.08 ;
     RECT  27.461 25.68 28.501 26.088 ;
     RECT  28.321 27.84 28.537 34.632 ;
     RECT  28.465 35.76 28.537 37.08 ;
     RECT  28.325 55.296 28.861 56.376 ;
     RECT  28.213 14.496 28.933 23.928 ;
     RECT  27.929 45.984 28.969 46.152 ;
     RECT  27.929 47.232 28.969 50.808 ;
     RECT  28.969 45.984 29.041 50.808 ;
     RECT  27.965 52.224 29.041 52.488 ;
     RECT  28.861 54.48 29.041 56.376 ;
     RECT  28.501 25.68 29.185 26.76 ;
     RECT  28.145 38.208 29.221 38.76 ;
     RECT  28.145 39.744 29.221 39.912 ;
     RECT  28.933 13.68 29.257 23.928 ;
     RECT  29.185 24.912 29.257 26.76 ;
     RECT  28.537 27.84 29.293 37.08 ;
     RECT  29.221 38.208 29.293 39.912 ;
     RECT  29.257 13.68 29.365 26.76 ;
     RECT  29.293 27.84 29.365 39.912 ;
     RECT  28.405 7.392 29.401 12.552 ;
     RECT  29.365 13.68 29.401 39.912 ;
     RECT  29.401 7.392 29.408 39.912 ;
     RECT  27.893 41.232 29.408 44.952 ;
     RECT  29.041 45.984 29.408 50.904 ;
     RECT  29.041 51.936 29.408 52.488 ;
     RECT  29.041 54.096 29.408 56.376 ;
     RECT  28.033 57.936 29.408 57.96 ;
     RECT  29.408 2.148 29.512 62.652 ;
     RECT  29.512 2.418 29.704 62.382 ;
     RECT  29.704 40.992 29.765 57.864 ;
     RECT  29.704 7.44 29.837 25.464 ;
     RECT  29.765 43.296 29.843 57.864 ;
     RECT  29.837 9.552 29.891 25.464 ;
     RECT  29.891 9.552 30.701 24.936 ;
     RECT  29.704 26.496 30.701 39.864 ;
     RECT  30.701 17.856 30.737 24.936 ;
     RECT  29.837 7.44 30.769 8.52 ;
     RECT  29.843 43.296 30.773 57.576 ;
     RECT  29.765 40.992 30.845 42.216 ;
     RECT  30.773 43.296 30.845 49.608 ;
     RECT  30.701 26.496 30.881 37.464 ;
     RECT  30.845 41.232 30.949 42.216 ;
     RECT  30.845 43.296 30.949 49.032 ;
     RECT  30.949 41.232 30.995 49.032 ;
     RECT  30.769 7.392 31.025 8.52 ;
     RECT  30.701 38.496 31.097 39.864 ;
     RECT  30.737 18 31.133 24.936 ;
     RECT  31.133 18.096 31.141 24.936 ;
     RECT  30.881 26.496 31.165 27.336 ;
     RECT  30.773 51.072 31.205 57.576 ;
     RECT  31.025 7.632 31.309 8.52 ;
     RECT  30.701 9.552 31.309 16.824 ;
     RECT  31.141 18.096 31.309 25.08 ;
     RECT  31.097 38.496 31.421 39.768 ;
     RECT  31.309 7.632 31.741 16.824 ;
     RECT  30.881 28.32 31.745 37.464 ;
     RECT  31.165 26.352 31.885 27.336 ;
     RECT  31.741 7.632 31.889 16.92 ;
     RECT  30.995 41.232 31.889 41.256 ;
     RECT  30.995 42.72 31.961 49.032 ;
     RECT  31.745 28.944 31.997 37.464 ;
     RECT  31.997 29.04 32.029 37.464 ;
     RECT  31.421 38.496 32.029 39.384 ;
     RECT  31.205 51.072 32.029 57.48 ;
     RECT  31.889 7.632 32.033 16.296 ;
     RECT  32.033 7.632 32.093 8.52 ;
     RECT  32.029 50.16 32.14 57.48 ;
     RECT  32.093 7.392 32.177 8.52 ;
     RECT  31.309 18.096 32.245 25.272 ;
     RECT  32.029 29.04 32.285 39.384 ;
     RECT  32.14 57.264 32.321 57.48 ;
     RECT  32.245 17.52 32.461 25.272 ;
     RECT  31.885 26.352 32.461 27.624 ;
     RECT  32.14 50.16 32.573 55.848 ;
     RECT  31.961 42.72 32.609 48.936 ;
     RECT  32.321 57.264 32.645 57.288 ;
     RECT  32.033 9.552 32.893 16.296 ;
     RECT  32.461 17.52 32.893 27.624 ;
     RECT  32.285 29.04 32.897 39.288 ;
     RECT  32.897 30.432 32.933 39.288 ;
     RECT  32.893 9.552 33.013 27.624 ;
     RECT  32.933 30.432 33.059 38.808 ;
     RECT  32.177 7.632 33.077 8.52 ;
     RECT  32.677 41.088 33.077 41.112 ;
     RECT  33.013 9.552 33.185 27.912 ;
     RECT  33.077 7.728 33.289 8.52 ;
     RECT  33.289 7.728 33.433 8.568 ;
     RECT  33.185 9.552 33.433 24.936 ;
     RECT  33.145 50.016 33.577 50.04 ;
     RECT  32.573 51.072 33.577 55.848 ;
     RECT  32.609 42.72 33.721 44.952 ;
     RECT  33.185 26.352 33.829 27.912 ;
     RECT  32.897 29.04 33.829 29.4 ;
     RECT  32.609 46.08 34.045 48.84 ;
     RECT  33.577 50.016 34.045 55.848 ;
     RECT  33.721 42.24 34.081 44.952 ;
     RECT  34.081 42.192 34.117 44.952 ;
     RECT  34.045 46.08 34.117 55.848 ;
     RECT  33.145 40.944 34.225 41.064 ;
     RECT  34.117 42.192 34.225 55.848 ;
     RECT  33.829 26.352 34.369 29.4 ;
     RECT  34.225 40.944 34.369 55.848 ;
     RECT  34.369 40.368 34.585 55.848 ;
     RECT  33.433 7.728 34.729 24.936 ;
     RECT  33.829 6.672 34.808 6.696 ;
     RECT  34.729 7.68 34.808 24.936 ;
     RECT  34.369 26.256 34.808 29.4 ;
     RECT  33.059 30.432 34.808 38.76 ;
     RECT  34.585 40.368 34.808 56.52 ;
     RECT  34.808 2.148 34.912 62.652 ;
     RECT  34.912 2.418 35.104 62.382 ;
     RECT  35.104 7.68 35.345 29.064 ;
     RECT  35.345 7.68 35.363 28.728 ;
     RECT  35.363 7.68 35.417 23.736 ;
     RECT  35.363 24.912 35.453 28.728 ;
     RECT  35.417 7.68 35.597 23.688 ;
     RECT  35.597 9.648 35.987 23.688 ;
     RECT  35.104 35.568 36.133 39.096 ;
     RECT  35.104 42.192 36.133 55.272 ;
     RECT  35.104 56.496 36.133 57.048 ;
     RECT  35.104 40.368 36.181 40.968 ;
     RECT  36.133 35.472 36.205 39.096 ;
     RECT  36.181 40.368 36.205 41.112 ;
     RECT  35.104 30.432 36.229 34.2 ;
     RECT  36.205 35.472 36.229 41.112 ;
     RECT  36.229 30.432 36.413 41.112 ;
     RECT  36.133 42.144 36.419 57.048 ;
     RECT  36.419 42.144 36.467 48.792 ;
     RECT  36.413 29.664 36.497 41.112 ;
     RECT  36.419 49.872 36.533 57.048 ;
     RECT  36.497 30.192 36.569 41.112 ;
     RECT  36.467 43.872 36.569 48.792 ;
     RECT  36.533 49.872 36.641 55.8 ;
     RECT  35.597 7.68 36.709 8.184 ;
     RECT  35.987 10.128 36.713 23.688 ;
     RECT  36.569 30.192 36.713 39 ;
     RECT  36.713 16.896 36.749 23.688 ;
     RECT  36.713 30.576 36.857 39 ;
     RECT  36.709 7.344 36.889 8.184 ;
     RECT  36.641 49.872 36.893 53.544 ;
     RECT  36.749 23.184 36.899 23.688 ;
     RECT  36.899 23.28 36.997 23.688 ;
     RECT  35.453 24.912 36.997 28.68 ;
     RECT  36.569 40.368 37.001 41.112 ;
     RECT  36.893 49.872 37.001 53.256 ;
     RECT  36.889 7.344 37.033 8.52 ;
     RECT  37.033 6.384 37.141 8.52 ;
     RECT  37.141 6.384 37.289 9 ;
     RECT  36.641 54.576 37.289 55.8 ;
     RECT  36.569 43.872 37.361 48.456 ;
     RECT  37.001 40.368 37.537 41.064 ;
     RECT  37.289 54.576 37.649 54.6 ;
     RECT  37.361 46.752 37.681 48.456 ;
     RECT  37.681 46.752 37.825 48.504 ;
     RECT  36.749 16.896 37.897 22.2 ;
     RECT  36.533 57.024 37.933 57.048 ;
     RECT  37.289 6.384 37.973 8.856 ;
     RECT  37.897 16.56 38.005 22.2 ;
     RECT  36.997 23.28 38.005 28.68 ;
     RECT  38.005 16.56 38.041 28.68 ;
     RECT  36.713 10.128 38.077 15.576 ;
     RECT  38.041 16.56 38.077 29.064 ;
     RECT  37.537 39.888 38.077 41.064 ;
     RECT  36.467 42.144 38.077 42.792 ;
     RECT  38.077 10.128 38.081 29.064 ;
     RECT  37.825 46.752 38.113 48.792 ;
     RECT  37.001 49.872 38.113 52.968 ;
     RECT  38.081 10.32 38.125 29.064 ;
     RECT  36.857 30.576 38.149 38.76 ;
     RECT  38.077 39.888 38.149 42.792 ;
     RECT  37.361 43.872 38.149 45.528 ;
     RECT  38.149 30.576 38.243 45.528 ;
     RECT  38.243 30.576 38.257 42.744 ;
     RECT  37.933 56.4 38.293 57.048 ;
     RECT  38.293 56.4 38.401 57.768 ;
     RECT  38.243 43.728 38.437 45.528 ;
     RECT  38.113 46.752 38.437 52.968 ;
     RECT  38.149 53.952 38.437 53.976 ;
     RECT  38.401 56.4 38.545 58.056 ;
     RECT  38.545 55.728 38.729 58.056 ;
     RECT  38.125 10.32 38.873 28.488 ;
     RECT  37.973 7.344 38.977 8.856 ;
     RECT  38.437 43.728 38.977 53.976 ;
     RECT  38.729 55.728 38.977 57.144 ;
     RECT  38.977 43.728 39.053 57.144 ;
     RECT  38.257 30 39.265 42.744 ;
     RECT  39.053 43.728 39.265 55.752 ;
     RECT  38.873 10.32 39.481 17.112 ;
     RECT  39.265 30 39.625 55.752 ;
     RECT  38.873 18.48 39.913 27.768 ;
     RECT  39.625 29.088 39.913 55.752 ;
     RECT  38.977 7.344 40.129 9.096 ;
     RECT  39.481 10.176 40.129 17.112 ;
     RECT  40.129 7.344 40.165 17.112 ;
     RECT  39.913 18.48 40.165 55.752 ;
     RECT  40.165 7.344 40.208 55.752 ;
     RECT  39.053 57.024 40.208 57.144 ;
     RECT  40.208 2.148 40.312 62.652 ;
     RECT  40.312 2.418 40.504 62.382 ;
     RECT  40.504 6.672 40.643 55.464 ;
     RECT  40.643 8.448 40.673 55.464 ;
     RECT  40.673 8.496 41.075 55.464 ;
     RECT  40.504 56.928 41.677 57.048 ;
     RECT  41.075 23.088 41.749 55.464 ;
     RECT  41.677 56.928 41.749 57.48 ;
     RECT  41.075 8.496 42.109 22.056 ;
     RECT  41.749 23.088 42.109 57.48 ;
     RECT  40.504 5.664 42.145 5.688 ;
     RECT  40.643 6.672 42.145 6.84 ;
     RECT  42.109 7.968 42.22 57.48 ;
     RECT  42.145 5.664 42.284 6.84 ;
     RECT  42.22 7.968 42.284 54.696 ;
     RECT  42.284 5.664 42.371 54.696 ;
     RECT  42.371 8.496 42.46 54.696 ;
     RECT  42.371 5.664 42.617 5.688 ;
     RECT  42.22 55.776 42.829 57.48 ;
     RECT  42.829 55.776 43.297 58.248 ;
     RECT  42.46 8.496 43.549 54.6 ;
     RECT  43.297 55.776 43.549 58.68 ;
     RECT  42.371 6.672 43.621 7.464 ;
     RECT  40.504 4.656 44.129 4.68 ;
     RECT  44.269 4.512 44.389 4.536 ;
     RECT  43.621 6.576 44.413 7.464 ;
     RECT  43.657 59.808 44.417 59.832 ;
     RECT  44.413 6.288 44.485 7.464 ;
     RECT  43.549 8.496 44.485 58.68 ;
     RECT  44.389 4.464 44.965 4.536 ;
     RECT  44.965 4.176 45.385 4.536 ;
     RECT  44.485 5.568 45.385 58.68 ;
     RECT  45.385 4.176 45.608 58.68 ;
     RECT  45.608 2.148 45.712 62.652 ;
     RECT  45.712 2.418 45.904 62.382 ;
     RECT  45.904 3.936 46.115 59.64 ;
     RECT  46.115 4.128 46.757 59.64 ;
     RECT  46.757 4.128 46.865 54.12 ;
     RECT  46.865 14.496 46.901 47.784 ;
     RECT  46.901 15.312 46.937 47.784 ;
     RECT  46.757 55.104 46.937 59.64 ;
     RECT  46.865 48.864 46.973 54.12 ;
     RECT  46.937 15.36 47.009 47.784 ;
     RECT  47.009 15.36 47.045 47.688 ;
     RECT  46.865 4.128 47.081 13.368 ;
     RECT  46.937 55.104 47.081 57.24 ;
     RECT  46.937 58.416 47.081 59.64 ;
     RECT  47.045 15.36 47.117 44.856 ;
     RECT  47.045 45.984 47.153 47.688 ;
     RECT  47.081 58.704 47.153 59.64 ;
     RECT  47.081 4.128 47.261 5.16 ;
     RECT  47.117 15.36 47.261 44.808 ;
     RECT  47.153 46.032 47.261 47.688 ;
     RECT  47.261 21.12 47.297 39.72 ;
     RECT  47.153 59.616 47.297 59.64 ;
     RECT  47.081 55.104 47.333 57 ;
     RECT  47.261 16.608 47.369 19.752 ;
     RECT  47.297 21.36 47.369 39.72 ;
     RECT  47.081 6.24 47.585 13.368 ;
     RECT  46.973 49.104 47.905 54.12 ;
     RECT  47.333 55.104 47.905 56.232 ;
     RECT  47.585 6.96 47.977 13.368 ;
     RECT  47.261 40.848 48.301 44.808 ;
     RECT  47.261 46.416 48.373 47.688 ;
     RECT  47.905 49.104 48.373 56.232 ;
     RECT  48.337 57.456 48.373 57.48 ;
     RECT  47.369 21.36 48.409 38.184 ;
     RECT  47.369 39.312 48.409 39.72 ;
     RECT  48.301 40.848 48.409 45.384 ;
     RECT  48.373 46.416 48.409 57.48 ;
     RECT  47.977 6.96 48.445 13.992 ;
     RECT  47.261 15.36 48.445 15.576 ;
     RECT  47.369 16.608 48.445 19.272 ;
     RECT  48.409 21.36 48.445 39.72 ;
     RECT  48.409 40.848 48.445 57.48 ;
     RECT  48.445 20.976 48.913 57.48 ;
     RECT  48.445 6.96 48.949 19.272 ;
     RECT  48.913 20.496 48.949 57.48 ;
     RECT  48.949 6.96 49.021 57.48 ;
     RECT  49.021 6.864 49.345 57.48 ;
     RECT  47.261 4.128 49.571 4.152 ;
     RECT  49.345 6.864 49.637 57.576 ;
     RECT  49.637 6.864 49.644 57.48 ;
    LAYER M5 ;
     RECT  2.256 2.137 2.52 2.151 ;
     RECT  7.8 2.137 7.92 2.151 ;
     RECT  13.2 2.137 13.32 2.151 ;
     RECT  18.6 2.137 18.72 2.151 ;
     RECT  24 2.137 24.12 2.151 ;
     RECT  29.4 2.137 29.52 2.151 ;
     RECT  34.8 2.137 34.92 2.151 ;
     RECT  40.2 2.137 40.32 2.151 ;
     RECT  45.6 2.137 45.72 2.151 ;
     RECT  45.6 2.151 45.912 3.925 ;
     RECT  45.6 3.925 46.104 4.165 ;
     RECT  44.976 4.165 46.104 4.453 ;
     RECT  40.2 2.151 40.512 4.645 ;
     RECT  44.4 4.453 46.2 5.077 ;
     RECT  44.4 5.077 46.488 6.037 ;
     RECT  3.888 6.709 3.912 6.805 ;
     RECT  7.8 2.151 8.112 7.381 ;
     RECT  29.4 2.151 29.712 7.381 ;
     RECT  11.376 6.805 11.4 7.619 ;
     RECT  42.336 5.653 42.36 7.619 ;
     RECT  32.112 7.381 32.136 7.717 ;
     RECT  3.888 6.805 4.536 7.765 ;
     RECT  7.152 7.381 8.112 8.051 ;
     RECT  49.536 4.117 49.56 8.051 ;
     RECT  2.256 2.151 2.712 8.053 ;
     RECT  32.112 7.717 32.184 8.435 ;
     RECT  18.6 2.151 18.912 8.485 ;
     RECT  44.4 6.037 47.064 8.485 ;
     RECT  28.416 7.381 29.712 8.579 ;
     RECT  24 2.151 24.312 8.869 ;
     RECT  18.24 8.485 18.912 9.011 ;
     RECT  2.256 8.053 2.856 9.061 ;
     RECT  3.888 7.765 4.824 9.061 ;
     RECT  43.92 8.485 47.064 9.061 ;
     RECT  2.256 9.061 4.824 9.299 ;
     RECT  10.08 6.805 10.104 9.493 ;
     RECT  10.08 9.493 10.248 9.539 ;
     RECT  10.224 9.539 10.248 9.637 ;
     RECT  34.8 2.151 35.112 9.637 ;
     RECT  10.224 9.637 10.92 9.683 ;
     RECT  21.408 9.061 21.432 9.925 ;
     RECT  0.144 8.773 0.168 9.971 ;
     RECT  27.312 9.541 27.336 10.021 ;
     RECT  28.368 8.965 28.392 10.067 ;
     RECT  40.2 4.645 40.632 10.069 ;
     RECT  34.656 9.637 35.976 10.117 ;
     RECT  27.312 10.021 27.384 10.307 ;
     RECT  32.112 8.435 32.136 10.405 ;
     RECT  29.4 8.579 29.712 10.741 ;
     RECT  32.112 10.405 32.472 10.789 ;
     RECT  33.792 10.117 35.976 10.789 ;
     RECT  43.296 9.061 47.064 10.835 ;
     RECT  32.112 10.789 35.976 10.883 ;
     RECT  43.584 10.835 47.064 10.883 ;
     RECT  40.2 10.069 41.448 10.931 ;
     RECT  39.024 10.309 39.048 10.933 ;
     RECT  32.112 10.883 35.112 10.979 ;
     RECT  38.784 10.933 39.048 11.027 ;
     RECT  29.4 10.741 30.696 11.075 ;
     RECT  2.256 9.299 4.536 11.125 ;
     RECT  21.36 9.925 21.432 11.219 ;
     RECT  38.784 11.027 38.808 11.219 ;
     RECT  32.112 10.979 32.472 11.317 ;
     RECT  37.008 11.173 37.032 11.365 ;
     RECT  24 8.869 25.08 11.459 ;
     RECT  43.584 10.883 47.016 11.459 ;
     RECT  0.192 10.741 0.216 11.605 ;
     RECT  21.408 11.219 21.432 11.939 ;
     RECT  24 11.459 24.312 11.941 ;
     RECT  26.208 10.645 26.232 11.941 ;
     RECT  33.792 10.979 35.112 11.941 ;
     RECT  2.256 11.125 5.16 12.035 ;
     RECT  37.008 11.365 37.608 12.035 ;
     RECT  44.928 11.459 47.016 12.083 ;
     RECT  5.136 12.035 5.16 12.179 ;
     RECT  42 11.413 42.024 12.227 ;
     RECT  31.536 11.317 32.472 12.371 ;
     RECT  37.584 12.035 37.608 12.467 ;
     RECT  40.2 10.931 40.632 12.517 ;
     RECT  44.928 12.083 46.104 12.517 ;
     RECT  27.36 10.307 27.384 12.563 ;
     RECT  29.4 11.075 29.832 12.563 ;
     RECT  25.488 11.941 26.232 12.611 ;
     RECT  13.2 2.151 13.512 12.757 ;
     RECT  23.808 11.941 24.312 12.853 ;
     RECT  2.256 12.035 3.96 13.045 ;
     RECT  13.2 12.757 13.704 13.093 ;
     RECT  10.896 9.683 10.92 13.139 ;
     RECT  33.456 11.941 35.112 13.139 ;
     RECT  0.144 11.605 0.216 13.187 ;
     RECT  43.584 11.459 43.608 13.285 ;
     RECT  23.664 12.853 24.312 13.331 ;
     RECT  43.104 13.285 43.608 13.331 ;
     RECT  7.8 8.051 8.112 13.477 ;
     RECT  2.256 13.045 4.68 13.525 ;
     RECT  5.664 12.757 5.688 13.525 ;
     RECT  34.8 13.139 35.112 13.525 ;
     RECT  32.448 12.371 32.472 13.573 ;
     RECT  43.104 13.331 43.128 13.573 ;
     RECT  34.8 13.525 35.88 13.621 ;
     RECT  29.4 12.563 29.712 13.669 ;
     RECT  25.488 12.611 25.512 13.715 ;
     RECT  44.64 12.517 46.104 13.715 ;
     RECT  33.456 13.139 33.48 14.197 ;
     RECT  34.8 13.621 36.168 14.197 ;
     RECT  9.648 13.333 9.672 14.291 ;
     RECT  2.256 13.525 5.688 14.435 ;
     RECT  31.536 13.573 32.472 14.435 ;
     RECT  45.6 13.715 46.104 14.437 ;
     RECT  31.92 14.435 32.472 14.485 ;
     RECT  33.456 14.197 36.168 14.485 ;
     RECT  0.144 13.187 0.168 14.581 ;
     RECT  16.944 13.381 16.968 14.675 ;
     RECT  0.144 14.581 0.264 14.771 ;
     RECT  31.92 14.485 36.168 14.819 ;
     RECT  31.92 14.819 36.072 14.867 ;
     RECT  42.48 13.573 43.128 14.867 ;
     RECT  28.944 13.669 29.712 14.915 ;
     RECT  43.104 14.867 43.128 14.915 ;
     RECT  18.432 9.011 18.912 14.963 ;
     RECT  34.224 14.867 36.072 14.963 ;
     RECT  38.832 13.573 38.856 15.061 ;
     RECT  40.2 12.517 41.016 15.349 ;
     RECT  0.144 14.771 0.168 15.491 ;
     RECT  0.192 15.733 0.216 15.877 ;
     RECT  21.888 13.429 21.912 15.877 ;
     RECT  21.888 15.877 22.2 15.923 ;
     RECT  0.192 15.877 0.312 16.019 ;
     RECT  31.92 14.867 32.52 16.019 ;
     RECT  45.6 14.437 46.776 16.019 ;
     RECT  45.6 16.019 46.008 16.163 ;
     RECT  22.176 15.923 22.2 16.213 ;
     RECT  0.192 16.019 0.216 16.307 ;
     RECT  31.92 16.019 31.944 16.307 ;
     RECT  40.2 15.349 41.112 16.405 ;
     RECT  7.8 13.477 8.472 16.499 ;
     RECT  2.256 14.435 5.256 16.595 ;
     RECT  38.016 15.061 38.856 16.595 ;
     RECT  0.144 16.501 0.168 16.691 ;
     RECT  22.176 16.213 22.92 16.787 ;
     RECT  43.488 16.837 43.512 16.933 ;
     RECT  2.256 16.595 5.16 17.123 ;
     RECT  13.2 13.093 14.232 17.123 ;
     RECT  22.176 16.787 22.2 17.123 ;
     RECT  34.8 14.963 36.072 17.171 ;
     RECT  34.8 17.171 35.112 17.557 ;
     RECT  7.8 16.499 8.112 17.605 ;
     RECT  38.016 16.595 38.04 17.653 ;
     RECT  10.848 15.973 10.872 17.699 ;
     RECT  18.6 14.963 18.912 17.701 ;
     RECT  20.256 17.605 20.28 17.701 ;
     RECT  0.288 17.605 0.312 17.747 ;
     RECT  43.488 16.933 43.896 17.891 ;
     RECT  28.224 16.261 28.248 18.131 ;
     RECT  2.256 17.123 4.488 18.133 ;
     RECT  5.52 17.605 5.64 18.133 ;
     RECT  34.704 17.557 35.112 18.133 ;
     RECT  45.6 16.163 45.912 18.133 ;
     RECT  47.04 16.501 47.064 18.133 ;
     RECT  0.24 18.133 0.264 18.181 ;
     RECT  40.2 16.405 41.448 18.371 ;
     RECT  2.256 18.133 5.64 18.419 ;
     RECT  38.016 17.653 38.088 18.419 ;
     RECT  2.256 18.419 5.544 18.707 ;
     RECT  40.2 18.371 40.512 18.709 ;
     RECT  0.144 18.181 0.264 18.757 ;
     RECT  7.44 17.605 8.112 18.947 ;
     RECT  18.6 17.701 20.28 18.947 ;
     RECT  34.704 18.133 35.544 18.947 ;
     RECT  0.144 18.757 0.36 18.995 ;
     RECT  19.92 18.947 20.28 18.997 ;
     RECT  18.6 18.947 18.912 19.333 ;
     RECT  38.016 18.419 38.04 19.427 ;
     RECT  19.92 18.997 20.568 19.475 ;
     RECT  39.696 18.709 40.512 19.477 ;
     RECT  45.6 18.133 47.064 19.715 ;
     RECT  0.144 18.995 0.312 19.955 ;
     RECT  7.8 18.947 8.112 19.957 ;
     RECT  39.696 19.477 41.304 20.003 ;
     RECT  47.04 19.715 47.064 20.003 ;
     RECT  44.496 18.757 44.52 20.197 ;
     RECT  45.6 19.715 45.912 20.197 ;
     RECT  16.368 14.821 16.392 20.579 ;
     RECT  17.856 19.333 18.912 20.579 ;
     RECT  40.2 20.003 41.304 20.579 ;
     RECT  43.488 17.891 43.512 20.627 ;
     RECT  34.704 18.947 35.112 20.629 ;
     RECT  2.256 18.707 5.4 20.723 ;
     RECT  7.8 19.957 8.232 20.725 ;
     RECT  24 13.331 24.312 20.821 ;
     RECT  38.304 20.149 38.328 21.013 ;
     RECT  20.256 19.475 20.568 21.061 ;
     RECT  38.016 21.013 38.328 21.061 ;
     RECT  0.144 19.955 0.216 21.155 ;
     RECT  37.584 21.061 38.328 21.155 ;
     RECT  24 20.821 24.408 21.157 ;
     RECT  20.256 21.061 21.24 21.395 ;
     RECT  24 21.157 24.504 21.491 ;
     RECT  4.704 20.723 5.4 21.587 ;
     RECT  44.496 20.197 45.912 21.635 ;
     RECT  29.4 14.915 29.712 21.637 ;
     RECT  40.2 20.579 40.512 21.637 ;
     RECT  0.24 21.157 0.264 21.731 ;
     RECT  2.256 20.723 3.432 21.731 ;
     RECT  24 21.491 24.408 21.925 ;
     RECT  29.4 21.637 30.504 21.971 ;
     RECT  4.992 21.587 5.4 22.069 ;
     RECT  37.584 21.155 38.04 22.165 ;
     RECT  18.24 20.579 18.912 22.259 ;
     RECT  21.216 21.395 21.24 22.259 ;
     RECT  44.688 21.635 45.912 22.259 ;
     RECT  4.992 22.069 6.264 22.451 ;
     RECT  23.664 21.925 24.408 22.499 ;
     RECT  24 22.499 24.408 22.643 ;
     RECT  4.992 22.451 5.016 22.835 ;
     RECT  6.144 22.451 6.264 22.835 ;
     RECT  7.8 20.725 9.048 22.835 ;
     RECT  31.92 22.213 31.944 22.883 ;
     RECT  33.312 20.485 33.336 23.075 ;
     RECT  36.432 22.549 36.456 23.173 ;
     RECT  37.584 22.165 38.184 23.173 ;
     RECT  28.08 21.301 28.104 23.317 ;
     RECT  34.512 20.629 35.112 23.317 ;
     RECT  27.216 23.317 28.104 23.363 ;
     RECT  13.2 17.123 13.944 23.555 ;
     RECT  24 22.643 24.312 23.605 ;
     RECT  34.512 23.317 35.352 23.651 ;
     RECT  2.256 21.731 2.712 23.797 ;
     RECT  6.144 22.835 6.168 24.083 ;
     RECT  36.432 23.173 38.184 24.371 ;
     RECT  34.8 23.651 35.352 24.563 ;
     RECT  29.4 21.971 29.712 24.709 ;
     RECT  40.2 21.637 41.064 24.757 ;
     RECT  31.296 23.029 31.32 24.899 ;
     RECT  0.24 23.365 0.264 24.901 ;
     RECT  0.24 24.901 0.312 25.045 ;
     RECT  0.192 25.045 0.312 25.091 ;
     RECT  10.512 21.925 10.536 25.091 ;
     RECT  42.624 25.045 42.648 25.093 ;
     RECT  2.256 23.797 3.048 25.139 ;
     RECT  40.2 24.757 41.208 25.187 ;
     RECT  0.192 25.091 0.216 25.285 ;
     RECT  13.2 23.555 13.512 25.333 ;
     RECT  14.784 23.701 14.808 25.333 ;
     RECT  29.4 24.709 29.88 25.475 ;
     RECT  42.624 25.093 43.32 25.669 ;
     RECT  0.144 25.285 0.216 25.715 ;
     RECT  13.2 25.333 14.808 26.003 ;
     RECT  18.48 22.259 18.912 26.051 ;
     RECT  2.256 25.139 2.808 26.101 ;
     RECT  27.216 23.363 27.24 26.243 ;
     RECT  42.624 25.669 43.944 26.243 ;
     RECT  13.2 26.003 14.088 26.341 ;
     RECT  22.176 25.861 22.536 26.389 ;
     RECT  34.8 24.563 35.112 26.485 ;
     RECT  45.6 22.259 45.912 26.485 ;
     RECT  22.128 26.389 22.536 26.675 ;
     RECT  34.704 26.485 35.112 26.675 ;
     RECT  45.6 26.485 46.632 26.675 ;
     RECT  40.2 25.187 40.512 26.677 ;
     RECT  29.4 25.475 29.712 26.725 ;
     RECT  6.624 26.197 6.648 26.771 ;
     RECT  17.28 25.765 17.304 26.771 ;
     RECT  7.8 22.835 8.112 26.773 ;
     RECT  0.192 25.715 0.216 26.819 ;
     RECT  43.68 26.243 43.944 26.867 ;
     RECT  7.632 26.773 8.112 27.011 ;
     RECT  2.256 26.101 2.856 27.301 ;
     RECT  18.6 26.051 18.912 27.301 ;
     RECT  45.6 26.675 45.912 27.301 ;
     RECT  34.8 26.675 35.112 27.733 ;
     RECT  2.256 27.301 3.432 27.875 ;
     RECT  18.6 27.301 19.224 28.067 ;
     RECT  34.272 27.733 35.112 28.307 ;
     RECT  45.168 27.301 45.912 28.307 ;
     RECT  31.152 25.045 31.176 28.309 ;
     RECT  0.144 28.213 0.168 28.403 ;
     RECT  45.6 28.307 45.912 28.405 ;
     RECT  16.272 26.005 16.296 28.453 ;
     RECT  15.984 28.453 16.296 28.499 ;
     RECT  36.432 24.371 38.04 28.547 ;
     RECT  40.2 26.677 41.064 28.643 ;
     RECT  5.856 27.301 5.88 28.693 ;
     RECT  10.656 25.621 10.68 28.837 ;
     RECT  10.656 28.837 11.4 28.883 ;
     RECT  4.464 27.877 4.488 28.981 ;
     RECT  5.856 28.693 5.976 28.981 ;
     RECT  33.024 27.205 33.048 29.123 ;
     RECT  42.624 26.243 42.648 29.123 ;
     RECT  31.104 28.309 31.176 29.171 ;
     RECT  28.512 26.725 29.712 29.507 ;
     RECT  43.68 26.867 43.704 29.507 ;
     RECT  11.376 28.883 11.4 29.605 ;
     RECT  22.128 26.675 22.2 29.653 ;
     RECT  36.432 28.547 37.08 29.699 ;
     RECT  22.128 29.653 22.776 29.795 ;
     RECT  7.8 27.011 8.112 30.037 ;
     RECT  4.464 28.981 5.976 30.131 ;
     RECT  7.8 30.037 9.096 30.133 ;
     RECT  15.984 28.499 16.008 30.275 ;
     RECT  22.128 29.795 22.2 30.275 ;
     RECT  45.6 28.405 46.008 30.325 ;
     RECT  7.632 30.133 9.096 30.421 ;
     RECT  7.632 30.421 10.056 30.563 ;
     RECT  7.632 30.563 9.576 30.565 ;
     RECT  36.672 29.699 37.08 30.565 ;
     RECT  38.064 29.029 38.088 30.565 ;
     RECT  4.464 30.131 4.488 30.709 ;
     RECT  5.952 30.131 5.976 30.709 ;
     RECT  31.104 29.171 31.128 30.709 ;
     RECT  5.952 30.709 6.6 30.805 ;
     RECT  7.584 30.565 9.576 30.805 ;
     RECT  3.744 30.709 4.488 30.851 ;
     RECT  11.376 29.605 11.976 30.851 ;
     RECT  31.104 30.709 31.896 30.899 ;
     RECT  18.6 28.067 18.912 30.997 ;
     RECT  49.488 30.853 49.512 31.043 ;
     RECT  31.872 30.899 31.896 31.139 ;
     RECT  36.672 30.565 38.088 31.139 ;
     RECT  13.104 26.341 14.088 31.189 ;
     RECT  40.2 28.643 40.512 31.237 ;
     RECT  5.952 30.805 9.576 31.379 ;
     RECT  22.128 30.275 22.152 31.379 ;
     RECT  45.6 30.325 46.2 31.379 ;
     RECT  6.432 31.379 8.112 31.427 ;
     RECT  43.344 29.701 43.656 31.669 ;
     RECT  24 23.605 24.648 31.765 ;
     RECT  43.344 31.669 43.848 31.811 ;
     RECT  2.256 27.875 2.712 31.861 ;
     RECT  3.744 30.851 3.96 31.861 ;
     RECT  9.552 31.379 9.576 31.955 ;
     RECT  43.344 31.811 43.704 31.955 ;
     RECT  16.416 31.861 16.44 31.957 ;
     RECT  6.576 31.427 8.112 32.195 ;
     RECT  40.2 31.237 40.92 32.197 ;
     RECT  42.144 31.765 42.168 32.197 ;
     RECT  2.256 31.861 3.96 32.291 ;
     RECT  40.2 32.197 42.168 32.339 ;
     RECT  18.6 30.997 19.896 32.341 ;
     RECT  47.952 32.245 47.976 32.435 ;
     RECT  43.488 31.955 43.704 32.483 ;
     RECT  7.536 32.195 8.112 32.579 ;
     RECT  23.376 31.765 24.648 32.771 ;
     RECT  7.584 32.579 8.112 32.869 ;
     RECT  7.584 32.869 9.096 33.059 ;
     RECT  40.2 32.339 40.92 33.061 ;
     RECT  16.416 31.957 17.112 33.107 ;
     RECT  18.6 32.341 19.944 33.107 ;
     RECT  16.992 33.107 17.112 33.155 ;
     RECT  2.4 32.291 3.96 33.493 ;
     RECT  5.088 33.301 5.112 33.493 ;
     RECT  0.144 33.301 0.168 33.587 ;
     RECT  2.4 33.493 5.112 33.589 ;
     RECT  36.672 31.139 36.984 33.637 ;
     RECT  31.536 33.541 31.56 33.683 ;
     RECT  42.144 32.339 42.168 33.683 ;
     RECT  43.488 32.483 43.656 33.731 ;
     RECT  36.672 33.637 37.08 33.779 ;
     RECT  26.784 33.013 26.808 34.117 ;
     RECT  13.104 31.189 14.472 34.165 ;
     RECT  2.4 33.589 6.024 34.259 ;
     RECT  7.8 33.059 9.096 34.259 ;
     RECT  18.6 33.107 19.896 34.355 ;
     RECT  38.064 31.139 38.088 34.597 ;
     RECT  16.992 33.155 17.016 34.643 ;
     RECT  18.6 34.355 18.912 34.645 ;
     RECT  13.104 34.165 15.336 34.789 ;
     RECT  26.784 34.117 27.336 34.835 ;
     RECT  39.888 33.061 40.92 34.931 ;
     RECT  36.672 33.779 36.984 35.077 ;
     RECT  45.6 31.379 46.008 35.267 ;
     RECT  21.888 31.861 21.912 35.317 ;
     RECT  36.24 35.077 36.984 35.317 ;
     RECT  38.064 34.597 38.328 35.317 ;
     RECT  4.512 34.259 6.024 35.363 ;
     RECT  7.8 34.259 8.904 35.363 ;
     RECT  24 32.771 24.648 35.413 ;
     RECT  26.784 34.835 26.808 35.413 ;
     RECT  26.208 35.413 26.808 35.459 ;
     RECT  43.488 33.731 43.608 35.893 ;
     RECT  13.008 34.789 15.336 35.939 ;
     RECT  7.8 35.363 8.112 35.941 ;
     RECT  6 35.363 6.024 35.987 ;
     RECT  36.24 35.317 38.328 36.035 ;
     RECT  42.672 35.893 43.608 36.083 ;
     RECT  40.2 34.931 40.92 36.325 ;
     RECT  31.632 35.317 31.656 36.421 ;
     RECT  45.6 35.267 45.912 36.421 ;
     RECT  19.92 34.885 19.944 36.515 ;
     RECT  21.888 35.317 22.488 36.515 ;
     RECT  18 34.645 18.912 36.517 ;
     RECT  43.488 36.083 43.608 36.563 ;
     RECT  40.2 36.325 40.968 36.611 ;
     RECT  45.6 36.421 46.008 36.659 ;
     RECT  36.672 36.035 38.328 36.803 ;
     RECT  13.008 35.939 14.184 37.091 ;
     RECT  23.472 35.413 24.648 37.091 ;
     RECT  30.96 36.421 31.656 37.139 ;
     RECT  17.856 36.517 18.912 37.237 ;
     RECT  15.312 35.939 15.336 37.283 ;
     RECT  16.416 34.741 16.44 37.429 ;
     RECT  40.2 36.611 40.92 37.573 ;
     RECT  15.936 37.429 16.44 37.667 ;
     RECT  21.888 36.515 21.912 37.715 ;
     RECT  2.4 34.259 2.712 37.765 ;
     RECT  40.08 37.573 40.92 38.005 ;
     RECT  38.304 36.803 38.328 38.101 ;
     RECT  13.008 37.091 13.656 38.149 ;
     RECT  36.672 36.803 36.984 38.149 ;
     RECT  38.304 38.101 38.76 38.149 ;
     RECT  42.576 37.429 42.6 38.195 ;
     RECT  17.664 37.237 18.912 38.243 ;
     RECT  36.672 38.149 38.76 38.339 ;
     RECT  2.4 37.765 2.856 38.579 ;
     RECT  40.08 38.005 41.544 38.675 ;
     RECT  45.6 36.659 45.912 38.677 ;
     RECT  10.656 33.541 10.68 38.725 ;
     RECT  26.208 35.459 26.232 38.725 ;
     RECT  26.064 38.725 26.232 38.771 ;
     RECT  15.936 37.667 15.96 38.819 ;
     RECT  33.024 37.909 33.048 38.819 ;
     RECT  37.92 38.339 38.76 38.819 ;
     RECT  45.6 38.677 46.104 38.821 ;
     RECT  9.696 38.725 10.68 38.915 ;
     RECT  7.104 35.941 8.112 39.107 ;
     RECT  31.632 37.139 31.656 39.395 ;
     RECT  9.696 38.915 9.72 39.443 ;
     RECT  40.2 38.675 41.544 39.443 ;
     RECT  40.2 39.443 40.92 39.491 ;
     RECT  45.6 38.821 46.728 39.539 ;
     RECT  37.92 38.819 37.944 39.877 ;
     RECT  12.24 38.149 13.656 39.923 ;
     RECT  40.2 39.491 40.872 39.923 ;
     RECT  45.6 39.539 46.104 39.923 ;
     RECT  26.064 38.771 26.088 40.165 ;
     RECT  37.92 39.877 38.76 40.357 ;
     RECT  37.632 40.357 38.76 40.403 ;
     RECT  2.4 38.579 2.808 40.405 ;
     RECT  43.776 37.429 43.8 40.499 ;
     RECT  19.92 38.677 19.944 40.547 ;
     RECT  2.4 40.405 4.152 40.981 ;
     RECT  36.192 38.677 36.216 41.077 ;
     RECT  36.192 41.077 36.456 41.123 ;
     RECT  18.48 38.243 18.912 41.125 ;
     RECT  5.664 40.309 5.688 41.221 ;
     RECT  2.4 40.981 4.536 41.269 ;
     RECT  5.664 41.221 6.024 41.269 ;
     RECT  42.144 40.981 42.168 41.557 ;
     RECT  2.4 41.269 6.024 41.651 ;
     RECT  18.48 41.125 19.416 41.651 ;
     RECT  38.736 40.403 38.76 41.651 ;
     RECT  41.52 41.557 42.168 41.651 ;
     RECT  45.6 39.923 45.912 41.893 ;
     RECT  26.064 40.165 26.232 41.939 ;
     RECT  7.392 39.107 8.112 41.941 ;
     RECT  37.632 40.403 37.656 41.989 ;
     RECT  21.792 38.149 21.816 42.133 ;
     RECT  45.024 41.893 45.912 42.179 ;
     RECT  21.792 42.133 21.96 42.227 ;
     RECT  13.008 39.923 13.656 42.275 ;
     RECT  7.392 41.941 8.616 42.613 ;
     RECT  21.936 42.227 21.96 42.613 ;
     RECT  40.2 39.923 40.512 42.709 ;
     RECT  3.888 41.651 6.024 42.803 ;
     RECT  30.96 41.941 30.984 42.803 ;
     RECT  37.632 41.989 38.232 42.803 ;
     RECT  26.064 41.939 26.088 42.947 ;
     RECT  7.2 42.613 8.616 42.995 ;
     RECT  3.936 42.803 6.024 43.141 ;
     RECT  7.2 42.995 8.112 43.141 ;
     RECT  3.936 43.141 8.112 43.235 ;
     RECT  0.288 43.045 0.312 43.285 ;
     RECT  39.984 42.709 40.512 43.285 ;
     RECT  14.976 39.013 15 43.379 ;
     RECT  18.48 41.651 18.912 43.379 ;
     RECT  21.936 42.613 22.056 43.379 ;
     RECT  36.432 41.123 36.456 43.379 ;
     RECT  0.192 43.285 0.312 43.427 ;
     RECT  0.192 43.427 0.216 43.475 ;
     RECT  34.8 28.307 35.112 43.669 ;
     RECT  22.8 43.525 22.824 43.715 ;
     RECT  25.824 43.285 25.848 43.715 ;
     RECT  24 37.091 24.648 43.811 ;
     RECT  34.224 43.669 35.112 43.811 ;
     RECT  38.208 42.803 38.232 43.811 ;
     RECT  2.4 41.651 2.856 43.861 ;
     RECT  10.224 43.765 10.248 43.861 ;
     RECT  4.416 43.235 8.112 43.907 ;
     RECT  34.656 43.811 35.112 43.909 ;
     RECT  4.416 43.907 5.832 44.003 ;
     RECT  2.4 43.861 3.24 44.437 ;
     RECT  6.816 43.907 8.112 44.483 ;
     RECT  39.456 43.285 40.512 44.483 ;
     RECT  41.52 41.651 41.544 44.483 ;
     RECT  0.144 43.669 0.168 44.627 ;
     RECT  13.104 42.275 13.656 44.627 ;
     RECT  14.784 44.437 14.808 44.723 ;
     RECT  34.656 43.909 35.208 44.915 ;
     RECT  2.304 44.437 3.24 44.965 ;
     RECT  4.416 44.003 5.544 44.965 ;
     RECT  31.968 44.341 31.992 45.059 ;
     RECT  4.416 44.965 6.216 45.107 ;
     RECT  40.2 44.483 40.512 45.301 ;
     RECT  7.2 44.483 8.112 45.491 ;
     RECT  18.6 43.379 18.912 45.541 ;
     RECT  40.2 45.301 40.872 45.541 ;
     RECT  0.192 44.965 0.216 45.781 ;
     RECT  10.08 43.861 10.248 46.117 ;
     RECT  34.656 44.915 35.112 46.163 ;
     RECT  40.2 45.541 41.544 46.499 ;
     RECT  10.08 46.117 10.536 46.501 ;
     RECT  0.144 45.781 0.216 46.547 ;
     RECT  10.08 46.501 10.824 46.787 ;
     RECT  40.2 46.499 40.872 46.883 ;
     RECT  4.608 45.107 6.216 47.173 ;
     RECT  7.8 45.491 8.112 47.173 ;
     RECT  26.256 46.213 26.28 47.315 ;
     RECT  0.144 46.547 0.168 47.363 ;
     RECT  10.512 46.787 10.824 47.413 ;
     RECT  40.2 46.883 40.512 47.413 ;
     RECT  18.6 45.541 19.416 47.845 ;
     RECT  18.048 47.845 19.416 47.891 ;
     RECT  2.304 44.965 3.432 47.939 ;
     RECT  13.2 44.627 13.656 47.939 ;
     RECT  39.36 47.413 40.512 48.037 ;
     RECT  39.36 48.037 40.92 48.179 ;
     RECT  10.512 47.413 10.872 48.229 ;
     RECT  39.36 48.179 40.512 48.277 ;
     RECT  2.4 47.939 3.432 48.421 ;
     RECT  4.608 47.173 8.112 48.421 ;
     RECT  34.8 46.163 35.112 48.757 ;
     RECT  10.512 48.229 11.448 48.947 ;
     RECT  36.288 46.693 36.312 48.949 ;
     RECT  9.36 48.085 9.384 48.997 ;
     RECT  45.6 42.179 45.912 48.997 ;
     RECT  0.288 48.709 0.312 49.043 ;
     RECT  34.128 48.757 35.112 49.091 ;
     RECT  45.024 48.997 45.912 49.235 ;
     RECT  45.6 49.235 45.912 49.237 ;
     RECT  13.2 47.939 13.512 49.477 ;
     RECT  11.424 48.947 11.448 49.523 ;
     RECT  39.312 48.277 40.512 49.715 ;
     RECT  9.36 48.997 10.104 49.763 ;
     RECT  22.32 46.117 22.344 50.051 ;
     RECT  45.6 49.237 46.2 50.051 ;
     RECT  0.192 49.909 0.216 50.099 ;
     RECT  27.888 46.693 27.912 50.147 ;
     RECT  2.4 48.421 8.112 50.195 ;
     RECT  32.16 45.829 32.184 50.195 ;
     RECT  2.4 50.195 3.24 50.243 ;
     RECT  4.464 50.195 8.112 50.771 ;
     RECT  12.576 49.477 13.512 50.771 ;
     RECT  18.048 47.891 18.912 50.819 ;
     RECT  26.88 50.101 26.904 50.821 ;
     RECT  39.792 49.715 40.512 50.821 ;
     RECT  4.464 50.771 5.208 50.867 ;
     RECT  36.288 48.949 36.408 50.963 ;
     RECT  15.12 48.421 15.144 50.965 ;
     RECT  39.792 50.821 40.92 50.965 ;
     RECT  2.4 50.243 2.856 51.253 ;
     RECT  4.464 50.867 5.016 51.253 ;
     RECT  15.12 50.965 15.576 51.395 ;
     RECT  39.744 50.965 40.92 51.395 ;
     RECT  22.8 51.349 22.824 51.491 ;
     RECT  24 43.811 24.312 51.781 ;
     RECT  45.6 50.051 46.008 51.875 ;
     RECT  2.4 51.253 5.016 51.923 ;
     RECT  6.192 50.771 6.504 51.923 ;
     RECT  39.744 51.395 40.512 51.971 ;
     RECT  26.208 50.821 26.904 52.259 ;
     RECT  6.192 51.923 6.216 52.309 ;
     RECT  26.88 52.259 26.904 52.357 ;
     RECT  26.88 52.357 27.048 52.403 ;
     RECT  44.352 49.477 44.376 52.499 ;
     RECT  33.264 51.829 33.288 52.739 ;
     RECT  45.6 51.875 45.912 52.885 ;
     RECT  2.4 51.923 4.92 52.981 ;
     RECT  19.92 51.637 19.944 53.075 ;
     RECT  39.792 51.971 40.512 53.075 ;
     RECT  6.048 52.309 6.216 53.363 ;
     RECT  45.6 52.885 46.632 53.413 ;
     RECT  23.088 51.781 24.312 53.509 ;
     RECT  7.8 50.771 8.112 53.557 ;
     RECT  9.36 49.763 9.384 53.557 ;
     RECT  45.504 53.413 46.632 53.557 ;
     RECT  9.36 53.557 10.344 53.603 ;
     RECT  11.472 52.069 11.496 53.603 ;
     RECT  45.504 53.557 46.728 53.651 ;
     RECT  21.84 53.509 24.312 54.085 ;
     RECT  36.384 50.963 36.408 54.179 ;
     RECT  2.4 52.981 5.016 54.275 ;
     RECT  18.6 50.819 18.912 54.325 ;
     RECT  21.312 54.085 24.312 54.371 ;
     RECT  7.584 53.557 8.112 54.373 ;
     RECT  40.2 53.075 40.512 54.373 ;
     RECT  24 54.371 24.312 54.469 ;
     RECT  25.488 54.085 25.512 54.565 ;
     RECT  27.024 52.403 27.048 54.565 ;
     RECT  4.176 54.275 5.016 54.755 ;
     RECT  6.048 53.363 6.072 54.755 ;
     RECT  21.312 54.371 22.776 54.755 ;
     RECT  25.488 54.565 27.048 54.755 ;
     RECT  7.488 54.373 8.112 54.803 ;
     RECT  2.4 54.275 3.048 55.237 ;
     RECT  4.176 54.755 4.776 55.237 ;
     RECT  18.6 54.325 19.032 55.237 ;
     RECT  45.6 53.651 46.728 55.237 ;
     RECT  39.936 54.373 40.512 55.283 ;
     RECT  24 54.469 24.408 55.331 ;
     RECT  26.208 54.755 27.048 55.331 ;
     RECT  40.08 55.283 40.512 55.763 ;
     RECT  42.144 53.413 42.408 55.811 ;
     RECT  18.6 55.237 19.512 55.955 ;
     RECT  0.144 56.005 0.168 56.053 ;
     RECT  7.8 54.803 8.112 56.053 ;
     RECT  0.144 56.053 0.264 56.195 ;
     RECT  27.024 55.331 27.048 56.195 ;
     RECT  0.24 56.195 0.264 56.339 ;
     RECT  10.32 53.603 10.344 56.389 ;
     RECT  29.4 29.507 29.712 56.389 ;
     RECT  21.312 54.755 21.336 56.437 ;
     RECT  2.4 55.237 4.776 56.483 ;
     RECT  6.24 55.237 6.264 56.483 ;
     RECT  10.32 56.389 10.968 56.483 ;
     RECT  31.104 55.813 31.128 56.677 ;
     RECT  10.944 56.483 10.968 56.915 ;
     RECT  15.552 51.395 15.576 57.059 ;
     RECT  20.352 56.437 21.336 57.059 ;
     RECT  31.104 56.677 32.088 57.059 ;
     RECT  42.144 55.811 42.168 57.059 ;
     RECT  7.44 56.053 8.112 57.061 ;
     RECT  32.064 57.059 32.088 57.299 ;
     RECT  45.6 55.237 46.776 57.635 ;
     RECT  29.4 56.389 29.832 57.875 ;
     RECT  45.6 57.635 46.728 58.117 ;
     RECT  2.4 56.483 4.488 58.163 ;
     RECT  6.816 57.061 8.112 58.163 ;
     RECT  21.312 57.059 21.336 58.163 ;
     RECT  44.736 58.117 46.728 58.211 ;
     RECT  7.44 58.163 8.112 58.403 ;
     RECT  44.736 58.211 45.912 58.691 ;
     RECT  2.4 58.163 2.712 62.649 ;
     RECT  7.8 58.403 8.112 62.649 ;
     RECT  13.2 50.771 13.512 62.649 ;
     RECT  18.6 55.955 18.912 62.649 ;
     RECT  24 55.331 24.312 62.649 ;
     RECT  29.4 57.875 29.712 62.649 ;
     RECT  34.8 49.091 35.112 62.649 ;
     RECT  40.2 55.763 40.512 62.649 ;
     RECT  45.6 58.691 45.912 62.649 ;
     RECT  2.4 62.649 2.52 62.663 ;
     RECT  7.8 62.649 7.92 62.663 ;
     RECT  13.2 62.649 13.32 62.663 ;
     RECT  18.6 62.649 18.72 62.663 ;
     RECT  24 62.649 24.12 62.663 ;
     RECT  29.4 62.649 29.52 62.663 ;
     RECT  34.8 62.649 34.92 62.663 ;
     RECT  40.2 62.649 40.32 62.663 ;
     RECT  45.6 62.649 45.72 62.663 ;
  END
END ot_qwen_tree_delay8_t
END LIBRARY
